VERSION 5.8 ;
BUSBITCHARS "[]" ;
DIVIDERCHAR "/" ;

PROPERTYDEFINITIONS
  MACRO CatenaDesignType STRING ;
  MACRO oaTaper STRING ;
END PROPERTYDEFINITIONS

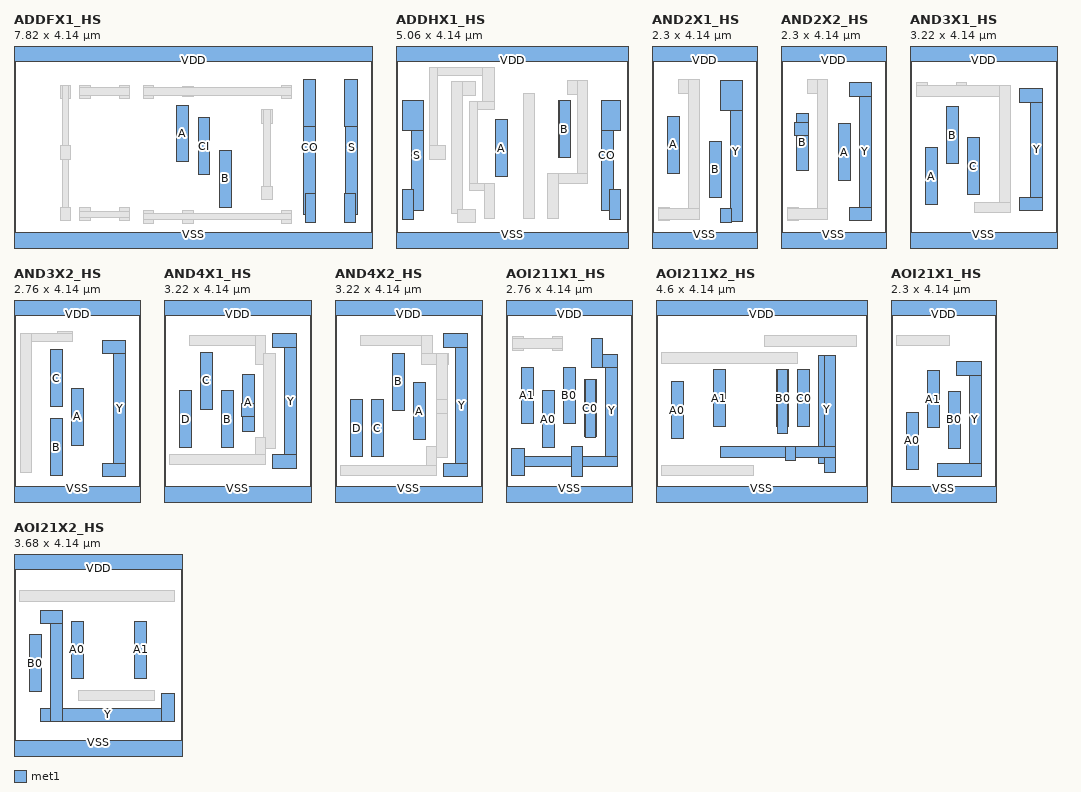
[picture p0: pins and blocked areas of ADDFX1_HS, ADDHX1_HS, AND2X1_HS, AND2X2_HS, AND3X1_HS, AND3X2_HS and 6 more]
MACRO ADDFX1_HS
  CLASS CORE ;
  ORIGIN 0 0 ;
  FOREIGN ADDFX1_HS 0 0 ;
  SIZE 7.82 BY 4.14 ;
  SYMMETRY X Y ;
  SITE CoreSite ;
  PIN A
    DIRECTION INPUT ;
    USE SIGNAL ;
    ANTENNAMODEL OXIDE1 ;
      ANTENNAGATEAREA 0.723 LAYER met1 ;
      ANTENNAMAXAREACAR 1.168603 LAYER met1 ;
      ANTENNAMAXSIDEAREACAR 1.233748 LAYER met1 ;
    PORT
      LAYER met1 ;
        RECT 3.55 1.745 3.81 2.985 ;
    END
  END A
  PIN B
    DIRECTION INPUT ;
    USE SIGNAL ;
    ANTENNAMODEL OXIDE1 ;
      ANTENNAGATEAREA 0.723 LAYER met1 ;
      ANTENNAMAXAREACAR 1.168603 LAYER met1 ;
      ANTENNAMAXSIDEAREACAR 1.233748 LAYER met1 ;
    PORT
      LAYER met1 ;
        RECT 4.47 0.76 4.73 2 ;
    END
  END B
  PIN CI
    DIRECTION INPUT ;
    USE SIGNAL ;
    ANTENNAMODEL OXIDE1 ;
      ANTENNAGATEAREA 0.54225 LAYER met1 ;
      ANTENNAMAXAREACAR 1.504841 LAYER met1 ;
      ANTENNAMAXSIDEAREACAR 1.644998 LAYER met1 ;
    PORT
      LAYER met1 ;
        RECT 4.01 1.47 4.27 2.71 ;
        RECT 4.025 1.465 4.255 2.71 ;
    END
  END CI
  PIN CO
    DIRECTION OUTPUT ;
    USE SIGNAL ;
    ANTENNADIFFAREA 0.5883 LAYER met1 ;
    PORT
      LAYER met1 ;
        RECT 6.31 2.52 6.575 3.53 ;
        RECT 6.345 0.415 6.575 1.065 ;
        RECT 6.31 0.61 6.57 3.53 ;
    END
  END CO
  PIN S
    DIRECTION OUTPUT ;
    USE SIGNAL ;
    ANTENNADIFFAREA 0.5883 LAYER met1 ;
    PORT
      LAYER met1 ;
        RECT 7.205 2.52 7.49 3.53 ;
        RECT 7.23 0.61 7.49 3.53 ;
        RECT 7.205 0.415 7.435 1.065 ;
    END
  END S
  PIN VDD
    DIRECTION INPUT ;
    USE POWER ;
    SHAPE ABUTMENT ;
    NETEXPR "VDD VDD!" ;
    PORT
      LAYER met1 ;
        RECT 0 3.94 7.82 4.34 ;
    END
  END VDD
  PIN VSS
    DIRECTION INPUT ;
    USE GROUND ;
    SHAPE ABUTMENT ;
    NETEXPR "VSS VSS!" ;
    PORT
      LAYER met1 ;
        RECT 0 -0.2 7.82 0.2 ;
    END
  END VSS
  OBS
    LAYER met1 ;
      RECT 5.825 0.405 6.055 0.695 ;
      RECT 3.675 0.405 3.905 0.695 ;
      RECT 2.815 0.405 3.045 0.695 ;
      RECT 2.815 0.48 6.055 0.62 ;
      RECT 5.825 3.13 6.055 3.42 ;
      RECT 2.815 3.13 3.045 3.42 ;
      RECT 3.675 3.16 3.905 3.39 ;
      RECT 2.815 3.19 6.055 3.36 ;
      RECT 5.395 2.59 5.625 2.88 ;
      RECT 5.44 0.93 5.58 2.88 ;
      RECT 5.395 0.93 5.625 1.22 ;
      RECT 2.295 0.46 2.525 0.75 ;
      RECT 1.435 0.46 1.665 0.75 ;
      RECT 1.435 0.535 2.525 0.675 ;
      RECT 2.295 3.13 2.525 3.42 ;
      RECT 1.435 3.13 1.665 3.42 ;
      RECT 1.435 3.19 2.525 3.36 ;
      RECT 1.005 3.13 1.235 3.42 ;
      RECT 1.05 0.46 1.19 3.42 ;
      RECT 1.005 1.805 1.235 2.095 ;
      RECT 1.005 0.46 1.235 0.75 ;
  END
  PROPERTY CatenaDesignType "deviceLevel" ;
END ADDFX1_HS

MACRO ADDHX1_HS
  CLASS CORE ;
  ORIGIN 0 0 ;
  FOREIGN ADDHX1_HS 0 0 ;
  SIZE 5.06 BY 4.14 ;
  SYMMETRY X Y ;
  SITE CoreSite ;
  PIN A
    DIRECTION INPUT ;
    USE SIGNAL ;
    ANTENNAMODEL OXIDE1 ;
      ANTENNAGATEAREA 0.3615 LAYER met1 ;
      ANTENNAMAXAREACAR 1.184509 LAYER met1 ;
      ANTENNAMAXSIDEAREACAR 1.289073 LAYER met1 ;
    PORT
      LAYER met1 ;
        RECT 2.17 1.425 2.43 2.665 ;
    END
  END A
  PIN B
    DIRECTION INPUT ;
    USE SIGNAL ;
    ANTENNAMODEL OXIDE1 ;
      ANTENNAGATEAREA 0.54225 LAYER met1 ;
      ANTENNAMAXAREACAR 0.858276 LAYER met1 ;
      ANTENNAMAXSIDEAREACAR 0.870447 LAYER met1 ;
    PORT
      LAYER met1 ;
        RECT 3.55 1.84 3.81 3.08 ;
        RECT 3.565 1.835 3.795 3.08 ;
    END
  END B
  PIN CO
    DIRECTION OUTPUT ;
    USE SIGNAL ;
    ANTENNADIFFAREA 0.5883 LAYER met1 ;
    PORT
      LAYER met1 ;
        RECT 4.47 2.44 4.885 3.09 ;
        RECT 4.655 0.485 4.885 1.135 ;
        RECT 4.47 0.68 4.73 3.09 ;
    END
  END CO
  PIN S
    DIRECTION OUTPUT ;
    USE SIGNAL ;
    ANTENNADIFFAREA 0.5883 LAYER met1 ;
    PORT
      LAYER met1 ;
        RECT 0.145 2.44 0.59 3.09 ;
        RECT 0.33 0.68 0.59 3.09 ;
        RECT 0.145 0.485 0.375 1.135 ;
    END
  END S
  PIN VDD
    DIRECTION INPUT ;
    USE POWER ;
    SHAPE ABUTMENT ;
    NETEXPR "VDD VDD!" ;
    PORT
      LAYER met1 ;
        RECT 0 3.94 5.06 4.34 ;
    END
  END VDD
  PIN VSS
    DIRECTION INPUT ;
    USE GROUND ;
    SHAPE ABUTMENT ;
    NETEXPR "VSS VSS!" ;
    PORT
      LAYER met1 ;
        RECT 0 -0.2 5.06 0.2 ;
    END
  END VSS
  OBS
    LAYER met1 ;
      RECT 3.735 3.22 4.18 3.51 ;
      RECT 3.95 1.265 4.18 3.51 ;
      RECT 3.305 1.265 4.18 1.495 ;
      RECT 3.305 0.51 3.535 1.495 ;
      RECT 0.73 3.63 2.155 3.8 ;
      RECT 1.895 2.89 2.155 3.8 ;
      RECT 0.73 1.805 0.9 3.8 ;
      RECT 1.605 2.89 2.155 3.06 ;
      RECT 1.605 1.115 1.775 3.06 ;
      RECT 0.73 1.805 1.08 2.095 ;
      RECT 1.605 1.115 2.155 1.285 ;
      RECT 1.925 0.51 2.155 1.285 ;
      RECT 1.22 3.2 1.725 3.49 ;
      RECT 1.22 0.615 1.45 3.49 ;
      RECT 1.335 0.42 1.725 0.71 ;
      RECT 2.785 0.51 3.015 3.235 ;
  END
  PROPERTY CatenaDesignType "deviceLevel" ;
END ADDHX1_HS

MACRO AND2X1_HS
  CLASS CORE ;
  ORIGIN 0 0 ;
  FOREIGN AND2X1_HS 0 0 ;
  SIZE 2.3 BY 4.14 ;
  SYMMETRY X Y ;
  SITE CoreSite ;
  PIN A
    DIRECTION INPUT ;
    USE SIGNAL ;
    ANTENNAMODEL OXIDE1 ;
      ANTENNAGATEAREA 0.18075 LAYER met1 ;
      ANTENNAMAXAREACAR 0.484371 LAYER met1 ;
      ANTENNAMAXSIDEAREACAR 0.569848 LAYER met1 ;
    PORT
      LAYER met1 ;
        RECT 0.33 1.5 0.59 2.74 ;
    END
  END A
  PIN B
    DIRECTION INPUT ;
    USE SIGNAL ;
    ANTENNAMODEL OXIDE1 ;
      ANTENNAGATEAREA 0.18075 LAYER met1 ;
      ANTENNAMAXAREACAR 0.917012 LAYER met1 ;
      ANTENNAMAXSIDEAREACAR 1.078838 LAYER met1 ;
    PORT
      LAYER met1 ;
        RECT 1.25 0.96 1.51 2.2 ;
    END
  END B
  PIN VDD
    DIRECTION INPUT ;
    USE POWER ;
    SHAPE ABUTMENT ;
    NETEXPR "VDD VDD!" ;
    PORT
      LAYER met1 ;
        RECT 0 3.94 2.3 4.34 ;
    END
  END VDD
  PIN VSS
    DIRECTION INPUT ;
    USE GROUND ;
    SHAPE ABUTMENT ;
    NETEXPR "VSS VSS!" ;
    PORT
      LAYER met1 ;
        RECT 0 -0.2 2.3 0.2 ;
    END
  END VSS
  PIN Y
    DIRECTION OUTPUT ;
    USE SIGNAL ;
    ANTENNADIFFAREA 0.5883 LAYER met1 ;
    PORT
      LAYER met1 ;
        RECT 1.495 2.86 1.97 3.51 ;
        RECT 1.71 0.44 1.97 3.51 ;
        RECT 1.495 0.43 1.725 0.72 ;
    END
  END Y
  OBS
    LAYER met1 ;
      RECT 0.575 3.24 1.03 3.53 ;
      RECT 0.8 0.49 1.03 3.53 ;
      RECT 0.145 0.46 0.375 0.75 ;
      RECT 0.145 0.49 1.03 0.72 ;
  END
  PROPERTY CatenaDesignType "deviceLevel" ;
END AND2X1_HS

MACRO AND2X2_HS
  CLASS CORE ;
  ORIGIN 0 0 ;
  FOREIGN AND2X2_HS 0 0 ;
  SIZE 2.3 BY 4.14 ;
  SYMMETRY X Y ;
  SITE CoreSite ;
  PIN A
    DIRECTION INPUT ;
    USE SIGNAL ;
    ANTENNAMODEL OXIDE1 ;
      ANTENNAGATEAREA 0.18075 LAYER met1 ;
      ANTENNAMAXAREACAR 0.935823 LAYER met1 ;
      ANTENNAMAXSIDEAREACAR 1.100968 LAYER met1 ;
    PORT
      LAYER met1 ;
        RECT 1.25 1.34 1.51 2.58 ;
    END
  END A
  PIN B
    DIRECTION INPUT ;
    USE SIGNAL ;
    ANTENNAMODEL OXIDE1 ;
      ANTENNAGATEAREA 0.18075 LAYER met1 ;
      ANTENNAMAXAREACAR 0.672476 LAYER met1 ;
      ANTENNAMAXSIDEAREACAR 0.791148 LAYER met1 ;
    PORT
      LAYER met1 ;
        RECT 0.33 1.55 0.59 2.79 ;
        RECT 0.285 2.31 0.59 2.6 ;
    END
  END B
  PIN VDD
    DIRECTION INPUT ;
    USE POWER ;
    SHAPE ABUTMENT ;
    NETEXPR "VDD VDD!" ;
    PORT
      LAYER met1 ;
        RECT 0 3.94 2.3 4.34 ;
    END
  END VDD
  PIN VSS
    DIRECTION INPUT ;
    USE GROUND ;
    SHAPE ABUTMENT ;
    NETEXPR "VSS VSS!" ;
    PORT
      LAYER met1 ;
        RECT 0 -0.2 2.3 0.2 ;
    END
  END VSS
  PIN Y
    DIRECTION OUTPUT ;
    USE SIGNAL ;
    ANTENNADIFFAREA 0.6216 LAYER met1 ;
    PORT
      LAYER met1 ;
        RECT 1.495 3.18 1.97 3.47 ;
        RECT 1.71 0.46 1.97 3.47 ;
        RECT 1.495 0.46 1.97 0.75 ;
    END
  END Y
  OBS
    LAYER met1 ;
      RECT 0.575 3.24 1.02 3.53 ;
      RECT 0.79 0.685 1.02 3.53 ;
      RECT 0.145 0.46 0.375 0.75 ;
      RECT 0.145 0.49 1.015 0.72 ;
  END
  PROPERTY CatenaDesignType "deviceLevel" ;
END AND2X2_HS

MACRO AND3X1_HS
  CLASS CORE ;
  ORIGIN 0 0 ;
  FOREIGN AND3X1_HS 0 0 ;
  SIZE 3.22 BY 4.14 ;
  SYMMETRY X Y ;
  SITE CoreSite ;
  PIN A
    DIRECTION INPUT ;
    USE SIGNAL ;
    ANTENNAMODEL OXIDE1 ;
      ANTENNAGATEAREA 0.18075 LAYER met1 ;
      ANTENNAMAXAREACAR 0.658368 LAYER met1 ;
      ANTENNAMAXSIDEAREACAR 0.77455 LAYER met1 ;
    PORT
      LAYER met1 ;
        RECT 0.33 0.815 0.59 2.055 ;
    END
  END A
  PIN B
    DIRECTION INPUT ;
    USE SIGNAL ;
    ANTENNAMODEL OXIDE1 ;
      ANTENNAGATEAREA 0.18075 LAYER met1 ;
      ANTENNAMAXAREACAR 0.691286 LAYER met1 ;
      ANTENNAMAXSIDEAREACAR 0.813278 LAYER met1 ;
    PORT
      LAYER met1 ;
        RECT 0.79 1.705 1.05 2.945 ;
    END
  END B
  PIN C
    DIRECTION INPUT ;
    USE SIGNAL ;
    ANTENNAMODEL OXIDE1 ;
      ANTENNAGATEAREA 0.18075 LAYER met1 ;
      ANTENNAMAXAREACAR 0.489073 LAYER met1 ;
      ANTENNAMAXSIDEAREACAR 0.57538 LAYER met1 ;
    PORT
      LAYER met1 ;
        RECT 1.25 1.03 1.51 2.27 ;
    END
  END C
  PIN VDD
    DIRECTION INPUT ;
    USE POWER ;
    SHAPE ABUTMENT ;
    NETEXPR "VDD VDD!" ;
    PORT
      LAYER met1 ;
        RECT 0 3.94 3.22 4.34 ;
    END
  END VDD
  PIN VSS
    DIRECTION INPUT ;
    USE GROUND ;
    SHAPE ABUTMENT ;
    NETEXPR "VSS VSS!" ;
    PORT
      LAYER met1 ;
        RECT 0 -0.2 3.22 0.2 ;
    END
  END VSS
  PIN Y
    DIRECTION OUTPUT ;
    USE SIGNAL ;
    ANTENNADIFFAREA 0.5883 LAYER met1 ;
    PORT
      LAYER met1 ;
        RECT 2.385 3.045 2.89 3.335 ;
        RECT 2.63 0.69 2.89 3.335 ;
        RECT 2.385 0.69 2.89 0.98 ;
    END
  END Y
  OBS
    LAYER met1 ;
      RECT 1.005 3.175 1.235 3.465 ;
      RECT 0.145 3.175 0.375 3.465 ;
      RECT 0.145 3.175 2.19 3.405 ;
      RECT 1.96 0.64 2.19 3.405 ;
      RECT 1.405 0.64 2.19 0.87 ;
  END
  PROPERTY CatenaDesignType "deviceLevel" ;
END AND3X1_HS

MACRO AND3X2_HS
  CLASS CORE ;
  ORIGIN 0 0 ;
  FOREIGN AND3X2_HS 0 0 ;
  SIZE 2.76 BY 4.14 ;
  SYMMETRY X Y ;
  SITE CoreSite ;
  PIN A
    DIRECTION INPUT ;
    USE SIGNAL ;
    ANTENNAMODEL OXIDE1 ;
      ANTENNAGATEAREA 0.18075 LAYER met1 ;
      ANTENNAMAXAREACAR 0.512586 LAYER met1 ;
      ANTENNAMAXSIDEAREACAR 0.603043 LAYER met1 ;
    PORT
      LAYER met1 ;
        RECT 1.25 1.105 1.51 2.345 ;
    END
  END A
  PIN B
    DIRECTION INPUT ;
    USE SIGNAL ;
    ANTENNAMODEL OXIDE1 ;
      ANTENNAGATEAREA 0.18075 LAYER met1 ;
      ANTENNAMAXAREACAR 0.470263 LAYER met1 ;
      ANTENNAMAXSIDEAREACAR 0.55325 LAYER met1 ;
    PORT
      LAYER met1 ;
        RECT 0.79 0.44 1.05 1.68 ;
    END
  END B
  PIN C
    DIRECTION INPUT ;
    USE SIGNAL ;
    ANTENNAMODEL OXIDE1 ;
      ANTENNAGATEAREA 0.18075 LAYER met1 ;
      ANTENNAMAXAREACAR 0.91231 LAYER met1 ;
      ANTENNAMAXSIDEAREACAR 1.073306 LAYER met1 ;
    PORT
      LAYER met1 ;
        RECT 0.79 1.945 1.05 3.185 ;
    END
  END C
  PIN VDD
    DIRECTION INPUT ;
    USE POWER ;
    SHAPE ABUTMENT ;
    NETEXPR "VDD VDD!" ;
    PORT
      LAYER met1 ;
        RECT 0 3.94 2.76 4.34 ;
    END
  END VDD
  PIN VSS
    DIRECTION INPUT ;
    USE GROUND ;
    SHAPE ABUTMENT ;
    NETEXPR "VSS VSS!" ;
    PORT
      LAYER met1 ;
        RECT 0 -0.2 2.76 0.2 ;
    END
  END VSS
  PIN Y
    DIRECTION OUTPUT ;
    USE SIGNAL ;
    ANTENNADIFFAREA 0.6216 LAYER met1 ;
    PORT
      LAYER met1 ;
        RECT 1.925 3.095 2.43 3.385 ;
        RECT 2.17 0.415 2.43 3.385 ;
        RECT 1.925 0.415 2.43 0.705 ;
    END
  END Y
  OBS
    LAYER met1 ;
      RECT 0.955 3.36 1.285 3.59 ;
      RECT 0.145 3.36 1.285 3.53 ;
      RECT 0.145 0.51 0.375 3.53 ;
  END
  PROPERTY CatenaDesignType "deviceLevel" ;
END AND3X2_HS

MACRO AND4X1_HS
  CLASS CORE ;
  ORIGIN 0 0 ;
  FOREIGN AND4X1_HS 0 0 ;
  SIZE 3.22 BY 4.14 ;
  SYMMETRY X Y ;
  SITE CoreSite ;
  PIN A
    DIRECTION INPUT ;
    USE SIGNAL ;
    ANTENNAMODEL OXIDE1 ;
      ANTENNAGATEAREA 0.18075 LAYER met1 ;
      ANTENNAMAXAREACAR 0.545505 LAYER met1 ;
      ANTENNAMAXSIDEAREACAR 0.64177 LAYER met1 ;
    PORT
      LAYER met1 ;
        RECT 1.71 1.41 1.97 2.65 ;
        RECT 1.68 1.73 1.97 2.02 ;
    END
  END A
  PIN B
    DIRECTION INPUT ;
    USE SIGNAL ;
    ANTENNAMODEL OXIDE1 ;
      ANTENNAGATEAREA 0.18075 LAYER met1 ;
      ANTENNAMAXAREACAR 0.5361 LAYER met1 ;
      ANTENNAMAXSIDEAREACAR 0.630705 LAYER met1 ;
    PORT
      LAYER met1 ;
        RECT 1.25 1.055 1.51 2.295 ;
    END
  END B
  PIN C
    DIRECTION INPUT ;
    USE SIGNAL ;
    ANTENNAMODEL OXIDE1 ;
      ANTENNAGATEAREA 0.18075 LAYER met1 ;
      ANTENNAMAXAREACAR 0.489073 LAYER met1 ;
      ANTENNAMAXSIDEAREACAR 0.57538 LAYER met1 ;
    PORT
      LAYER met1 ;
        RECT 0.79 1.89 1.05 3.13 ;
    END
  END C
  PIN D
    DIRECTION INPUT ;
    USE SIGNAL ;
    ANTENNAMODEL OXIDE1 ;
      ANTENNAGATEAREA 0.18075 LAYER met1 ;
      ANTENNAMAXAREACAR 0.484371 LAYER met1 ;
      ANTENNAMAXSIDEAREACAR 0.569848 LAYER met1 ;
    PORT
      LAYER met1 ;
        RECT 0.33 1.055 0.59 2.295 ;
    END
  END D
  PIN VDD
    DIRECTION INPUT ;
    USE POWER ;
    SHAPE ABUTMENT ;
    NETEXPR "VDD VDD!" ;
    PORT
      LAYER met1 ;
        RECT 0 3.94 3.22 4.34 ;
    END
  END VDD
  PIN VSS
    DIRECTION INPUT ;
    USE GROUND ;
    SHAPE ABUTMENT ;
    NETEXPR "VSS VSS!" ;
    PORT
      LAYER met1 ;
        RECT 0 -0.2 3.22 0.2 ;
    END
  END VSS
  PIN Y
    DIRECTION OUTPUT ;
    USE SIGNAL ;
    ANTENNADIFFAREA 0.5883 LAYER met1 ;
    PORT
      LAYER met1 ;
        RECT 2.355 3.24 2.89 3.53 ;
        RECT 2.63 0.61 2.89 3.53 ;
        RECT 2.355 0.61 2.89 0.9 ;
    END
  END Y
  OBS
    LAYER met1 ;
      RECT 0.545 3.27 2.215 3.5 ;
      RECT 1.985 2.87 2.215 3.5 ;
      RECT 2.17 1.04 2.43 3.1 ;
      RECT 1.985 0.685 2.215 1.27 ;
      RECT 0.115 0.685 2.215 0.915 ;
  END
  PROPERTY CatenaDesignType "deviceLevel" ;
END AND4X1_HS

MACRO AND4X2_HS
  CLASS CORE ;
  ORIGIN 0 0 ;
  FOREIGN AND4X2_HS 0 0 ;
  SIZE 3.22 BY 4.14 ;
  SYMMETRY X Y ;
  SITE CoreSite ;
  PIN A
    DIRECTION INPUT ;
    USE SIGNAL ;
    ANTENNAMODEL OXIDE1 ;
      ANTENNAGATEAREA 0.18075 LAYER met1 ;
      ANTENNAMAXAREACAR 0.757123 LAYER met1 ;
      ANTENNAMAXSIDEAREACAR 0.890733 LAYER met1 ;
    PORT
      LAYER met1 ;
        RECT 1.71 1.23 1.97 2.47 ;
    END
  END A
  PIN B
    DIRECTION INPUT ;
    USE SIGNAL ;
    ANTENNAMODEL OXIDE1 ;
      ANTENNAGATEAREA 0.18075 LAYER met1 ;
      ANTENNAMAXAREACAR 0.719502 LAYER met1 ;
      ANTENNAMAXSIDEAREACAR 0.846473 LAYER met1 ;
    PORT
      LAYER met1 ;
        RECT 1.25 1.865 1.51 3.105 ;
    END
  END B
  PIN C
    DIRECTION INPUT ;
    USE SIGNAL ;
    ANTENNAMODEL OXIDE1 ;
      ANTENNAGATEAREA 0.18075 LAYER met1 ;
      ANTENNAMAXAREACAR 0.681881 LAYER met1 ;
      ANTENNAMAXSIDEAREACAR 0.802213 LAYER met1 ;
    PORT
      LAYER met1 ;
        RECT 0.79 0.86 1.05 2.1 ;
    END
  END C
  PIN D
    DIRECTION INPUT ;
    USE SIGNAL ;
    ANTENNAMODEL OXIDE1 ;
      ANTENNAGATEAREA 0.18075 LAYER met1 ;
      ANTENNAMAXAREACAR 0.681881 LAYER met1 ;
      ANTENNAMAXSIDEAREACAR 0.802213 LAYER met1 ;
    PORT
      LAYER met1 ;
        RECT 0.33 0.86 0.59 2.1 ;
    END
  END D
  PIN VDD
    DIRECTION INPUT ;
    USE POWER ;
    SHAPE ABUTMENT ;
    NETEXPR "VDD VDD!" ;
    PORT
      LAYER met1 ;
        RECT 0 3.94 3.22 4.34 ;
    END
  END VDD
  PIN VSS
    DIRECTION INPUT ;
    USE GROUND ;
    SHAPE ABUTMENT ;
    NETEXPR "VSS VSS!" ;
    PORT
      LAYER met1 ;
        RECT 0 -0.2 3.22 0.2 ;
    END
  END VSS
  PIN Y
    DIRECTION OUTPUT ;
    USE SIGNAL ;
    ANTENNADIFFAREA 0.6216 LAYER met1 ;
    PORT
      LAYER met1 ;
        RECT 2.355 3.24 2.89 3.53 ;
        RECT 2.63 0.415 2.89 3.53 ;
        RECT 2.355 0.415 2.89 0.705 ;
    END
  END Y
  OBS
    LAYER met1 ;
      RECT 0.545 3.27 2.125 3.5 ;
      RECT 1.895 2.87 2.125 3.5 ;
      RECT 1.895 2.87 2.48 3.1 ;
      RECT 2.215 0.845 2.445 3.1 ;
      RECT 2.21 1.805 2.445 2.095 ;
      RECT 1.985 0.445 2.215 1.075 ;
      RECT 0.115 0.445 2.215 0.675 ;
  END
  PROPERTY CatenaDesignType "deviceLevel" ;
END AND4X2_HS

MACRO AOI211X1_HS
  CLASS CORE ;
  ORIGIN 0 0 ;
  FOREIGN AOI211X1_HS 0 0 ;
  SIZE 2.76 BY 4.14 ;
  SYMMETRY X Y ;
  SITE CoreSite ;
  PIN A0
    DIRECTION INPUT ;
    USE SIGNAL ;
    ANTENNAMODEL OXIDE1 ;
      ANTENNAGATEAREA 0.333 LAYER met1 ;
      ANTENNAMAXAREACAR 0.262913 LAYER met1 ;
      ANTENNAMAXSIDEAREACAR 0.309309 LAYER met1 ;
    PORT
      LAYER met1 ;
        RECT 0.79 1.05 1.05 2.29 ;
    END
  END A0
  PIN A1
    DIRECTION INPUT ;
    USE SIGNAL ;
    ANTENNAMODEL OXIDE1 ;
      ANTENNAGATEAREA 0.333 LAYER met1 ;
      ANTENNAMAXAREACAR 0.262913 LAYER met1 ;
      ANTENNAMAXSIDEAREACAR 0.309309 LAYER met1 ;
    PORT
      LAYER met1 ;
        RECT 0.33 1.57 0.59 2.81 ;
    END
  END A1
  PIN B0
    DIRECTION INPUT ;
    USE SIGNAL ;
    ANTENNAMODEL OXIDE1 ;
      ANTENNAGATEAREA 0.333 LAYER met1 ;
      ANTENNAMAXAREACAR 0.278228 LAYER met1 ;
      ANTENNAMAXSIDEAREACAR 0.327327 LAYER met1 ;
    PORT
      LAYER met1 ;
        RECT 1.25 1.57 1.51 2.81 ;
    END
  END B0
  PIN C0
    DIRECTION INPUT ;
    USE SIGNAL ;
    ANTENNAMODEL OXIDE1 ;
      ANTENNAGATEAREA 0.333 LAYER met1 ;
      ANTENNAMAXAREACAR 0.293544 LAYER met1 ;
      ANTENNAMAXSIDEAREACAR 0.345345 LAYER met1 ;
    PORT
      LAYER met1 ;
        RECT 1.71 1.29 1.97 2.53 ;
        RECT 1.725 1.285 1.955 2.53 ;
    END
  END C0
  PIN VDD
    DIRECTION INPUT ;
    USE POWER ;
    SHAPE ABUTMENT ;
    NETEXPR "VDD VDD!" ;
    PORT
      LAYER met1 ;
        RECT 0 3.94 2.76 4.34 ;
    END
  END VDD
  PIN VSS
    DIRECTION INPUT ;
    USE GROUND ;
    SHAPE ABUTMENT ;
    NETEXPR "VSS VSS!" ;
    PORT
      LAYER met1 ;
        RECT 0 -0.2 2.76 0.2 ;
    END
  END VSS
  PIN Y
    DIRECTION OUTPUT ;
    USE SIGNAL ;
    ANTENNADIFFAREA 0.8011 LAYER met1 ;
    PORT
      LAYER met1 ;
        RECT 1.87 2.79 2.43 3.08 ;
        RECT 2.17 0.64 2.43 3.08 ;
        RECT 0.115 0.64 2.43 0.87 ;
        RECT 1.87 2.79 2.1 3.44 ;
        RECT 1.435 0.43 1.665 1.08 ;
        RECT 0.115 0.445 0.405 1.035 ;
    END
  END Y
  OBS
    LAYER met1 ;
      RECT 1.005 3.18 1.235 3.47 ;
      RECT 0.145 3.18 0.375 3.47 ;
      RECT 0.145 3.21 1.235 3.44 ;
  END
  PROPERTY CatenaDesignType "deviceLevel" ;
END AOI211X1_HS

MACRO AOI211X2_HS
  CLASS CORE ;
  ORIGIN 0 0 ;
  FOREIGN AOI211X2_HS 0 0 ;
  SIZE 4.6 BY 4.14 ;
  SYMMETRY X Y ;
  SITE CoreSite ;
  PIN A0
    DIRECTION INPUT ;
    USE SIGNAL ;
    ANTENNAMODEL OXIDE1 ;
      ANTENNAGATEAREA 0.666 LAYER met1 ;
      ANTENNAMAXAREACAR 0.279505 LAYER met1 ;
      ANTENNAMAXSIDEAREACAR 0.277778 LAYER met1 ;
    PORT
      LAYER met1 ;
        RECT 0.33 1.25 0.59 2.49 ;
    END
  END A0
  PIN A1
    DIRECTION INPUT ;
    USE SIGNAL ;
    ANTENNAMODEL OXIDE1 ;
      ANTENNAGATEAREA 0.666 LAYER met1 ;
      ANTENNAMAXAREACAR 0.270571 LAYER met1 ;
      ANTENNAMAXSIDEAREACAR 0.267267 LAYER met1 ;
    PORT
      LAYER met1 ;
        RECT 1.25 1.51 1.51 2.75 ;
    END
  END A1
  PIN B0
    DIRECTION INPUT ;
    USE SIGNAL ;
    ANTENNAMODEL OXIDE1 ;
      ANTENNAGATEAREA 0.666 LAYER met1 ;
      ANTENNAMAXAREACAR 0.295345 LAYER met1 ;
      ANTENNAMAXSIDEAREACAR 0.282282 LAYER met1 ;
    PORT
      LAYER met1 ;
        RECT 2.63 1.51 2.89 2.75 ;
        RECT 2.645 1.37 2.875 2.75 ;
    END
  END B0
  PIN C0
    DIRECTION INPUT ;
    USE SIGNAL ;
    ANTENNAMODEL OXIDE1 ;
      ANTENNAGATEAREA 0.666 LAYER met1 ;
      ANTENNAMAXAREACAR 0.366291 LAYER met1 ;
      ANTENNAMAXSIDEAREACAR 0.37988 LAYER met1 ;
    PORT
      LAYER met1 ;
        RECT 3.09 1.51 3.35 2.75 ;
    END
  END C0
  PIN VDD
    DIRECTION INPUT ;
    USE POWER ;
    SHAPE ABUTMENT ;
    NETEXPR "VDD VDD!" ;
    PORT
      LAYER met1 ;
        RECT 0 3.94 4.6 4.34 ;
    END
  END VDD
  PIN VSS
    DIRECTION INPUT ;
    USE GROUND ;
    SHAPE ABUTMENT ;
    NETEXPR "VSS VSS!" ;
    PORT
      LAYER met1 ;
        RECT 0 -0.2 4.6 0.2 ;
    END
  END VSS
  PIN Y
    DIRECTION OUTPUT ;
    USE SIGNAL ;
    ANTENNADIFFAREA 1.0472 LAYER met1 ;
    PORT
      LAYER met1 ;
        RECT 3.55 0.7 3.905 3.07 ;
        RECT 3.675 0.505 3.905 3.07 ;
        RECT 1.405 0.84 3.905 1.07 ;
        RECT 2.815 0.775 3.045 1.07 ;
    END
  END Y
  OBS
    LAYER met1 ;
      RECT 2.355 3.26 4.365 3.49 ;
      RECT 0.11 2.89 3.075 3.12 ;
      RECT 0.11 0.445 2.12 0.675 ;
  END
  PROPERTY CatenaDesignType "deviceLevel" ;
END AOI211X2_HS

MACRO AOI21X1_HS
  CLASS CORE ;
  ORIGIN 0 0 ;
  FOREIGN AOI21X1_HS 0 0 ;
  SIZE 2.3 BY 4.14 ;
  SYMMETRY X Y ;
  SITE CoreSite ;
  PIN A0
    DIRECTION INPUT ;
    USE SIGNAL ;
    ANTENNAMODEL OXIDE1 ;
      ANTENNAGATEAREA 0.333 LAYER met1 ;
      ANTENNAMAXAREACAR 0.324174 LAYER met1 ;
      ANTENNAMAXSIDEAREACAR 0.381381 LAYER met1 ;
    PORT
      LAYER met1 ;
        RECT 0.33 0.58 0.59 1.82 ;
    END
  END A0
  PIN A1
    DIRECTION INPUT ;
    USE SIGNAL ;
    ANTENNAMODEL OXIDE1 ;
      ANTENNAGATEAREA 0.333 LAYER met1 ;
      ANTENNAMAXAREACAR 0.296096 LAYER met1 ;
      ANTENNAMAXSIDEAREACAR 0.348348 LAYER met1 ;
    PORT
      LAYER met1 ;
        RECT 0.79 1.49 1.05 2.73 ;
    END
  END A1
  PIN B0
    DIRECTION INPUT ;
    USE SIGNAL ;
    ANTENNAMODEL OXIDE1 ;
      ANTENNAGATEAREA 0.333 LAYER met1 ;
      ANTENNAMAXAREACAR 0.321622 LAYER met1 ;
      ANTENNAMAXSIDEAREACAR 0.378378 LAYER met1 ;
    PORT
      LAYER met1 ;
        RECT 1.25 1.04 1.51 2.28 ;
    END
  END B0
  PIN VDD
    DIRECTION INPUT ;
    USE POWER ;
    SHAPE ABUTMENT ;
    NETEXPR "VDD VDD!" ;
    PORT
      LAYER met1 ;
        RECT 0 3.94 2.3 4.34 ;
    END
  END VDD
  PIN VSS
    DIRECTION INPUT ;
    USE GROUND ;
    SHAPE ABUTMENT ;
    NETEXPR "VSS VSS!" ;
    PORT
      LAYER met1 ;
        RECT 0 -0.2 2.3 0.2 ;
    END
  END VSS
  PIN Y
    DIRECTION OUTPUT ;
    USE SIGNAL ;
    ANTENNADIFFAREA 0.5997 LAYER met1 ;
    PORT
      LAYER met1 ;
        RECT 1.435 2.635 1.97 2.925 ;
        RECT 1.71 0.415 1.97 2.925 ;
        RECT 1.005 0.415 1.97 0.705 ;
    END
  END Y
  OBS
    LAYER met1 ;
      RECT 0.115 3.27 1.265 3.5 ;
  END
  PROPERTY CatenaDesignType "deviceLevel" ;
END AOI21X1_HS

MACRO AOI21X2_HS
  CLASS CORE ;
  ORIGIN 0 0 ;
  FOREIGN AOI21X2_HS 0 0 ;
  SIZE 3.68 BY 4.14 ;
  SYMMETRY X Y ;
  SITE CoreSite ;
  PIN A0
    DIRECTION INPUT ;
    USE SIGNAL ;
    ANTENNAMODEL OXIDE1 ;
      ANTENNAGATEAREA 0.666 LAYER met1 ;
      ANTENNAMAXAREACAR 0.257808 LAYER met1 ;
      ANTENNAMAXSIDEAREACAR 0.252252 LAYER met1 ;
    PORT
      LAYER met1 ;
        RECT 1.25 1.565 1.51 2.805 ;
    END
  END A0
  PIN A1
    DIRECTION INPUT ;
    USE SIGNAL ;
    ANTENNAMODEL OXIDE1 ;
      ANTENNAGATEAREA 0.666 LAYER met1 ;
      ANTENNAMAXAREACAR 0.257808 LAYER met1 ;
      ANTENNAMAXSIDEAREACAR 0.252252 LAYER met1 ;
    PORT
      LAYER met1 ;
        RECT 2.63 1.56 2.89 2.8 ;
    END
  END A1
  PIN B0
    DIRECTION INPUT ;
    USE SIGNAL ;
    ANTENNAMODEL OXIDE1 ;
      ANTENNAGATEAREA 0.666 LAYER met1 ;
      ANTENNAMAXAREACAR 0.261637 LAYER met1 ;
      ANTENNAMAXSIDEAREACAR 0.256757 LAYER met1 ;
    PORT
      LAYER met1 ;
        RECT 0.33 1.27 0.59 2.51 ;
    END
  END B0
  PIN VDD
    DIRECTION INPUT ;
    USE POWER ;
    SHAPE ABUTMENT ;
    NETEXPR "VDD VDD!" ;
    PORT
      LAYER met1 ;
        RECT 0 3.94 3.68 4.34 ;
    END
  END VDD
  PIN VSS
    DIRECTION INPUT ;
    USE GROUND ;
    SHAPE ABUTMENT ;
    NETEXPR "VSS VSS!" ;
    PORT
      LAYER met1 ;
        RECT 0 -0.2 3.68 0.2 ;
    END
  END VSS
  PIN Y
    DIRECTION OUTPUT ;
    USE SIGNAL ;
    ANTENNADIFFAREA 1.0244 LAYER met1 ;
    PORT
      LAYER met1 ;
        RECT 3.215 0.625 3.505 1.23 ;
        RECT 0.575 0.625 3.505 0.915 ;
        RECT 0.575 2.755 1.05 3.045 ;
        RECT 0.79 0.625 1.05 3.045 ;
    END
  END Y
  OBS
    LAYER met1 ;
      RECT 0.115 3.24 3.505 3.47 ;
      RECT 1.405 1.07 3.07 1.3 ;
  END
  PROPERTY CatenaDesignType "deviceLevel" ;
END AOI21X2_HS

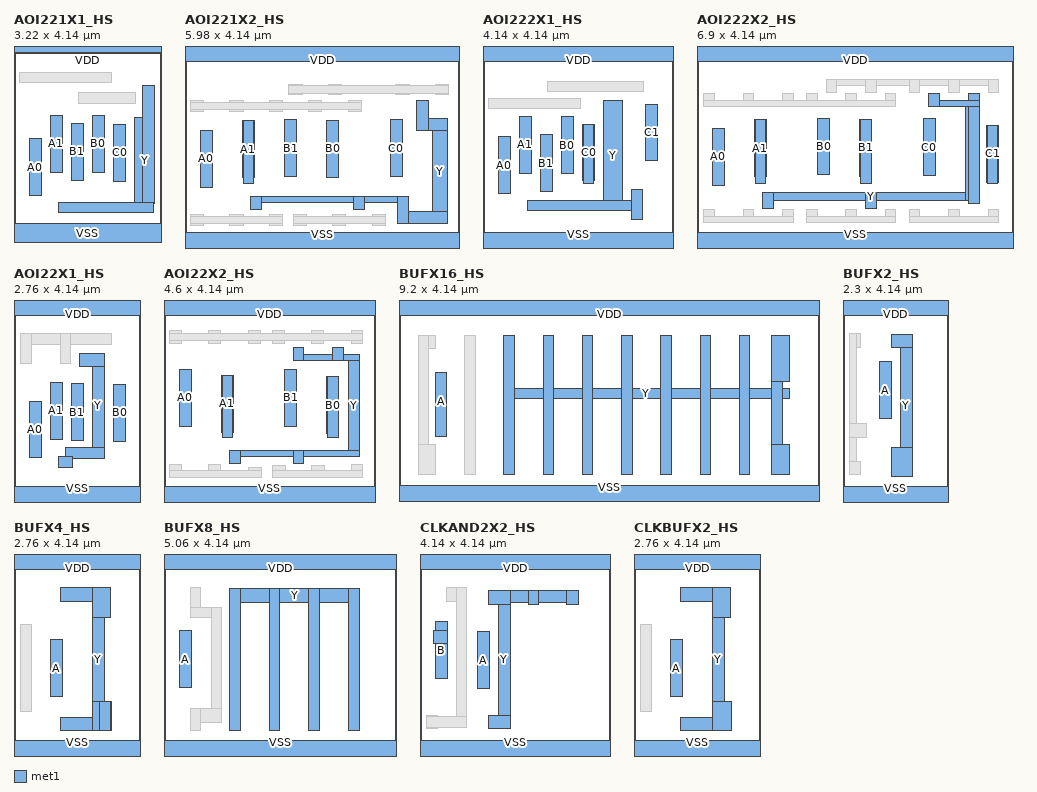
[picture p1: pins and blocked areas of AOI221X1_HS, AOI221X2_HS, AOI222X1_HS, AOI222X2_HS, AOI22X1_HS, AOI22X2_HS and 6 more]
MACRO AOI221X1_HS
  CLASS CORE ;
  ORIGIN 0 0.195 ;
  FOREIGN AOI221X1_HS 0 -0.195 ;
  SIZE 3.22 BY 4.14 ;
  SYMMETRY X Y ;
  SITE CoreSite ;
  PIN A0
    DIRECTION INPUT ;
    USE SIGNAL ;
    ANTENNAMODEL OXIDE1 ;
      ANTENNAGATEAREA 0.333 LAYER met1 ;
      ANTENNAMAXAREACAR 0.37012 LAYER met1 ;
      ANTENNAMAXSIDEAREACAR 0.435435 LAYER met1 ;
    PORT
      LAYER met1 ;
        RECT 0.33 0.81 0.59 2.05 ;
    END
  END A0
  PIN A1
    DIRECTION INPUT ;
    USE SIGNAL ;
    ANTENNAMODEL OXIDE1 ;
      ANTENNAGATEAREA 0.333 LAYER met1 ;
      ANTENNAMAXAREACAR 0.37012 LAYER met1 ;
      ANTENNAMAXSIDEAREACAR 0.435435 LAYER met1 ;
    PORT
      LAYER met1 ;
        RECT 0.79 1.325 1.05 2.565 ;
    END
  END A1
  PIN B0
    DIRECTION INPUT ;
    USE SIGNAL ;
    ANTENNAMODEL OXIDE1 ;
      ANTENNAGATEAREA 0.333 LAYER met1 ;
      ANTENNAMAXAREACAR 0.37012 LAYER met1 ;
      ANTENNAMAXSIDEAREACAR 0.435435 LAYER met1 ;
    PORT
      LAYER met1 ;
        RECT 1.71 1.325 1.97 2.565 ;
    END
  END B0
  PIN B1
    DIRECTION INPUT ;
    USE SIGNAL ;
    ANTENNAMODEL OXIDE1 ;
      ANTENNAGATEAREA 0.333 LAYER met1 ;
      ANTENNAMAXAREACAR 0.37012 LAYER met1 ;
      ANTENNAMAXSIDEAREACAR 0.435435 LAYER met1 ;
    PORT
      LAYER met1 ;
        RECT 1.25 1.15 1.51 2.39 ;
    END
  END B1
  PIN C0
    DIRECTION INPUT ;
    USE SIGNAL ;
    ANTENNAMODEL OXIDE1 ;
      ANTENNAGATEAREA 0.333 LAYER met1 ;
      ANTENNAMAXAREACAR 0.46967 LAYER met1 ;
      ANTENNAMAXSIDEAREACAR 0.552553 LAYER met1 ;
    PORT
      LAYER met1 ;
        RECT 2.17 1.13 2.43 2.37 ;
    END
  END C0
  PIN VDD
    DIRECTION INPUT ;
    USE POWER ;
    SHAPE ABUTMENT ;
    NETEXPR "VDD VDD!" ;
    PORT
      LAYER met1 ;
        RECT 0 3.94 3.22 4.34 ;
    END
  END VDD
  PIN VSS
    DIRECTION INPUT ;
    USE GROUND ;
    SHAPE ABUTMENT ;
    NETEXPR "VSS VSS!" ;
    PORT
      LAYER met1 ;
        RECT 0 -0.2 3.22 0.2 ;
    END
  END VSS
  PIN Y
    DIRECTION OUTPUT ;
    USE SIGNAL ;
    ANTENNADIFFAREA 0.8011 LAYER met1 ;
    PORT
      LAYER met1 ;
        RECT 2.8 0.64 3.06 3.215 ;
        RECT 0.975 0.445 3.045 0.675 ;
        RECT 2.63 0.64 3.06 2.525 ;
    END
  END Y
  OBS
    LAYER met1 ;
      RECT 1.405 2.83 2.645 3.06 ;
      RECT 0.115 3.27 2.125 3.5 ;
  END
  PROPERTY CatenaDesignType "deviceLevel" ;
END AOI221X1_HS

MACRO AOI221X2_HS
  CLASS CORE ;
  ORIGIN 0 0 ;
  FOREIGN AOI221X2_HS 0 0 ;
  SIZE 5.98 BY 4.14 ;
  SYMMETRY X Y ;
  SITE CoreSite ;
  PIN A0
    DIRECTION INPUT ;
    USE SIGNAL ;
    ANTENNAMODEL OXIDE1 ;
      ANTENNAGATEAREA 0.666 LAYER met1 ;
      ANTENNAMAXAREACAR 0.32545 LAYER met1 ;
      ANTENNAMAXSIDEAREACAR 0.331832 LAYER met1 ;
    PORT
      LAYER met1 ;
        RECT 0.33 1.19 0.59 2.43 ;
    END
  END A0
  PIN A1
    DIRECTION INPUT ;
    USE SIGNAL ;
    ANTENNAMODEL OXIDE1 ;
      ANTENNAGATEAREA 0.666 LAYER met1 ;
      ANTENNAMAXAREACAR 0.32545 LAYER met1 ;
      ANTENNAMAXSIDEAREACAR 0.331832 LAYER met1 ;
    PORT
      LAYER met1 ;
        RECT 1.25 1.4 1.51 2.64 ;
        RECT 1.265 1.285 1.495 2.64 ;
    END
  END A1
  PIN B0
    DIRECTION INPUT ;
    USE SIGNAL ;
    ANTENNAMODEL OXIDE1 ;
      ANTENNAGATEAREA 0.666 LAYER met1 ;
      ANTENNAMAXAREACAR 0.169745 LAYER met1 ;
      ANTENNAMAXSIDEAREACAR 0.1997 LAYER met1 ;
    PORT
      LAYER met1 ;
        RECT 3.09 1.415 3.35 2.655 ;
    END
  END B0
  PIN B1
    DIRECTION INPUT ;
    USE SIGNAL ;
    ANTENNAMODEL OXIDE1 ;
      ANTENNAGATEAREA 0.666 LAYER met1 ;
      ANTENNAMAXAREACAR 0.154429 LAYER met1 ;
      ANTENNAMAXSIDEAREACAR 0.181682 LAYER met1 ;
    PORT
      LAYER met1 ;
        RECT 2.17 1.42 2.43 2.66 ;
    END
  END B1
  PIN C0
    DIRECTION INPUT ;
    USE SIGNAL ;
    ANTENNAMODEL OXIDE1 ;
      ANTENNAGATEAREA 0.666 LAYER met1 ;
      ANTENNAMAXAREACAR 0.361186 LAYER met1 ;
      ANTENNAMAXSIDEAREACAR 0.373874 LAYER met1 ;
    PORT
      LAYER met1 ;
        RECT 4.47 1.425 4.73 2.665 ;
    END
  END C0
  PIN VDD
    DIRECTION INPUT ;
    USE POWER ;
    SHAPE ABUTMENT ;
    NETEXPR "VDD VDD!" ;
    PORT
      LAYER met1 ;
        RECT 0 3.94 5.98 4.34 ;
    END
  END VDD
  PIN VSS
    DIRECTION INPUT ;
    USE GROUND ;
    SHAPE ABUTMENT ;
    NETEXPR "VSS VSS!" ;
    PORT
      LAYER met1 ;
        RECT 0 -0.2 5.98 0.2 ;
    END
  END VSS
  PIN Y
    DIRECTION OUTPUT ;
    USE SIGNAL ;
    ANTENNADIFFAREA 1.2372 LAYER met1 ;
    PORT
      LAYER met1 ;
        RECT 5.05 2.43 5.715 2.69 ;
        RECT 5.39 0.395 5.715 2.69 ;
        RECT 4.62 0.395 5.715 0.655 ;
        RECT 5.05 2.43 5.31 3.08 ;
        RECT 1.435 0.855 4.88 0.995 ;
        RECT 4.62 0.395 4.88 0.995 ;
        RECT 3.675 0.705 3.905 0.995 ;
        RECT 1.435 0.705 1.665 0.995 ;
    END
  END Y
  OBS
    LAYER met1 ;
      RECT 5.455 3.21 5.745 3.44 ;
      RECT 4.595 3.21 4.885 3.44 ;
      RECT 3.125 3.21 3.415 3.44 ;
      RECT 2.265 3.21 2.555 3.44 ;
      RECT 2.265 3.24 5.745 3.41 ;
      RECT 4.075 0.365 4.365 0.595 ;
      RECT 3.215 0.365 3.505 0.595 ;
      RECT 2.355 0.365 2.645 0.595 ;
      RECT 2.355 0.395 4.365 0.565 ;
      RECT 3.555 2.85 3.845 3.08 ;
      RECT 2.695 2.85 2.985 3.08 ;
      RECT 1.835 2.85 2.125 3.08 ;
      RECT 0.975 2.85 1.265 3.08 ;
      RECT 0.115 2.85 0.405 3.08 ;
      RECT 0.115 2.88 3.845 3.05 ;
      RECT 1.835 0.365 2.125 0.595 ;
      RECT 0.975 0.365 1.265 0.595 ;
      RECT 0.115 0.365 0.405 0.595 ;
      RECT 0.115 0.395 2.125 0.565 ;
  END
  PROPERTY CatenaDesignType "deviceLevel" ;
END AOI221X2_HS

MACRO AOI222X1_HS
  CLASS CORE ;
  ORIGIN 0 0 ;
  FOREIGN AOI222X1_HS 0 0 ;
  SIZE 4.14 BY 4.14 ;
  SYMMETRY X Y ;
  SITE CoreSite ;
  PIN A0
    DIRECTION INPUT ;
    USE SIGNAL ;
    ANTENNAMODEL OXIDE1 ;
      ANTENNAGATEAREA 0.333 LAYER met1 ;
      ANTENNAMAXAREACAR 0.321622 LAYER met1 ;
      ANTENNAMAXSIDEAREACAR 0.378378 LAYER met1 ;
    PORT
      LAYER met1 ;
        RECT 0.33 1.05 0.59 2.29 ;
    END
  END A0
  PIN A1
    DIRECTION INPUT ;
    USE SIGNAL ;
    ANTENNAMODEL OXIDE1 ;
      ANTENNAGATEAREA 0.333 LAYER met1 ;
      ANTENNAMAXAREACAR 0.321622 LAYER met1 ;
      ANTENNAMAXSIDEAREACAR 0.378378 LAYER met1 ;
    PORT
      LAYER met1 ;
        RECT 0.79 1.495 1.05 2.735 ;
    END
  END A1
  PIN B0
    DIRECTION INPUT ;
    USE SIGNAL ;
    ANTENNAMODEL OXIDE1 ;
      ANTENNAGATEAREA 0.333 LAYER met1 ;
      ANTENNAMAXAREACAR 0.410961 LAYER met1 ;
      ANTENNAMAXSIDEAREACAR 0.483483 LAYER met1 ;
    PORT
      LAYER met1 ;
        RECT 1.71 1.49 1.97 2.73 ;
    END
  END B0
  PIN B1
    DIRECTION INPUT ;
    USE SIGNAL ;
    ANTENNAMODEL OXIDE1 ;
      ANTENNAGATEAREA 0.333 LAYER met1 ;
      ANTENNAMAXAREACAR 0.321622 LAYER met1 ;
      ANTENNAMAXSIDEAREACAR 0.378378 LAYER met1 ;
    PORT
      LAYER met1 ;
        RECT 1.25 1.1 1.51 2.34 ;
    END
  END B1
  PIN C0
    DIRECTION INPUT ;
    USE SIGNAL ;
    ANTENNAMODEL OXIDE1 ;
      ANTENNAGATEAREA 0.333 LAYER met1 ;
      ANTENNAMAXAREACAR 0.446697 LAYER met1 ;
      ANTENNAMAXSIDEAREACAR 0.525526 LAYER met1 ;
    PORT
      LAYER met1 ;
        RECT 2.17 1.33 2.43 2.57 ;
        RECT 2.185 1.285 2.415 2.57 ;
    END
  END C0
  PIN C1
    DIRECTION INPUT ;
    USE SIGNAL ;
    ANTENNAMODEL OXIDE1 ;
      ANTENNAGATEAREA 0.333 LAYER met1 ;
      ANTENNAMAXAREACAR 0.507958 LAYER met1 ;
      ANTENNAMAXSIDEAREACAR 0.597598 LAYER met1 ;
    PORT
      LAYER met1 ;
        RECT 3.55 1.765 3.81 3.005 ;
    END
  END C1
  PIN VDD
    DIRECTION INPUT ;
    USE POWER ;
    SHAPE ABUTMENT ;
    NETEXPR "VDD VDD!" ;
    PORT
      LAYER met1 ;
        RECT 0 3.94 4.14 4.34 ;
    END
  END VDD
  PIN VSS
    DIRECTION INPUT ;
    USE GROUND ;
    SHAPE ABUTMENT ;
    NETEXPR "VSS VSS!" ;
    PORT
      LAYER met1 ;
        RECT 0 -0.2 4.14 0.2 ;
    END
  END VSS
  PIN Y
    DIRECTION OUTPUT ;
    USE SIGNAL ;
    ANTENNADIFFAREA 0.823 LAYER met1 ;
    PORT
      LAYER met1 ;
        RECT 3.245 0.485 3.475 1.135 ;
        RECT 0.975 0.68 3.475 0.91 ;
        RECT 2.63 0.68 3.045 3.09 ;
    END
  END Y
  OBS
    LAYER met1 ;
      RECT 1.405 3.27 3.505 3.5 ;
      RECT 0.115 2.9 2.125 3.13 ;
  END
  PROPERTY CatenaDesignType "deviceLevel" ;
END AOI222X1_HS

MACRO AOI222X2_HS
  CLASS CORE ;
  ORIGIN 0 0 ;
  FOREIGN AOI222X2_HS 0 0 ;
  SIZE 6.9 BY 4.14 ;
  SYMMETRY X Y ;
  SITE CoreSite ;
  PIN A0
    DIRECTION INPUT ;
    USE SIGNAL ;
    ANTENNAMODEL OXIDE1 ;
      ANTENNAGATEAREA 0.666 LAYER met1 ;
      ANTENNAMAXAREACAR 0.28461 LAYER met1 ;
      ANTENNAMAXSIDEAREACAR 0.283784 LAYER met1 ;
    PORT
      LAYER met1 ;
        RECT 0.33 1.24 0.59 2.48 ;
    END
  END A0
  PIN A1
    DIRECTION INPUT ;
    USE SIGNAL ;
    ANTENNAMODEL OXIDE1 ;
      ANTENNAGATEAREA 0.666 LAYER met1 ;
      ANTENNAMAXAREACAR 0.280781 LAYER met1 ;
      ANTENNAMAXSIDEAREACAR 0.279279 LAYER met1 ;
    PORT
      LAYER met1 ;
        RECT 1.25 1.42 1.51 2.66 ;
        RECT 1.265 1.285 1.495 2.66 ;
    END
  END A1
  PIN B0
    DIRECTION INPUT ;
    USE SIGNAL ;
    ANTENNAMODEL OXIDE1 ;
      ANTENNAGATEAREA 0.666 LAYER met1 ;
      ANTENNAMAXAREACAR 0.280781 LAYER met1 ;
      ANTENNAMAXSIDEAREACAR 0.279279 LAYER met1 ;
    PORT
      LAYER met1 ;
        RECT 2.63 1.46 2.89 2.7 ;
    END
  END B0
  PIN B1
    DIRECTION INPUT ;
    USE SIGNAL ;
    ANTENNAMODEL OXIDE1 ;
      ANTENNAGATEAREA 0.666 LAYER met1 ;
      ANTENNAMAXAREACAR 0.280781 LAYER met1 ;
      ANTENNAMAXSIDEAREACAR 0.279279 LAYER met1 ;
    PORT
      LAYER met1 ;
        RECT 3.55 1.43 3.81 2.67 ;
        RECT 3.565 1.285 3.795 2.67 ;
    END
  END B1
  PIN C0
    DIRECTION INPUT ;
    USE SIGNAL ;
    ANTENNAMODEL OXIDE1 ;
      ANTENNAGATEAREA 0.666 LAYER met1 ;
      ANTENNAMAXAREACAR 0.280781 LAYER met1 ;
      ANTENNAMAXSIDEAREACAR 0.279279 LAYER met1 ;
    PORT
      LAYER met1 ;
        RECT 4.93 1.445 5.19 2.685 ;
    END
  END C0
  PIN C1
    DIRECTION INPUT ;
    USE SIGNAL ;
    ANTENNAMODEL OXIDE1 ;
      ANTENNAGATEAREA 0.666 LAYER met1 ;
      ANTENNAMAXAREACAR 0.330556 LAYER met1 ;
      ANTENNAMAXSIDEAREACAR 0.337838 LAYER met1 ;
    PORT
      LAYER met1 ;
        RECT 6.31 1.305 6.57 2.545 ;
        RECT 6.325 1.285 6.555 2.545 ;
    END
  END C1
  PIN VDD
    DIRECTION INPUT ;
    USE POWER ;
    SHAPE ABUTMENT ;
    NETEXPR "VDD VDD!" ;
    PORT
      LAYER met1 ;
        RECT 0 3.94 6.9 4.34 ;
    END
  END VDD
  PIN VSS
    DIRECTION INPUT ;
    USE GROUND ;
    SHAPE ABUTMENT ;
    NETEXPR "VSS VSS!" ;
    PORT
      LAYER met1 ;
        RECT 0 -0.2 6.9 0.2 ;
    END
  END VSS
  PIN Y
    DIRECTION OUTPUT ;
    USE SIGNAL ;
    ANTENNADIFFAREA 1.456 LAYER met1 ;
    PORT
      LAYER met1 ;
        RECT 5.915 0.845 6.145 3.235 ;
        RECT 5.055 2.945 6.145 3.085 ;
        RECT 5.85 0.905 6.145 3.085 ;
        RECT 1.435 0.905 6.145 1.075 ;
        RECT 5.055 2.945 5.285 3.235 ;
        RECT 3.675 0.725 3.905 1.075 ;
        RECT 1.435 0.725 1.665 1.075 ;
    END
  END Y
  OBS
    LAYER met1 ;
      RECT 6.345 0.415 6.575 0.705 ;
      RECT 5.485 0.415 5.715 0.705 ;
      RECT 4.625 0.415 4.855 0.705 ;
      RECT 4.625 0.415 6.575 0.555 ;
      RECT 2.815 3.405 6.575 3.545 ;
      RECT 6.345 3.255 6.575 3.545 ;
      RECT 5.485 3.255 5.715 3.545 ;
      RECT 4.625 3.255 4.855 3.545 ;
      RECT 3.675 3.255 3.905 3.545 ;
      RECT 2.815 3.255 3.045 3.545 ;
      RECT 4.105 0.415 4.335 0.705 ;
      RECT 3.245 0.415 3.475 0.705 ;
      RECT 2.385 0.415 2.615 0.705 ;
      RECT 2.385 0.415 4.335 0.555 ;
      RECT 4.105 2.945 4.335 3.235 ;
      RECT 3.245 2.945 3.475 3.235 ;
      RECT 2.385 2.945 2.615 3.235 ;
      RECT 1.865 2.945 2.095 3.235 ;
      RECT 1.005 2.945 1.235 3.235 ;
      RECT 0.145 2.945 0.375 3.235 ;
      RECT 0.145 2.945 4.335 3.085 ;
      RECT 1.865 0.415 2.095 0.705 ;
      RECT 1.005 0.415 1.235 0.705 ;
      RECT 0.145 0.415 0.375 0.705 ;
      RECT 0.145 0.415 2.095 0.555 ;
  END
  PROPERTY CatenaDesignType "deviceLevel" ;
END AOI222X2_HS

MACRO AOI22X1_HS
  CLASS CORE ;
  ORIGIN 0 0 ;
  FOREIGN AOI22X1_HS 0 0 ;
  SIZE 2.76 BY 4.14 ;
  SYMMETRY X Y ;
  SITE CoreSite ;
  PIN A0
    DIRECTION INPUT ;
    USE SIGNAL ;
    ANTENNAMODEL OXIDE1 ;
      ANTENNAGATEAREA 0.333 LAYER met1 ;
      ANTENNAMAXAREACAR 0.3497 LAYER met1 ;
      ANTENNAMAXSIDEAREACAR 0.411411 LAYER met1 ;
    PORT
      LAYER met1 ;
        RECT 0.33 0.83 0.59 2.07 ;
    END
  END A0
  PIN A1
    DIRECTION INPUT ;
    USE SIGNAL ;
    ANTENNAMODEL OXIDE1 ;
      ANTENNAGATEAREA 0.333 LAYER met1 ;
      ANTENNAMAXAREACAR 0.38033 LAYER met1 ;
      ANTENNAMAXSIDEAREACAR 0.447447 LAYER met1 ;
    PORT
      LAYER met1 ;
        RECT 0.79 1.24 1.05 2.48 ;
    END
  END A1
  PIN B0
    DIRECTION INPUT ;
    USE SIGNAL ;
    ANTENNAMODEL OXIDE1 ;
      ANTENNAGATEAREA 0.333 LAYER met1 ;
      ANTENNAMAXAREACAR 0.515616 LAYER met1 ;
      ANTENNAMAXSIDEAREACAR 0.606607 LAYER met1 ;
    PORT
      LAYER met1 ;
        RECT 2.17 1.195 2.43 2.435 ;
    END
  END B0
  PIN B1
    DIRECTION INPUT ;
    USE SIGNAL ;
    ANTENNAMODEL OXIDE1 ;
      ANTENNAGATEAREA 0.333 LAYER met1 ;
      ANTENNAMAXAREACAR 0.367568 LAYER met1 ;
      ANTENNAMAXSIDEAREACAR 0.432432 LAYER met1 ;
    PORT
      LAYER met1 ;
        RECT 1.25 1.205 1.51 2.445 ;
    END
  END B1
  PIN VDD
    DIRECTION INPUT ;
    USE POWER ;
    SHAPE ABUTMENT ;
    NETEXPR "VDD VDD!" ;
    PORT
      LAYER met1 ;
        RECT 0 3.94 2.76 4.34 ;
    END
  END VDD
  PIN VSS
    DIRECTION INPUT ;
    USE GROUND ;
    SHAPE ABUTMENT ;
    NETEXPR "VSS VSS!" ;
    PORT
      LAYER met1 ;
        RECT 0 -0.2 2.76 0.2 ;
    END
  END VSS
  PIN Y
    DIRECTION OUTPUT ;
    USE SIGNAL ;
    ANTENNADIFFAREA 0.6216 LAYER met1 ;
    PORT
      LAYER met1 ;
        RECT 1.435 2.82 1.97 3.11 ;
        RECT 1.71 0.82 1.97 3.11 ;
        RECT 1.12 0.82 1.97 1.05 ;
        RECT 0.975 0.625 1.265 0.855 ;
    END
  END Y
  OBS
    LAYER met1 ;
      RECT 0.145 3.3 2.125 3.53 ;
      RECT 1.005 2.88 1.235 3.53 ;
      RECT 0.145 2.88 0.375 3.53 ;
  END
  PROPERTY CatenaDesignType "deviceLevel" ;
END AOI22X1_HS

MACRO AOI22X2_HS
  CLASS CORE ;
  ORIGIN 0 0 ;
  FOREIGN AOI22X2_HS 0 0 ;
  SIZE 4.6 BY 4.14 ;
  SYMMETRY X Y ;
  SITE CoreSite ;
  PIN A0
    DIRECTION INPUT ;
    USE SIGNAL ;
    ANTENNAMODEL OXIDE1 ;
      ANTENNAGATEAREA 0.666 LAYER met1 ;
      ANTENNAMAXAREACAR 0.32545 LAYER met1 ;
      ANTENNAMAXSIDEAREACAR 0.331832 LAYER met1 ;
    PORT
      LAYER met1 ;
        RECT 0.33 1.52 0.59 2.76 ;
    END
  END A0
  PIN A1
    DIRECTION INPUT ;
    USE SIGNAL ;
    ANTENNAMODEL OXIDE1 ;
      ANTENNAGATEAREA 0.666 LAYER met1 ;
      ANTENNAMAXAREACAR 0.32545 LAYER met1 ;
      ANTENNAMAXSIDEAREACAR 0.331832 LAYER met1 ;
    PORT
      LAYER met1 ;
        RECT 1.25 1.39 1.51 2.63 ;
        RECT 1.265 1.285 1.495 2.63 ;
    END
  END A1
  PIN B0
    DIRECTION INPUT ;
    USE SIGNAL ;
    ANTENNAMODEL OXIDE1 ;
      ANTENNAGATEAREA 0.666 LAYER met1 ;
      ANTENNAMAXAREACAR 0.32545 LAYER met1 ;
      ANTENNAMAXSIDEAREACAR 0.331832 LAYER met1 ;
    PORT
      LAYER met1 ;
        RECT 3.55 1.355 3.81 2.595 ;
        RECT 3.565 1.285 3.795 2.595 ;
    END
  END B0
  PIN B1
    DIRECTION INPUT ;
    USE SIGNAL ;
    ANTENNAMODEL OXIDE1 ;
      ANTENNAGATEAREA 0.666 LAYER met1 ;
      ANTENNAMAXAREACAR 0.32545 LAYER met1 ;
      ANTENNAMAXSIDEAREACAR 0.331832 LAYER met1 ;
    PORT
      LAYER met1 ;
        RECT 2.63 1.52 2.89 2.76 ;
    END
  END B1
  PIN VDD
    DIRECTION INPUT ;
    USE POWER ;
    SHAPE ABUTMENT ;
    NETEXPR "VDD VDD!" ;
    PORT
      LAYER met1 ;
        RECT 0 3.94 4.6 4.34 ;
    END
  END VDD
  PIN VSS
    DIRECTION INPUT ;
    USE GROUND ;
    SHAPE ABUTMENT ;
    NETEXPR "VSS VSS!" ;
    PORT
      LAYER met1 ;
        RECT 0 -0.2 4.6 0.2 ;
    END
  END VSS
  PIN Y
    DIRECTION OUTPUT ;
    USE SIGNAL ;
    ANTENNADIFFAREA 1.2432 LAYER met1 ;
    PORT
      LAYER met1 ;
        RECT 2.815 2.95 4.27 3.09 ;
        RECT 4.01 0.85 4.27 3.09 ;
        RECT 1.435 0.855 4.27 0.995 ;
        RECT 3.675 2.95 3.905 3.24 ;
        RECT 2.815 2.95 3.045 3.24 ;
        RECT 2.815 0.705 3.045 0.995 ;
        RECT 1.435 0.705 1.665 0.995 ;
    END
  END Y
  OBS
    LAYER met1 ;
      RECT 4.075 0.395 4.335 0.685 ;
      RECT 3.215 0.395 3.505 0.655 ;
      RECT 2.355 0.395 2.645 0.655 ;
      RECT 2.355 0.395 4.335 0.565 ;
      RECT 4.075 3.32 4.335 3.61 ;
      RECT 3.215 3.32 3.475 3.61 ;
      RECT 2.355 3.32 2.615 3.61 ;
      RECT 1.835 3.32 2.095 3.61 ;
      RECT 0.975 3.32 1.235 3.61 ;
      RECT 0.115 3.32 0.375 3.61 ;
      RECT 0.115 3.38 4.335 3.55 ;
      RECT 0.975 0.395 1.235 0.685 ;
      RECT 0.115 0.395 0.375 0.685 ;
      RECT 1.835 0.395 2.125 0.625 ;
      RECT 0.115 0.395 2.125 0.565 ;
  END
  PROPERTY CatenaDesignType "deviceLevel" ;
END AOI22X2_HS

MACRO BUFX16_HS
  CLASS CORE ;
  ORIGIN 0 0 ;
  FOREIGN BUFX16_HS 0 0 ;
  SIZE 9.2 BY 4.14 ;
  SYMMETRY X Y ;
  SITE CoreSite ;
  PIN A
    DIRECTION INPUT ;
    USE SIGNAL ;
    ANTENNAMODEL OXIDE1 ;
      ANTENNAGATEAREA 1.332 LAYER met1 ;
      ANTENNAMAXAREACAR 0.216967 LAYER met1 ;
      ANTENNAMAXSIDEAREACAR 0.204204 LAYER met1 ;
    PORT
      LAYER met1 ;
        RECT 0.79 1.435 1.05 2.675 ;
        RECT 0.805 1.285 1.035 2.675 ;
    END
  END A
  PIN VDD
    DIRECTION INPUT ;
    USE POWER ;
    SHAPE ABUTMENT ;
    NETEXPR "VDD VDD!" ;
    PORT
      LAYER met1 ;
        RECT 0 3.94 9.2 4.34 ;
    END
  END VDD
  PIN VSS
    DIRECTION INPUT ;
    USE GROUND ;
    SHAPE ABUTMENT ;
    NETEXPR "VSS VSS!" ;
    PORT
      LAYER met1 ;
        RECT 0 -0.2 9.2 0.2 ;
    END
  END VSS
  PIN Y
    DIRECTION OUTPUT ;
    USE SIGNAL ;
    ANTENNADIFFAREA 4.9728 LAYER met1 ;
    PORT
      LAYER met1 ;
        RECT 8.15 2.48 8.545 3.49 ;
        RECT 2.295 2.105 8.545 2.335 ;
        RECT 8.15 0.45 8.545 1.1 ;
        RECT 8.15 0.45 8.41 3.49 ;
        RECT 7.455 0.45 7.685 3.49 ;
        RECT 6.595 0.45 6.825 3.49 ;
        RECT 5.735 0.45 5.965 3.49 ;
        RECT 4.875 0.45 5.105 3.49 ;
        RECT 4.015 0.45 4.245 3.49 ;
        RECT 3.155 0.45 3.385 3.49 ;
        RECT 2.295 0.45 2.525 3.49 ;
    END
  END Y
  OBS
    LAYER met1 ;
      RECT 0.42 3.2 0.805 3.49 ;
      RECT 0.42 0.45 0.65 3.49 ;
      RECT 0.42 0.45 0.805 1.1 ;
      RECT 1.435 0.45 1.665 3.49 ;
  END
  PROPERTY CatenaDesignType "deviceLevel" ;
END BUFX16_HS

MACRO BUFX2_HS
  CLASS CORE ;
  ORIGIN 0 0 ;
  FOREIGN BUFX2_HS 0 0 ;
  SIZE 2.3 BY 4.14 ;
  SYMMETRY X Y ;
  SITE CoreSite ;
  PIN A
    DIRECTION INPUT ;
    USE SIGNAL ;
    ANTENNAMODEL OXIDE1 ;
      ANTENNAGATEAREA 0.18075 LAYER met1 ;
      ANTENNAMAXAREACAR 0.827663 LAYER met1 ;
      ANTENNAMAXSIDEAREACAR 0.973721 LAYER met1 ;
    PORT
      LAYER met1 ;
        RECT 0.79 1.685 1.05 2.925 ;
    END
  END A
  PIN VDD
    DIRECTION INPUT ;
    USE POWER ;
    SHAPE ABUTMENT ;
    NETEXPR "VDD VDD!" ;
    PORT
      LAYER met1 ;
        RECT 0 3.94 2.3 4.34 ;
    END
  END VDD
  PIN VSS
    DIRECTION INPUT ;
    USE GROUND ;
    SHAPE ABUTMENT ;
    NETEXPR "VSS VSS!" ;
    PORT
      LAYER met1 ;
        RECT 0 -0.2 2.3 0.2 ;
    END
  END VSS
  PIN Y
    DIRECTION OUTPUT ;
    USE SIGNAL ;
    ANTENNADIFFAREA 0.6216 LAYER met1 ;
    PORT
      LAYER met1 ;
        RECT 1.065 3.23 1.51 3.52 ;
        RECT 1.25 0.415 1.51 3.52 ;
        RECT 1.065 0.415 1.51 1.065 ;
    END
  END Y
  OBS
    LAYER met1 ;
      RECT 0.145 3.24 0.375 3.53 ;
      RECT 0.145 0.46 0.285 3.53 ;
      RECT 0.145 1.285 0.515 1.575 ;
      RECT 0.145 0.46 0.375 0.75 ;
  END
  PROPERTY CatenaDesignType "deviceLevel" ;
END BUFX2_HS

MACRO BUFX4_HS
  CLASS CORE ;
  ORIGIN 0 0 ;
  FOREIGN BUFX4_HS 0 0 ;
  SIZE 2.76 BY 4.14 ;
  SYMMETRY X Y ;
  SITE CoreSite ;
  PIN A
    DIRECTION INPUT ;
    USE SIGNAL ;
    ANTENNAMODEL OXIDE1 ;
      ANTENNAGATEAREA 0.333 LAYER met1 ;
      ANTENNAMAXAREACAR 0.523273 LAYER met1 ;
      ANTENNAMAXSIDEAREACAR 0.615616 LAYER met1 ;
    PORT
      LAYER met1 ;
        RECT 0.79 1.165 1.05 2.405 ;
    END
  END A
  PIN VDD
    DIRECTION INPUT ;
    USE POWER ;
    SHAPE ABUTMENT ;
    NETEXPR "VDD VDD!" ;
    PORT
      LAYER met1 ;
        RECT 0 3.94 2.76 4.34 ;
    END
  END VDD
  PIN VSS
    DIRECTION INPUT ;
    USE GROUND ;
    SHAPE ABUTMENT ;
    NETEXPR "VSS VSS!" ;
    PORT
      LAYER met1 ;
        RECT 0 -0.2 2.76 0.2 ;
    END
  END VSS
  PIN Y
    DIRECTION OUTPUT ;
    USE SIGNAL ;
    ANTENNADIFFAREA 1.2432 LAYER met1 ;
    PORT
      LAYER met1 ;
        RECT 1.71 0.42 2.125 1.065 ;
        RECT 1.005 3.24 2.095 3.53 ;
        RECT 1.71 2.88 2.095 3.53 ;
        RECT 1.865 0.415 2.095 1.065 ;
        RECT 1.71 0.42 1.97 3.53 ;
        RECT 1.005 0.42 2.125 0.71 ;
    END
  END Y
  OBS
    LAYER met1 ;
      RECT 0.145 0.845 0.375 2.73 ;
  END
  PROPERTY CatenaDesignType "deviceLevel" ;
END BUFX4_HS

MACRO BUFX8_HS
  CLASS CORE ;
  ORIGIN 0 0 ;
  FOREIGN BUFX8_HS 0 0 ;
  SIZE 5.06 BY 4.14 ;
  SYMMETRY X Y ;
  SITE CoreSite ;
  PIN A
    DIRECTION INPUT ;
    USE SIGNAL ;
    ANTENNAMODEL OXIDE1 ;
      ANTENNAGATEAREA 0.666 LAYER met1 ;
      ANTENNAMAXAREACAR 0.307583 LAYER met1 ;
      ANTENNAMAXSIDEAREACAR 0.310811 LAYER met1 ;
    PORT
      LAYER met1 ;
        RECT 0.33 1.355 0.59 2.595 ;
    END
  END A
  PIN VDD
    DIRECTION INPUT ;
    USE POWER ;
    SHAPE ABUTMENT ;
    NETEXPR "VDD VDD!" ;
    PORT
      LAYER met1 ;
        RECT 0 3.94 5.06 4.34 ;
    END
  END VDD
  PIN VSS
    DIRECTION INPUT ;
    USE GROUND ;
    SHAPE ABUTMENT ;
    NETEXPR "VSS VSS!" ;
    PORT
      LAYER met1 ;
        RECT 0 -0.2 5.06 0.2 ;
    END
  END VSS
  PIN Y
    DIRECTION OUTPUT ;
    USE SIGNAL ;
    ANTENNADIFFAREA 2.4864 LAYER met1 ;
    PORT
      LAYER met1 ;
        RECT 1.435 3.22 4.27 3.51 ;
        RECT 4.01 0.43 4.27 3.51 ;
        RECT 3.155 0.43 3.385 3.51 ;
        RECT 2.295 0.43 2.525 3.51 ;
        RECT 1.435 0.435 1.665 3.51 ;
    END
  END Y
  OBS
    LAYER met1 ;
      RECT 0.575 2.88 0.805 3.53 ;
      RECT 0.575 2.88 1.26 3.11 ;
      RECT 1.03 0.61 1.26 3.11 ;
      RECT 0.575 0.61 1.26 0.9 ;
      RECT 0.575 0.415 0.805 0.9 ;
  END
  PROPERTY CatenaDesignType "deviceLevel" ;
END BUFX8_HS

MACRO CLKAND2X2_HS
  CLASS CORE ;
  ORIGIN 0 0 ;
  FOREIGN CLKAND2X2_HS 0 0 ;
  SIZE 4.14 BY 4.14 ;
  SYMMETRY X Y ;
  SITE CoreSite ;
  PIN A
    DIRECTION INPUT ;
    USE SIGNAL ;
    ANTENNAMODEL OXIDE1 ;
      ANTENNAGATEAREA 0.18075 LAYER met1 ;
      ANTENNAMAXAREACAR 0.935823 LAYER met1 ;
      ANTENNAMAXSIDEAREACAR 1.100968 LAYER met1 ;
    PORT
      LAYER met1 ;
        RECT 1.25 1.34 1.51 2.58 ;
    END
  END A
  PIN B
    DIRECTION INPUT ;
    USE SIGNAL ;
    ANTENNAMODEL OXIDE1 ;
      ANTENNAGATEAREA 0.18075 LAYER met1 ;
      ANTENNAMAXAREACAR 0.672476 LAYER met1 ;
      ANTENNAMAXSIDEAREACAR 0.791148 LAYER met1 ;
    PORT
      LAYER met1 ;
        RECT 0.33 1.55 0.59 2.79 ;
        RECT 0.285 2.31 0.59 2.6 ;
    END
  END B
  PIN VDD
    DIRECTION INPUT ;
    USE POWER ;
    SHAPE ABUTMENT ;
    NETEXPR "VDD VDD!" ;
    PORT
      LAYER met1 ;
        RECT 0 3.94 4.14 4.34 ;
    END
  END VDD
  PIN VSS
    DIRECTION INPUT ;
    USE GROUND ;
    SHAPE ABUTMENT ;
    NETEXPR "VSS VSS!" ;
    PORT
      LAYER met1 ;
        RECT 0 -0.2 4.14 0.2 ;
    END
  END VSS
  PIN Y
    DIRECTION OUTPUT ;
    USE SIGNAL ;
    ANTENNADIFFAREA 1.4392 LAYER met1 ;
    PORT
      LAYER met1 ;
        RECT 1.495 3.21 3.46 3.47 ;
        RECT 3.2 3.18 3.46 3.47 ;
        RECT 2.355 3.18 2.585 3.47 ;
        RECT 1.495 3.18 1.97 3.47 ;
        RECT 1.71 0.46 1.97 3.47 ;
        RECT 1.495 0.46 1.97 0.75 ;
    END
  END Y
  OBS
    LAYER met1 ;
      RECT 0.575 3.24 1.02 3.53 ;
      RECT 0.79 0.685 1.02 3.53 ;
      RECT 0.145 0.46 0.375 0.75 ;
      RECT 0.145 0.49 1.015 0.72 ;
  END
  PROPERTY CatenaDesignType "deviceLevel" ;
END CLKAND2X2_HS

MACRO CLKBUFX2_HS
  CLASS CORE ;
  ORIGIN 0 0 ;
  FOREIGN CLKBUFX2_HS 0 0 ;
  SIZE 2.76 BY 4.14 ;
  SYMMETRY X Y ;
  SITE CoreSite ;
  PIN A
    DIRECTION INPUT ;
    USE SIGNAL ;
    ANTENNAMODEL OXIDE1 ;
      ANTENNAGATEAREA 0.273 LAYER met1 ;
      ANTENNAMAXAREACAR 0.638278 LAYER met1 ;
      ANTENNAMAXSIDEAREACAR 0.750916 LAYER met1 ;
    PORT
      LAYER met1 ;
        RECT 0.79 1.165 1.05 2.405 ;
    END
  END A
  PIN VDD
    DIRECTION INPUT ;
    USE POWER ;
    SHAPE ABUTMENT ;
    NETEXPR "VDD VDD!" ;
    PORT
      LAYER met1 ;
        RECT 0 3.94 2.76 4.34 ;
    END
  END VDD
  PIN VSS
    DIRECTION INPUT ;
    USE GROUND ;
    SHAPE ABUTMENT ;
    NETEXPR "VSS VSS!" ;
    PORT
      LAYER met1 ;
        RECT 0 -0.2 2.76 0.2 ;
    END
  END VSS
  PIN Y
    DIRECTION OUTPUT ;
    USE SIGNAL ;
    ANTENNADIFFAREA 0.8064 LAYER met1 ;
    PORT
      LAYER met1 ;
        RECT 1.71 0.42 2.125 1.065 ;
        RECT 1.005 3.24 2.095 3.53 ;
        RECT 1.71 2.88 2.095 3.53 ;
        RECT 1.71 0.42 1.97 3.53 ;
        RECT 1.005 0.42 2.125 0.71 ;
    END
  END Y
  OBS
    LAYER met1 ;
      RECT 0.145 0.845 0.375 2.73 ;
  END
  PROPERTY CatenaDesignType "deviceLevel" ;
END CLKBUFX2_HS

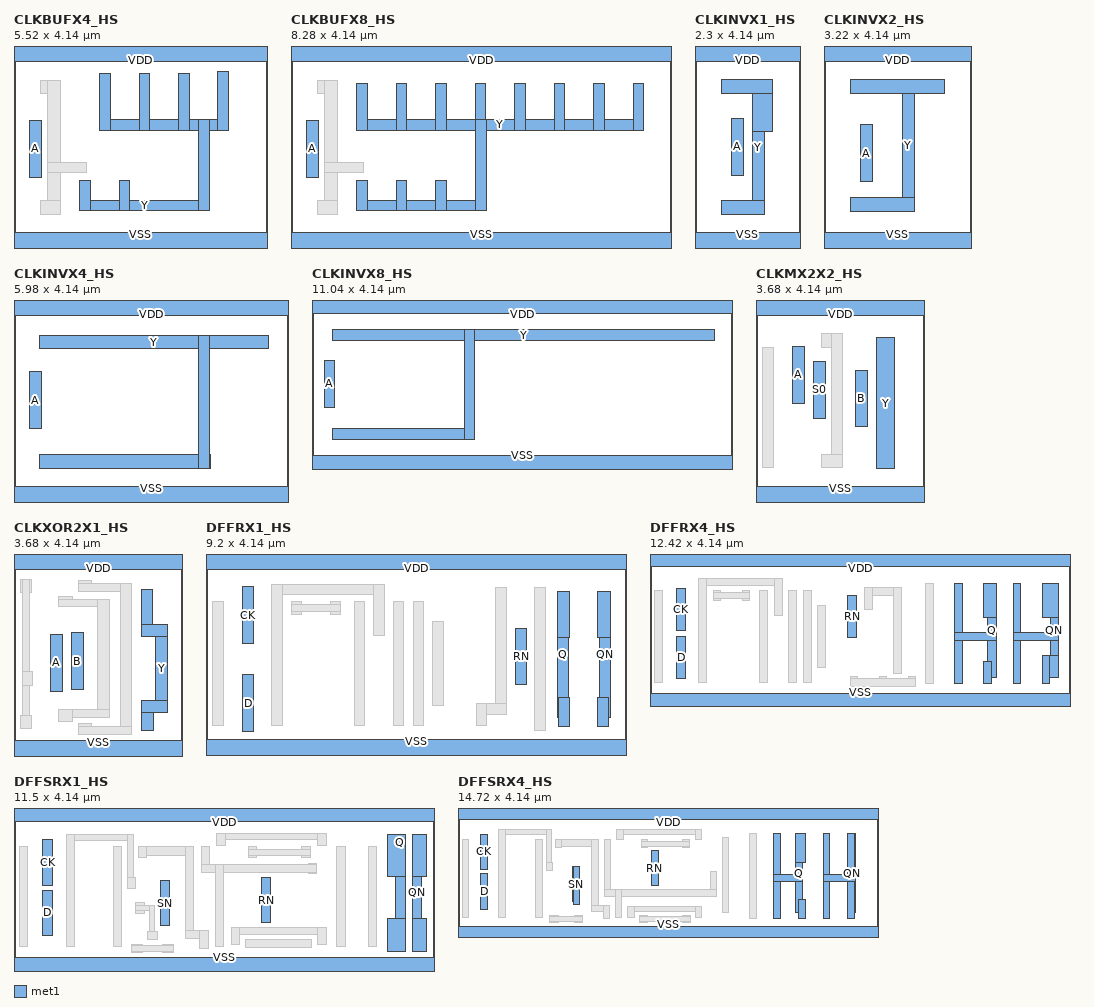
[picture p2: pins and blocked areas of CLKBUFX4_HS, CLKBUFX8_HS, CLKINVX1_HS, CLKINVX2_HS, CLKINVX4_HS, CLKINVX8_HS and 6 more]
MACRO CLKBUFX4_HS
  CLASS CORE ;
  ORIGIN 0 0 ;
  FOREIGN CLKBUFX4_HS 0 0 ;
  SIZE 5.52 BY 4.14 ;
  SYMMETRY X Y ;
  SITE CoreSite ;
  PIN A
    DIRECTION INPUT ;
    USE SIGNAL ;
    ANTENNAMODEL OXIDE1 ;
      ANTENNAGATEAREA 0.333 LAYER met1 ;
      ANTENNAMAXAREACAR 0.574324 LAYER met1 ;
      ANTENNAMAXSIDEAREACAR 0.573574 LAYER met1 ;
    PORT
      LAYER met1 ;
        RECT 0.33 1.415 0.59 2.655 ;
    END
  END A
  PIN VDD
    DIRECTION INPUT ;
    USE POWER ;
    SHAPE ABUTMENT ;
    NETEXPR "VDD VDD!" ;
    PORT
      LAYER met1 ;
        RECT 0 3.94 5.52 4.34 ;
    END
  END VDD
  PIN VSS
    DIRECTION INPUT ;
    USE GROUND ;
    SHAPE ABUTMENT ;
    NETEXPR "VSS VSS!" ;
    PORT
      LAYER met1 ;
        RECT 0 -0.2 5.52 0.2 ;
    END
  END VSS
  PIN Y
    DIRECTION OUTPUT ;
    USE SIGNAL ;
    ANTENNADIFFAREA 1.6128 LAYER met1 ;
    PORT
      LAYER met1 ;
        RECT 4.445 2.44 4.675 3.725 ;
        RECT 1.865 2.44 4.675 2.67 ;
        RECT 4.01 0.68 4.27 2.67 ;
        RECT 1.435 0.68 4.27 0.91 ;
        RECT 3.585 2.44 3.815 3.68 ;
        RECT 2.725 2.44 2.955 3.68 ;
        RECT 2.295 0.68 2.525 1.33 ;
        RECT 1.865 2.44 2.095 3.68 ;
        RECT 1.435 0.68 1.665 1.33 ;
    END
  END Y
  OBS
    LAYER met1 ;
      RECT 0.575 3.235 1.02 3.525 ;
      RECT 0.73 0.61 1.02 3.525 ;
      RECT 0.73 1.51 1.57 1.74 ;
      RECT 0.575 0.61 1.02 0.9 ;
  END
  PROPERTY CatenaDesignType "deviceLevel" ;
END CLKBUFX4_HS

MACRO CLKBUFX8_HS
  CLASS CORE ;
  ORIGIN 0 0 ;
  FOREIGN CLKBUFX8_HS 0 0 ;
  SIZE 8.28 BY 4.14 ;
  SYMMETRY X Y ;
  SITE CoreSite ;
  PIN A
    DIRECTION INPUT ;
    USE SIGNAL ;
    ANTENNAMODEL OXIDE1 ;
      ANTENNAGATEAREA 0.546 LAYER met1 ;
      ANTENNAMAXAREACAR 0.350275 LAYER met1 ;
      ANTENNAMAXSIDEAREACAR 0.349817 LAYER met1 ;
    PORT
      LAYER met1 ;
        RECT 0.33 1.415 0.59 2.655 ;
    END
  END A
  PIN VDD
    DIRECTION INPUT ;
    USE POWER ;
    SHAPE ABUTMENT ;
    NETEXPR "VDD VDD!" ;
    PORT
      LAYER met1 ;
        RECT 0 3.94 8.28 4.34 ;
    END
  END VDD
  PIN VSS
    DIRECTION INPUT ;
    USE GROUND ;
    SHAPE ABUTMENT ;
    NETEXPR "VSS VSS!" ;
    PORT
      LAYER met1 ;
        RECT 0 -0.2 8.28 0.2 ;
    END
  END VSS
  PIN Y
    DIRECTION OUTPUT ;
    USE SIGNAL ;
    ANTENNADIFFAREA 3.2256 LAYER met1 ;
    PORT
      LAYER met1 ;
        RECT 7.455 2.44 7.685 3.45 ;
        RECT 1.435 2.44 7.685 2.67 ;
        RECT 6.595 2.44 6.825 3.45 ;
        RECT 5.735 2.44 5.965 3.45 ;
        RECT 4.875 2.44 5.105 3.45 ;
        RECT 4.01 0.68 4.27 2.67 ;
        RECT 4.015 0.68 4.245 3.45 ;
        RECT 1.435 0.68 4.27 0.91 ;
        RECT 3.155 2.44 3.385 3.45 ;
        RECT 3.155 0.68 3.385 1.33 ;
        RECT 2.295 2.44 2.525 3.45 ;
        RECT 2.295 0.68 2.525 1.33 ;
        RECT 1.435 2.44 1.665 3.45 ;
        RECT 1.435 0.68 1.665 1.33 ;
    END
  END Y
  OBS
    LAYER met1 ;
      RECT 0.575 3.235 1.02 3.525 ;
      RECT 0.73 0.61 1.02 3.525 ;
      RECT 0.73 1.51 1.57 1.74 ;
      RECT 0.575 0.61 1.02 0.9 ;
  END
  PROPERTY CatenaDesignType "deviceLevel" ;
END CLKBUFX8_HS

MACRO CLKINVX1_HS
  CLASS CORE ;
  ORIGIN 0 0 ;
  FOREIGN CLKINVX1_HS 0 0 ;
  SIZE 2.3 BY 4.14 ;
  SYMMETRY X Y ;
  SITE CoreSite ;
  PIN A
    DIRECTION INPUT ;
    USE SIGNAL ;
    ANTENNAMODEL OXIDE1 ;
      ANTENNAGATEAREA 0.591 LAYER met1 ;
      ANTENNAMAXAREACAR 0.451607 LAYER met1 ;
      ANTENNAMAXSIDEAREACAR 0.416244 LAYER met1 ;
    PORT
      LAYER met1 ;
        RECT 0.79 1.455 1.05 2.695 ;
    END
  END A
  PIN VDD
    DIRECTION INPUT ;
    USE POWER ;
    SHAPE ABUTMENT ;
    NETEXPR "VDD VDD!" ;
    PORT
      LAYER met1 ;
        RECT 0 3.94 2.3 4.34 ;
    END
  END VDD
  PIN VSS
    DIRECTION INPUT ;
    USE GROUND ;
    SHAPE ABUTMENT ;
    NETEXPR "VSS VSS!" ;
    PORT
      LAYER met1 ;
        RECT 0 -0.2 2.3 0.2 ;
    END
  END VSS
  PIN Y
    DIRECTION OUTPUT ;
    USE SIGNAL ;
    ANTENNADIFFAREA 0.7791 LAYER met1 ;
    PORT
      LAYER met1 ;
        RECT 0.575 3.24 1.695 3.53 ;
        RECT 1.25 2.41 1.695 3.53 ;
        RECT 1.25 0.61 1.51 3.53 ;
        RECT 0.575 0.61 1.51 0.9 ;
    END
  END Y
  PROPERTY CatenaDesignType "deviceLevel" ;
END CLKINVX1_HS

MACRO CLKINVX2_HS
  CLASS CORE ;
  ORIGIN 0 0 ;
  FOREIGN CLKINVX2_HS 0 0 ;
  SIZE 3.22 BY 4.14 ;
  SYMMETRY X Y ;
  SITE CoreSite ;
  PIN A
    DIRECTION INPUT ;
    USE SIGNAL ;
    ANTENNAMODEL OXIDE1 ;
      ANTENNAGATEAREA 1.182 LAYER met1 ;
      ANTENNAMAXAREACAR 0.512014 LAYER met1 ;
      ANTENNAMAXSIDEAREACAR 0.458545 LAYER met1 ;
    PORT
      LAYER met1 ;
        RECT 0.79 1.315 1.05 2.555 ;
    END
  END A
  PIN VDD
    DIRECTION INPUT ;
    USE POWER ;
    SHAPE ABUTMENT ;
    NETEXPR "VDD VDD!" ;
    PORT
      LAYER met1 ;
        RECT 0 3.94 3.22 4.34 ;
    END
  END VDD
  PIN VSS
    DIRECTION INPUT ;
    USE GROUND ;
    SHAPE ABUTMENT ;
    NETEXPR "VSS VSS!" ;
    PORT
      LAYER met1 ;
        RECT 0 -0.2 3.22 0.2 ;
    END
  END VSS
  PIN Y
    DIRECTION OUTPUT ;
    USE SIGNAL ;
    ANTENNADIFFAREA 1.1032 LAYER met1 ;
    PORT
      LAYER met1 ;
        RECT 0.575 3.24 2.615 3.53 ;
        RECT 1.71 0.675 1.97 3.53 ;
        RECT 0.575 0.675 1.97 0.965 ;
    END
  END Y
  PROPERTY CatenaDesignType "deviceLevel" ;
END CLKINVX2_HS

MACRO CLKINVX4_HS
  CLASS CORE ;
  ORIGIN 0 0 ;
  FOREIGN CLKINVX4_HS 0 0 ;
  SIZE 5.98 BY 4.14 ;
  SYMMETRY X Y ;
  SITE CoreSite ;
  PIN A
    DIRECTION INPUT ;
    USE SIGNAL ;
    ANTENNAMODEL OXIDE1 ;
      ANTENNAGATEAREA 2.364 LAYER met1 ;
      ANTENNAMAXAREACAR 0.513092 LAYER met1 ;
      ANTENNAMAXSIDEAREACAR 0.445431 LAYER met1 ;
    PORT
      LAYER met1 ;
        RECT 0.33 1.465 0.59 2.705 ;
    END
  END A
  PIN VDD
    DIRECTION INPUT ;
    USE POWER ;
    SHAPE ABUTMENT ;
    NETEXPR "VDD VDD!" ;
    PORT
      LAYER met1 ;
        RECT 0 3.94 5.98 4.34 ;
    END
  END VDD
  PIN VSS
    DIRECTION INPUT ;
    USE GROUND ;
    SHAPE ABUTMENT ;
    NETEXPR "VSS VSS!" ;
    PORT
      LAYER met1 ;
        RECT 0 -0.2 5.98 0.2 ;
    END
  END VSS
  PIN Y
    DIRECTION OUTPUT ;
    USE SIGNAL ;
    ANTENNADIFFAREA 2.2064 LAYER met1 ;
    PORT
      LAYER met1 ;
        RECT 0.545 3.21 5.545 3.5 ;
        RECT 0.545 0.61 4.275 0.9 ;
        RECT 4.01 0.61 4.27 3.5 ;
    END
  END Y
  PROPERTY CatenaDesignType "deviceLevel" ;
END CLKINVX4_HS

MACRO CLKINVX8_HS
  CLASS CORE ;
  ORIGIN 0 0 ;
  FOREIGN CLKINVX8_HS 0 0 ;
  SIZE 11.04 BY 4.14 ;
  SYMMETRY X Y ;
  SITE CoreSite ;
  PIN A
    DIRECTION INPUT ;
    USE SIGNAL ;
    ANTENNAMODEL OXIDE1 ;
      ANTENNAGATEAREA 4.728 LAYER met1 ;
      ANTENNAMAXAREACAR 0.515609 LAYER met1 ;
      ANTENNAMAXSIDEAREACAR 0.441201 LAYER met1 ;
    PORT
      LAYER met1 ;
        RECT 0.33 1.465 0.59 2.705 ;
    END
  END A
  PIN VDD
    DIRECTION INPUT ;
    USE POWER ;
    SHAPE ABUTMENT ;
    NETEXPR "VDD VDD!" ;
    PORT
      LAYER met1 ;
        RECT 0 3.94 11.04 4.34 ;
    END
  END VDD
  PIN VSS
    DIRECTION INPUT ;
    USE GROUND ;
    SHAPE ABUTMENT ;
    NETEXPR "VSS VSS!" ;
    PORT
      LAYER met1 ;
        RECT 0 -0.2 11.04 0.2 ;
    END
  END VSS
  PIN Y
    DIRECTION OUTPUT ;
    USE SIGNAL ;
    ANTENNADIFFAREA 4.4128 LAYER met1 ;
    PORT
      LAYER met1 ;
        RECT 0.545 3.21 10.58 3.5 ;
        RECT 0.545 0.61 4.275 0.9 ;
        RECT 4.01 0.61 4.27 3.5 ;
    END
  END Y
  PROPERTY CatenaDesignType "deviceLevel" ;
  PROPERTY oaTaper "virtuosoDefaultSetup" ;
END CLKINVX8_HS

MACRO CLKMX2X2_HS
  CLASS CORE ;
  ORIGIN 0 0 ;
  FOREIGN CLKMX2X2_HS 0 0 ;
  SIZE 3.68 BY 4.14 ;
  SYMMETRY X Y ;
  SITE CoreSite ;
  PIN A
    DIRECTION INPUT ;
    USE SIGNAL ;
    ANTENNAMODEL OXIDE1 ;
      ANTENNAGATEAREA 0.18075 LAYER met1 ;
      ANTENNAMAXAREACAR 0.686584 LAYER met1 ;
      ANTENNAMAXSIDEAREACAR 0.807746 LAYER met1 ;
    PORT
      LAYER met1 ;
        RECT 0.79 2.02 1.05 3.26 ;
    END
  END A
  PIN B
    DIRECTION INPUT ;
    USE SIGNAL ;
    ANTENNAMODEL OXIDE1 ;
      ANTENNAGATEAREA 0.18075 LAYER met1 ;
      ANTENNAMAXAREACAR 0.672476 LAYER met1 ;
      ANTENNAMAXSIDEAREACAR 0.791148 LAYER met1 ;
    PORT
      LAYER met1 ;
        RECT 2.17 1.505 2.43 2.745 ;
    END
  END B
  PIN S0
    DIRECTION INPUT ;
    USE SIGNAL ;
    ANTENNAMODEL OXIDE1 ;
      ANTENNAGATEAREA 0.3615 LAYER met1 ;
      ANTENNAMAXAREACAR 0.94758 LAYER met1 ;
      ANTENNAMAXSIDEAREACAR 0.954357 LAYER met1 ;
    PORT
      LAYER met1 ;
        RECT 1.25 1.69 1.51 2.93 ;
    END
  END S0
  PIN VDD
    DIRECTION INPUT ;
    USE POWER ;
    SHAPE ABUTMENT ;
    NETEXPR "VDD VDD!" ;
    PORT
      LAYER met1 ;
        RECT 0 3.94 3.68 4.34 ;
    END
  END VDD
  PIN VSS
    DIRECTION INPUT ;
    USE GROUND ;
    SHAPE ABUTMENT ;
    NETEXPR "VSS VSS!" ;
    PORT
      LAYER met1 ;
        RECT 0 -0.2 3.68 0.2 ;
    END
  END VSS
  PIN Y
    DIRECTION OUTPUT ;
    USE SIGNAL ;
    ANTENNADIFFAREA 0.5376 LAYER met1 ;
    PORT
      LAYER met1 ;
        RECT 2.63 0.59 3.015 3.45 ;
    END
  END Y
  OBS
    LAYER met1 ;
      RECT 1.435 3.24 1.88 3.53 ;
      RECT 1.65 0.615 1.88 3.53 ;
      RECT 1.435 0.615 1.88 0.905 ;
      RECT 0.145 0.615 0.375 3.235 ;
  END
  PROPERTY CatenaDesignType "deviceLevel" ;
END CLKMX2X2_HS

MACRO CLKXOR2X1_HS
  CLASS CORE ;
  ORIGIN 0 0 ;
  FOREIGN CLKXOR2X1_HS 0 0 ;
  SIZE 3.68 BY 4.14 ;
  SYMMETRY X Y ;
  SITE CoreSite ;
  PIN A
    DIRECTION INPUT ;
    USE SIGNAL ;
    ANTENNAMODEL OXIDE1 ;
      ANTENNAGATEAREA 0.18075 LAYER met1 ;
      ANTENNAMAXAREACAR 0.606639 LAYER met1 ;
      ANTENNAMAXSIDEAREACAR 0.713693 LAYER met1 ;
    PORT
      LAYER met1 ;
        RECT 0.79 1.285 1.05 2.525 ;
    END
  END A
  PIN B
    DIRECTION INPUT ;
    USE SIGNAL ;
    ANTENNAMODEL OXIDE1 ;
      ANTENNAGATEAREA 0.3615 LAYER met1 ;
      ANTENNAMAXAREACAR 1.795934 LAYER met1 ;
      ANTENNAMAXSIDEAREACAR 1.767635 LAYER met1 ;
    PORT
      LAYER met1 ;
        RECT 1.25 1.31 1.51 2.55 ;
    END
  END B
  PIN VDD
    DIRECTION INPUT ;
    USE POWER ;
    SHAPE ABUTMENT ;
    NETEXPR "VDD VDD!" ;
    PORT
      LAYER met1 ;
        RECT 0 3.94 3.68 4.34 ;
    END
  END VDD
  PIN VSS
    DIRECTION INPUT ;
    USE GROUND ;
    SHAPE ABUTMENT ;
    NETEXPR "VSS VSS!" ;
    PORT
      LAYER met1 ;
        RECT 0 -0.2 3.68 0.2 ;
    END
  END VSS
  PIN Y
    DIRECTION OUTPUT ;
    USE SIGNAL ;
    ANTENNADIFFAREA 0.5883 LAYER met1 ;
    PORT
      LAYER met1 ;
        RECT 2.785 2.48 3.35 2.74 ;
        RECT 3.09 0.81 3.35 2.74 ;
        RECT 2.77 0.81 3.35 1.07 ;
        RECT 2.77 0.42 3.03 1.07 ;
        RECT 2.785 2.48 3.015 3.49 ;
    END
  END Y
  OBS
    LAYER met1 ;
      RECT 1.405 3.46 1.695 3.69 ;
      RECT 1.405 3.46 2.57 3.63 ;
      RECT 2.31 0.34 2.57 3.63 ;
      RECT 1.405 0.34 1.695 0.57 ;
      RECT 1.405 0.34 2.57 0.51 ;
      RECT 0.975 3.12 1.265 3.35 ;
      RECT 0.975 3.12 2.075 3.29 ;
      RECT 1.815 0.71 2.075 3.29 ;
      RECT 0.975 0.71 2.075 0.88 ;
      RECT 0.975 0.62 1.265 0.88 ;
      RECT 0.145 3.435 0.375 3.725 ;
      RECT 0.175 0.46 0.345 3.725 ;
      RECT 0.175 1.415 0.405 1.705 ;
      RECT 0.145 0.46 0.375 0.75 ;
  END
  PROPERTY CatenaDesignType "deviceLevel" ;
END CLKXOR2X1_HS

MACRO DFFRX1_HS
  CLASS CORE ;
  ORIGIN 0 0 ;
  FOREIGN DFFRX1_HS 0 0 ;
  SIZE 9.2 BY 4.14 ;
  SYMMETRY X Y ;
  SITE CoreSite ;
  PIN CK
    DIRECTION INPUT ;
    USE SIGNAL ;
    ANTENNAMODEL OXIDE1 ;
      ANTENNAGATEAREA 0.18075 LAYER met1 ;
      ANTENNAMAXAREACAR 0.799447 LAYER met1 ;
      ANTENNAMAXSIDEAREACAR 0.940526 LAYER met1 ;
    PORT
      LAYER met1 ;
        RECT 0.79 2.315 1.05 3.555 ;
    END
  END CK
  PIN D
    DIRECTION INPUT ;
    USE SIGNAL ;
    ANTENNAMODEL OXIDE1 ;
      ANTENNAGATEAREA 0.18075 LAYER met1 ;
      ANTENNAMAXAREACAR 0.686584 LAYER met1 ;
      ANTENNAMAXSIDEAREACAR 0.807746 LAYER met1 ;
    PORT
      LAYER met1 ;
        RECT 0.79 0.385 1.05 1.625 ;
    END
  END D
  PIN Q
    DIRECTION OUTPUT ;
    USE SIGNAL ;
    ANTENNADIFFAREA 0.5883 LAYER met1 ;
    PORT
      LAYER met1 ;
        RECT 7.69 2.44 7.955 3.45 ;
        RECT 7.725 0.485 7.955 1.135 ;
        RECT 7.69 0.68 7.95 3.45 ;
    END
  END Q
  PIN QN
    DIRECTION OUTPUT ;
    USE SIGNAL ;
    ANTENNADIFFAREA 0.5883 LAYER met1 ;
    PORT
      LAYER met1 ;
        RECT 8.585 2.44 8.87 3.45 ;
        RECT 8.61 0.68 8.87 3.45 ;
        RECT 8.585 0.485 8.815 1.135 ;
    END
  END QN
  PIN RN
    DIRECTION INPUT ;
    USE SIGNAL ;
    ANTENNAMODEL OXIDE1 ;
      ANTENNAGATEAREA 0.3615 LAYER met1 ;
      ANTENNAMAXAREACAR 2.283126 LAYER met1 ;
      ANTENNAMAXSIDEAREACAR 2.591978 LAYER met1 ;
    PORT
      LAYER met1 ;
        RECT 6.77 1.405 7.03 2.645 ;
    END
  END RN
  PIN VDD
    DIRECTION INPUT ;
    USE POWER ;
    SHAPE ABUTMENT ;
    NETEXPR "VDD VDD!" ;
    PORT
      LAYER met1 ;
        RECT 0 3.94 9.2 4.34 ;
    END
  END VDD
  PIN VSS
    DIRECTION INPUT ;
    USE GROUND ;
    SHAPE ABUTMENT ;
    NETEXPR "VSS VSS!" ;
    PORT
      LAYER met1 ;
        RECT 0 -0.2 9.2 0.2 ;
    END
  END VSS
  OBS
    LAYER met1 ;
      RECT 6.345 0.765 6.575 3.53 ;
      RECT 5.915 0.765 6.575 0.995 ;
      RECT 5.915 0.51 6.145 0.995 ;
      RECT 1.435 3.375 3.905 3.605 ;
      RECT 3.675 2.495 3.905 3.605 ;
      RECT 1.435 0.51 1.665 3.605 ;
      RECT 2.725 2.945 2.955 3.235 ;
      RECT 1.865 2.945 2.095 3.235 ;
      RECT 1.865 3.005 2.955 3.175 ;
      RECT 7.205 0.415 7.435 3.53 ;
      RECT 4.965 0.95 5.195 2.795 ;
      RECT 4.535 0.51 4.765 3.235 ;
      RECT 4.105 0.51 4.335 3.235 ;
      RECT 3.245 0.51 3.475 3.235 ;
      RECT 0.145 0.51 0.375 3.235 ;
  END
  PROPERTY CatenaDesignType "deviceLevel" ;
END DFFRX1_HS

MACRO DFFRX4_HS
  CLASS CORE ;
  ORIGIN 0 0 ;
  FOREIGN DFFRX4_HS 0 0 ;
  SIZE 12.42 BY 4.14 ;
  SYMMETRY X Y ;
  SITE CoreSite ;
  PIN CK
    DIRECTION INPUT ;
    USE SIGNAL ;
    ANTENNAMODEL OXIDE1 ;
      ANTENNAGATEAREA 0.18075 LAYER met1 ;
      ANTENNAMAXAREACAR 0.879391 LAYER met1 ;
      ANTENNAMAXSIDEAREACAR 1.034578 LAYER met1 ;
    PORT
      LAYER met1 ;
        RECT 0.79 2.045 1.05 3.285 ;
    END
  END CK
  PIN D
    DIRECTION INPUT ;
    USE SIGNAL ;
    ANTENNAMODEL OXIDE1 ;
      ANTENNAGATEAREA 0.18075 LAYER met1 ;
      ANTENNAMAXAREACAR 0.686584 LAYER met1 ;
      ANTENNAMAXSIDEAREACAR 0.807746 LAYER met1 ;
    PORT
      LAYER met1 ;
        RECT 0.79 0.645 1.05 1.885 ;
    END
  END D
  PIN Q
    DIRECTION OUTPUT ;
    USE SIGNAL ;
    ANTENNADIFFAREA 1.2432 LAYER met1 ;
    PORT
      LAYER met1 ;
        RECT 9.875 2.44 10.25 3.45 ;
        RECT 9.99 0.68 10.25 3.45 ;
        RECT 9.875 0.485 10.105 1.135 ;
        RECT 9.015 1.77 10.25 2 ;
        RECT 9.015 0.485 9.245 3.45 ;
    END
  END Q
  PIN QN
    DIRECTION OUTPUT ;
    USE SIGNAL ;
    ANTENNADIFFAREA 1.2432 LAYER met1 ;
    PORT
      LAYER met1 ;
        RECT 11.595 2.44 12.09 3.45 ;
        RECT 11.83 0.68 12.09 3.45 ;
        RECT 10.735 1.77 12.09 2 ;
        RECT 11.595 0.68 12.09 1.33 ;
        RECT 11.595 0.485 11.825 1.33 ;
        RECT 10.735 0.485 10.965 3.45 ;
    END
  END QN
  PIN RN
    DIRECTION INPUT ;
    USE SIGNAL ;
    ANTENNAMODEL OXIDE1 ;
      ANTENNAGATEAREA 0.73575 LAYER met1 ;
      ANTENNAMAXAREACAR 1.141881 LAYER met1 ;
      ANTENNAMAXSIDEAREACAR 1.201495 LAYER met1 ;
    PORT
      LAYER met1 ;
        RECT 5.85 1.85 6.11 3.09 ;
    END
  END RN
  PIN VDD
    DIRECTION INPUT ;
    USE POWER ;
    SHAPE ABUTMENT ;
    NETEXPR "VDD VDD!" ;
    PORT
      LAYER met1 ;
        RECT 0 3.94 12.425 4.34 ;
    END
  END VDD
  PIN VSS
    DIRECTION INPUT ;
    USE GROUND ;
    SHAPE ABUTMENT ;
    NETEXPR "VSS VSS!" ;
    PORT
      LAYER met1 ;
        RECT 0 -0.2 12.425 0.2 ;
    END
  END VSS
  OBS
    LAYER met1 ;
      RECT 7.635 0.4 7.865 0.705 ;
      RECT 6.775 0.4 7.005 0.705 ;
      RECT 5.915 0.4 6.145 0.705 ;
      RECT 5.915 0.4 7.865 0.63 ;
      RECT 6.345 3.1 7.435 3.33 ;
      RECT 7.205 0.775 7.435 3.33 ;
      RECT 6.345 2.665 6.575 3.33 ;
      RECT 1.435 3.375 3.905 3.605 ;
      RECT 3.675 2.495 3.905 3.605 ;
      RECT 1.435 0.51 1.665 3.605 ;
      RECT 2.725 2.945 2.955 3.235 ;
      RECT 1.865 2.945 2.095 3.235 ;
      RECT 1.865 3.005 2.955 3.175 ;
      RECT 8.155 0.485 8.385 3.45 ;
      RECT 4.965 0.95 5.195 2.795 ;
      RECT 4.535 0.51 4.765 3.235 ;
      RECT 4.105 0.51 4.335 3.235 ;
      RECT 3.245 0.51 3.475 3.235 ;
      RECT 0.145 0.51 0.375 3.235 ;
  END
  PROPERTY CatenaDesignType "deviceLevel" ;
END DFFRX4_HS

MACRO DFFSRX1_HS
  CLASS CORE ;
  ORIGIN 0 0 ;
  FOREIGN DFFSRX1_HS 0 0 ;
  SIZE 11.5 BY 4.14 ;
  SYMMETRY X Y ;
  SITE CoreSite ;
  PIN CK
    DIRECTION INPUT ;
    USE SIGNAL ;
    ANTENNAMODEL OXIDE1 ;
      ANTENNAGATEAREA 0.18075 LAYER met1 ;
      ANTENNAMAXAREACAR 0.888797 LAYER met1 ;
      ANTENNAMAXSIDEAREACAR 1.045643 LAYER met1 ;
    PORT
      LAYER met1 ;
        RECT 0.79 2.19 1.05 3.43 ;
    END
  END CK
  PIN D
    DIRECTION INPUT ;
    USE SIGNAL ;
    ANTENNAMODEL OXIDE1 ;
      ANTENNAGATEAREA 0.18075 LAYER met1 ;
      ANTENNAMAXAREACAR 0.550207 LAYER met1 ;
      ANTENNAMAXSIDEAREACAR 0.647303 LAYER met1 ;
    PORT
      LAYER met1 ;
        RECT 0.79 0.805 1.05 2.045 ;
    END
  END D
  PIN Q
    DIRECTION OUTPUT ;
    USE SIGNAL ;
    ANTENNADIFFAREA 0.5883 LAYER met1 ;
    PORT
      LAYER met1 ;
        RECT 10.215 2.42 10.71 3.57 ;
        RECT 10.45 0.375 10.71 3.57 ;
        RECT 10.215 0.375 10.71 1.275 ;
    END
  END Q
  PIN QN
    DIRECTION OUTPUT ;
    USE SIGNAL ;
    ANTENNADIFFAREA 0.5883 LAYER met1 ;
    PORT
      LAYER met1 ;
        RECT 10.91 2.42 11.305 3.57 ;
        RECT 10.91 0.375 11.305 1.275 ;
        RECT 10.91 0.375 11.17 3.57 ;
    END
  END QN
  PIN RN
    DIRECTION INPUT ;
    USE SIGNAL ;
    ANTENNAMODEL OXIDE1 ;
      ANTENNAGATEAREA 0.18075 LAYER met1 ;
      ANTENNAMAXAREACAR 0.757123 LAYER met1 ;
      ANTENNAMAXSIDEAREACAR 0.890733 LAYER met1 ;
    PORT
      LAYER met1 ;
        RECT 6.77 1.155 7.03 2.395 ;
    END
  END RN
  PIN SN
    DIRECTION INPUT ;
    USE SIGNAL ;
    ANTENNAMODEL OXIDE1 ;
      ANTENNAGATEAREA 0.3615 LAYER met1 ;
      ANTENNAMAXAREACAR 1.526003 LAYER met1 ;
      ANTENNAMAXSIDEAREACAR 1.701245 LAYER met1 ;
    PORT
      LAYER met1 ;
        RECT 4.01 1.075 4.27 2.315 ;
    END
  END SN
  PIN VDD
    DIRECTION INPUT ;
    USE POWER ;
    SHAPE ABUTMENT ;
    NETEXPR "VDD VDD!" ;
    PORT
      LAYER met1 ;
        RECT 0 3.94 11.5 4.34 ;
    END
  END VDD
  PIN VSS
    DIRECTION INPUT ;
    USE GROUND ;
    SHAPE ABUTMENT ;
    NETEXPR "VSS VSS!" ;
    PORT
      LAYER met1 ;
        RECT 0 -0.2 11.5 0.2 ;
    END
  END VSS
  OBS
    LAYER met1 ;
      RECT 5.945 0.845 8.545 1.015 ;
      RECT 8.315 0.555 8.545 1.015 ;
      RECT 5.945 0.555 6.175 1.015 ;
      RECT 5.555 3.425 8.545 3.595 ;
      RECT 8.315 3.26 8.545 3.595 ;
      RECT 5.555 3.26 5.785 3.595 ;
      RECT 5.125 2.535 5.355 3.235 ;
      RECT 8.05 2.495 8.28 2.785 ;
      RECT 5.125 2.535 8.28 2.765 ;
      RECT 5.515 0.51 5.745 2.765 ;
      RECT 7.885 2.945 8.115 3.235 ;
      RECT 6.415 2.945 6.645 3.235 ;
      RECT 6.415 3.005 8.115 3.175 ;
      RECT 3.405 3.005 4.925 3.235 ;
      RECT 4.695 0.715 4.925 3.235 ;
      RECT 3.405 2.945 3.635 3.235 ;
      RECT 4.695 0.715 5.315 0.945 ;
      RECT 5.085 0.46 5.315 0.945 ;
      RECT 4.075 0.345 4.365 0.575 ;
      RECT 3.215 0.345 3.505 0.575 ;
      RECT 3.215 0.375 4.365 0.545 ;
      RECT 3.34 1.42 3.57 1.71 ;
      RECT 3.34 1.5 3.86 1.64 ;
      RECT 3.72 0.685 3.86 1.64 ;
      RECT 3.645 0.685 3.935 0.915 ;
      RECT 1.435 3.405 3.265 3.575 ;
      RECT 3.095 2.105 3.265 3.575 ;
      RECT 1.435 0.51 1.665 3.575 ;
      RECT 3.095 2.105 3.325 2.395 ;
      RECT 9.695 0.51 9.925 3.235 ;
      RECT 8.835 0.51 9.065 3.235 ;
      RECT 6.345 0.475 8.145 0.705 ;
      RECT 2.725 0.51 2.955 3.235 ;
      RECT 0.145 0.51 0.375 3.235 ;
  END
  PROPERTY CatenaDesignType "deviceLevel" ;
END DFFSRX1_HS

MACRO DFFSRX4_HS
  CLASS CORE ;
  ORIGIN 0 0 ;
  FOREIGN DFFSRX4_HS 0 0 ;
  SIZE 14.72 BY 4.14 ;
  SYMMETRY X Y ;
  SITE CoreSite ;
  PIN CK
    DIRECTION INPUT ;
    USE SIGNAL ;
    ANTENNAMODEL OXIDE1 ;
      ANTENNAGATEAREA 0.18075 LAYER met1 ;
      ANTENNAMAXAREACAR 0.874689 LAYER met1 ;
      ANTENNAMAXSIDEAREACAR 1.029046 LAYER met1 ;
    PORT
      LAYER met1 ;
        RECT 0.79 2.19 1.05 3.43 ;
    END
  END CK
  PIN D
    DIRECTION INPUT ;
    USE SIGNAL ;
    ANTENNAMODEL OXIDE1 ;
      ANTENNAGATEAREA 0.18075 LAYER met1 ;
      ANTENNAMAXAREACAR 0.686584 LAYER met1 ;
      ANTENNAMAXSIDEAREACAR 0.807746 LAYER met1 ;
    PORT
      LAYER met1 ;
        RECT 0.79 0.805 1.05 2.045 ;
    END
  END D
  PIN Q
    DIRECTION OUTPUT ;
    USE SIGNAL ;
    ANTENNADIFFAREA 1.2432 LAYER met1 ;
    PORT
      LAYER met1 ;
        RECT 11.83 2.44 12.165 3.45 ;
        RECT 11.935 0.485 12.165 1.135 ;
        RECT 11.83 0.68 12.09 3.45 ;
        RECT 11.075 1.77 12.09 2 ;
        RECT 11.075 0.485 11.305 3.45 ;
    END
  END Q
  PIN QN
    DIRECTION OUTPUT ;
    USE SIGNAL ;
    ANTENNADIFFAREA 1.2432 LAYER met1 ;
    PORT
      LAYER met1 ;
        RECT 13.655 0.68 13.93 3.45 ;
        RECT 13.655 0.485 13.885 3.45 ;
        RECT 12.795 1.77 13.93 2 ;
        RECT 12.795 0.485 13.025 3.45 ;
    END
  END QN
  PIN RN
    DIRECTION INPUT ;
    USE SIGNAL ;
    ANTENNAMODEL OXIDE1 ;
      ANTENNAGATEAREA 0.18075 LAYER met1 ;
      ANTENNAMAXAREACAR 0.757123 LAYER met1 ;
      ANTENNAMAXSIDEAREACAR 0.890733 LAYER met1 ;
    PORT
      LAYER met1 ;
        RECT 6.77 1.62 7.03 2.86 ;
    END
  END RN
  PIN SN
    DIRECTION INPUT ;
    USE SIGNAL ;
    ANTENNAMODEL OXIDE1 ;
      ANTENNAGATEAREA 0.3615 LAYER met1 ;
      ANTENNAMAXAREACAR 1.5213 LAYER met1 ;
      ANTENNAMAXSIDEAREACAR 1.695712 LAYER met1 ;
    PORT
      LAYER met1 ;
        RECT 4.01 1.06 4.27 2.3 ;
        RECT 4.035 0.95 4.265 2.3 ;
    END
  END SN
  PIN VDD
    DIRECTION INPUT ;
    USE POWER ;
    SHAPE ABUTMENT ;
    NETEXPR "VDD VDD!" ;
    PORT
      LAYER met1 ;
        RECT 0 3.94 14.72 4.34 ;
    END
  END VDD
  PIN VSS
    DIRECTION INPUT ;
    USE GROUND ;
    SHAPE ABUTMENT ;
    NETEXPR "VSS VSS!" ;
    PORT
      LAYER met1 ;
        RECT 0 -0.2 14.72 0.2 ;
    END
  END VSS
  OBS
    LAYER met1 ;
      RECT 5.125 1.25 5.355 3.235 ;
      RECT 8.835 1.25 9.065 2.115 ;
      RECT 5.125 1.25 9.065 1.48 ;
      RECT 5.515 0.51 5.745 1.48 ;
      RECT 5.945 0.715 8.545 0.885 ;
      RECT 8.315 0.51 8.545 0.885 ;
      RECT 5.945 0.51 6.175 0.885 ;
      RECT 5.555 3.405 8.545 3.575 ;
      RECT 8.315 3.24 8.545 3.575 ;
      RECT 5.555 3.24 5.785 3.575 ;
      RECT 7.855 0.345 8.145 0.575 ;
      RECT 6.345 0.345 6.635 0.575 ;
      RECT 6.345 0.375 8.145 0.545 ;
      RECT 7.885 2.945 8.115 3.235 ;
      RECT 6.415 2.945 6.645 3.235 ;
      RECT 6.415 3.005 8.115 3.175 ;
      RECT 3.405 3.005 4.925 3.235 ;
      RECT 4.695 0.715 4.925 3.235 ;
      RECT 3.405 2.945 3.635 3.235 ;
      RECT 4.695 0.715 5.315 0.945 ;
      RECT 5.085 0.46 5.315 0.945 ;
      RECT 4.075 0.345 4.365 0.575 ;
      RECT 3.215 0.345 3.505 0.575 ;
      RECT 3.215 0.375 4.365 0.545 ;
      RECT 1.435 3.405 3.265 3.575 ;
      RECT 3.095 2.155 3.265 3.575 ;
      RECT 1.435 0.51 1.665 3.575 ;
      RECT 3.095 2.155 3.325 2.445 ;
      RECT 10.215 0.485 10.445 3.45 ;
      RECT 9.265 0.685 9.495 3.315 ;
      RECT 2.725 0.51 2.955 3.235 ;
      RECT 0.145 0.51 0.375 3.235 ;
  END
  PROPERTY CatenaDesignType "deviceLevel" ;
END DFFSRX4_HS

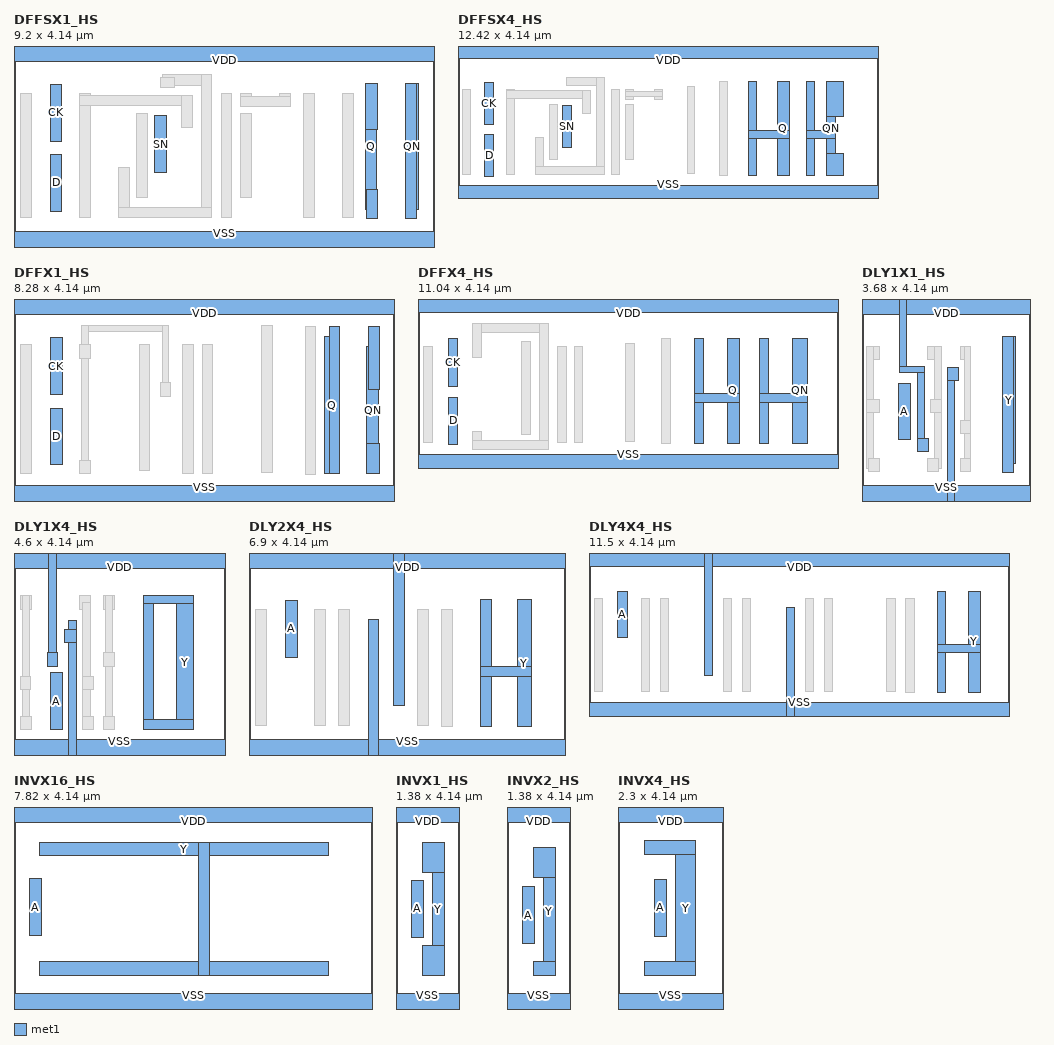
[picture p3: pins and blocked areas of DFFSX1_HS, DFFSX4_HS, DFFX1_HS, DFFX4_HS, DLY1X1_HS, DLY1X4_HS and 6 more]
MACRO DFFSX1_HS
  CLASS CORE ;
  ORIGIN 0 0 ;
  FOREIGN DFFSX1_HS 0 0 ;
  SIZE 9.2 BY 4.14 ;
  SYMMETRY X Y ;
  SITE CoreSite ;
  PIN CK
    DIRECTION INPUT ;
    USE SIGNAL ;
    ANTENNAMODEL OXIDE1 ;
      ANTENNAGATEAREA 0.18075 LAYER met1 ;
      ANTENNAMAXAREACAR 0.874689 LAYER met1 ;
      ANTENNAMAXSIDEAREACAR 1.029046 LAYER met1 ;
    PORT
      LAYER met1 ;
        RECT 0.79 2.19 1.05 3.43 ;
    END
  END CK
  PIN D
    DIRECTION INPUT ;
    USE SIGNAL ;
    ANTENNAMODEL OXIDE1 ;
      ANTENNAGATEAREA 0.18075 LAYER met1 ;
      ANTENNAMAXAREACAR 0.686584 LAYER met1 ;
      ANTENNAMAXSIDEAREACAR 0.807746 LAYER met1 ;
    PORT
      LAYER met1 ;
        RECT 0.79 0.655 1.05 1.895 ;
    END
  END D
  PIN Q
    DIRECTION OUTPUT ;
    USE SIGNAL ;
    ANTENNADIFFAREA 0.5883 LAYER met1 ;
    PORT
      LAYER met1 ;
        RECT 7.69 2.44 7.955 3.45 ;
        RECT 7.725 0.485 7.955 1.135 ;
        RECT 7.69 0.68 7.95 3.45 ;
    END
  END Q
  PIN QN
    DIRECTION OUTPUT ;
    USE SIGNAL ;
    ANTENNADIFFAREA 0.5883 LAYER met1 ;
    PORT
      LAYER met1 ;
        RECT 8.585 0.68 8.87 3.45 ;
        RECT 8.585 0.485 8.815 3.45 ;
    END
  END QN
  PIN SN
    DIRECTION INPUT ;
    USE SIGNAL ;
    ANTENNAMODEL OXIDE1 ;
      ANTENNAGATEAREA 0.3615 LAYER met1 ;
      ANTENNAMAXAREACAR 1.5213 LAYER met1 ;
      ANTENNAMAXSIDEAREACAR 1.695712 LAYER met1 ;
    PORT
      LAYER met1 ;
        RECT 3.085 1.5 3.345 2.74 ;
    END
  END SN
  PIN VDD
    DIRECTION INPUT ;
    USE POWER ;
    SHAPE ABUTMENT ;
    NETEXPR "VDD VDD!" ;
    PORT
      LAYER met1 ;
        RECT 0 3.94 9.2 4.34 ;
    END
  END VDD
  PIN VSS
    DIRECTION INPUT ;
    USE GROUND ;
    SHAPE ABUTMENT ;
    NETEXPR "VSS VSS!" ;
    PORT
      LAYER met1 ;
        RECT 0 -0.2 9.2 0.2 ;
    END
  END VSS
  OBS
    LAYER met1 ;
      RECT 5.825 2.945 6.055 3.235 ;
      RECT 4.965 2.945 5.195 3.235 ;
      RECT 4.965 2.945 6.055 3.175 ;
      RECT 3.245 3.41 4.335 3.64 ;
      RECT 4.105 0.51 4.335 3.64 ;
      RECT 3.215 3.355 3.505 3.585 ;
      RECT 2.295 0.51 2.525 1.6 ;
      RECT 2.295 0.51 4.335 0.74 ;
      RECT 1.435 0.51 1.665 3.235 ;
      RECT 1.435 2.965 3.905 3.195 ;
      RECT 3.675 2.495 3.905 3.195 ;
      RECT 7.205 0.51 7.435 3.235 ;
      RECT 6.345 0.51 6.575 3.235 ;
      RECT 4.965 0.95 5.195 2.795 ;
      RECT 4.535 0.51 4.765 3.235 ;
      RECT 2.685 0.95 2.915 2.795 ;
      RECT 0.145 0.51 0.375 3.235 ;
  END
  PROPERTY CatenaDesignType "deviceLevel" ;
END DFFSX1_HS

MACRO DFFSX4_HS
  CLASS CORE ;
  ORIGIN 0 0 ;
  FOREIGN DFFSX4_HS 0 0 ;
  SIZE 12.42 BY 4.14 ;
  SYMMETRY X Y ;
  SITE CoreSite ;
  PIN CK
    DIRECTION INPUT ;
    USE SIGNAL ;
    ANTENNAMODEL OXIDE1 ;
      ANTENNAGATEAREA 0.18075 LAYER met1 ;
      ANTENNAMAXAREACAR 0.874689 LAYER met1 ;
      ANTENNAMAXSIDEAREACAR 1.029046 LAYER met1 ;
    PORT
      LAYER met1 ;
        RECT 0.79 1.995 1.05 3.235 ;
    END
  END CK
  PIN D
    DIRECTION INPUT ;
    USE SIGNAL ;
    ANTENNAMODEL OXIDE1 ;
      ANTENNAGATEAREA 0.18075 LAYER met1 ;
      ANTENNAMAXAREACAR 0.686584 LAYER met1 ;
      ANTENNAMAXSIDEAREACAR 0.807746 LAYER met1 ;
    PORT
      LAYER met1 ;
        RECT 0.79 0.46 1.05 1.7 ;
    END
  END D
  PIN Q
    DIRECTION OUTPUT ;
    USE SIGNAL ;
    ANTENNADIFFAREA 1.2432 LAYER met1 ;
    PORT
      LAYER met1 ;
        RECT 9.445 0.485 9.79 3.255 ;
        RECT 8.585 1.575 9.79 1.805 ;
        RECT 8.585 0.485 8.815 3.255 ;
    END
  END Q
  PIN QN
    DIRECTION OUTPUT ;
    USE SIGNAL ;
    ANTENNADIFFAREA 1.2432 LAYER met1 ;
    PORT
      LAYER met1 ;
        RECT 10.885 2.245 11.395 3.255 ;
        RECT 10.885 0.485 11.395 1.135 ;
        RECT 10.885 0.485 11.17 3.255 ;
        RECT 10.305 1.575 11.17 1.805 ;
        RECT 10.305 0.485 10.535 3.255 ;
    END
  END QN
  PIN SN
    DIRECTION INPUT ;
    USE SIGNAL ;
    ANTENNAMODEL OXIDE1 ;
      ANTENNAGATEAREA 0.3615 LAYER met1 ;
      ANTENNAMAXAREACAR 1.518949 LAYER met1 ;
      ANTENNAMAXSIDEAREACAR 1.692946 LAYER met1 ;
    PORT
      LAYER met1 ;
        RECT 3.09 1.305 3.35 2.545 ;
    END
  END SN
  PIN VDD
    DIRECTION INPUT ;
    USE POWER ;
    SHAPE ABUTMENT ;
    NETEXPR "VDD VDD!" ;
    PORT
      LAYER met1 ;
        RECT 0 3.94 12.42 4.34 ;
    END
  END VDD
  PIN VSS
    DIRECTION INPUT ;
    USE GROUND ;
    SHAPE ABUTMENT ;
    NETEXPR "VSS VSS!" ;
    PORT
      LAYER met1 ;
        RECT 0 -0.2 12.42 0.2 ;
    END
  END VSS
  OBS
    LAYER met1 ;
      RECT 5.825 2.75 6.055 3.04 ;
      RECT 4.965 2.75 5.195 3.04 ;
      RECT 4.965 2.81 6.055 2.98 ;
      RECT 3.215 3.16 4.335 3.39 ;
      RECT 4.105 0.51 4.335 3.39 ;
      RECT 2.295 0.51 2.525 1.6 ;
      RECT 2.295 0.51 4.335 0.74 ;
      RECT 1.435 0.51 1.665 3.04 ;
      RECT 1.435 2.77 3.905 3 ;
      RECT 3.675 2.31 3.905 3 ;
      RECT 7.725 0.485 7.955 3.255 ;
      RECT 6.775 0.55 7.005 3.12 ;
      RECT 4.965 0.95 5.195 2.6 ;
      RECT 4.535 0.51 4.765 3.04 ;
      RECT 2.71 0.95 2.94 2.6 ;
      RECT 0.145 0.51 0.375 3.04 ;
  END
  PROPERTY CatenaDesignType "deviceLevel" ;
END DFFSX4_HS

MACRO DFFX1_HS
  CLASS CORE ;
  ORIGIN 0 0 ;
  FOREIGN DFFX1_HS 0 0 ;
  SIZE 8.28 BY 4.14 ;
  SYMMETRY X Y ;
  SITE CoreSite ;
  PIN CK
    DIRECTION INPUT ;
    USE SIGNAL ;
    ANTENNAMODEL OXIDE1 ;
      ANTENNAGATEAREA 0.18075 LAYER met1 ;
      ANTENNAMAXAREACAR 0.874689 LAYER met1 ;
      ANTENNAMAXSIDEAREACAR 1.029046 LAYER met1 ;
    PORT
      LAYER met1 ;
        RECT 0.79 2.19 1.05 3.43 ;
    END
  END CK
  PIN D
    DIRECTION INPUT ;
    USE SIGNAL ;
    ANTENNAMODEL OXIDE1 ;
      ANTENNAGATEAREA 0.18075 LAYER met1 ;
      ANTENNAMAXAREACAR 0.686584 LAYER met1 ;
      ANTENNAMAXSIDEAREACAR 0.807746 LAYER met1 ;
    PORT
      LAYER met1 ;
        RECT 0.79 0.655 1.05 1.895 ;
    END
  END D
  PIN Q
    DIRECTION OUTPUT ;
    USE SIGNAL ;
    ANTENNADIFFAREA 0.5883 LAYER met1 ;
    PORT
      LAYER met1 ;
        RECT 6.865 0.465 7.095 3.67 ;
        RECT 6.77 0.465 7.095 3.45 ;
    END
  END Q
  PIN QN
    DIRECTION OUTPUT ;
    USE SIGNAL ;
    ANTENNADIFFAREA 0.5883 LAYER met1 ;
    PORT
      LAYER met1 ;
        RECT 7.725 2.3 7.955 3.67 ;
        RECT 7.69 0.465 7.955 1.115 ;
        RECT 7.69 0.465 7.95 3.235 ;
    END
  END QN
  PIN VDD
    DIRECTION INPUT ;
    USE POWER ;
    SHAPE ABUTMENT ;
    NETEXPR "VDD VDD!" ;
    PORT
      LAYER met1 ;
        RECT 0 3.94 8.28 4.34 ;
    END
  END VDD
  PIN VSS
    DIRECTION INPUT ;
    USE GROUND ;
    SHAPE ABUTMENT ;
    NETEXPR "VSS VSS!" ;
    PORT
      LAYER met1 ;
        RECT 0 -0.2 8.28 0.2 ;
    END
  END VSS
  OBS
    LAYER met1 ;
      RECT 1.48 3.555 3.37 3.695 ;
      RECT 3.23 2.155 3.37 3.695 ;
      RECT 1.48 0.46 1.62 3.695 ;
      RECT 1.435 2.985 1.665 3.275 ;
      RECT 3.19 2.155 3.42 2.445 ;
      RECT 1.435 0.46 1.665 0.75 ;
      RECT 6.345 0.445 6.575 3.675 ;
      RECT 5.395 0.5 5.625 3.69 ;
      RECT 4.105 0.46 4.335 3.275 ;
      RECT 3.675 0.46 3.905 3.275 ;
      RECT 2.725 0.54 2.955 3.275 ;
      RECT 0.145 0.46 0.375 3.275 ;
  END
  PROPERTY CatenaDesignType "deviceLevel" ;
END DFFX1_HS

MACRO DFFX4_HS
  CLASS CORE ;
  ORIGIN 0 0 ;
  FOREIGN DFFX4_HS 0 0 ;
  SIZE 11.04 BY 4.14 ;
  SYMMETRY X Y ;
  SITE CoreSite ;
  PIN CK
    DIRECTION INPUT ;
    USE SIGNAL ;
    ANTENNAMODEL OXIDE1 ;
      ANTENNAGATEAREA 0.18075 LAYER met1 ;
      ANTENNAMAXAREACAR 0.874689 LAYER met1 ;
      ANTENNAMAXSIDEAREACAR 1.029046 LAYER met1 ;
    PORT
      LAYER met1 ;
        RECT 0.79 1.995 1.05 3.235 ;
    END
  END CK
  PIN D
    DIRECTION INPUT ;
    USE SIGNAL ;
    ANTENNAMODEL OXIDE1 ;
      ANTENNAGATEAREA 0.18075 LAYER met1 ;
      ANTENNAMAXAREACAR 0.686584 LAYER met1 ;
      ANTENNAMAXSIDEAREACAR 0.807746 LAYER met1 ;
    PORT
      LAYER met1 ;
        RECT 0.79 0.46 1.05 1.7 ;
    END
  END D
  PIN Q
    DIRECTION OUTPUT ;
    USE SIGNAL ;
    ANTENNADIFFAREA 1.2432 LAYER met1 ;
    PORT
      LAYER met1 ;
        RECT 8.125 0.485 8.45 3.255 ;
        RECT 7.265 1.575 8.45 1.805 ;
        RECT 7.265 0.485 7.495 3.255 ;
    END
  END Q
  PIN QN
    DIRECTION OUTPUT ;
    USE SIGNAL ;
    ANTENNADIFFAREA 1.2432 LAYER met1 ;
    PORT
      LAYER met1 ;
        RECT 9.845 0.485 10.25 3.255 ;
        RECT 8.985 1.575 10.25 1.805 ;
        RECT 8.985 0.485 9.215 3.255 ;
    END
  END QN
  PIN VDD
    DIRECTION INPUT ;
    USE POWER ;
    SHAPE ABUTMENT ;
    NETEXPR "VDD VDD!" ;
    PORT
      LAYER met1 ;
        RECT 0 3.94 11.04 4.34 ;
    END
  END VDD
  PIN VSS
    DIRECTION INPUT ;
    USE GROUND ;
    SHAPE ABUTMENT ;
    NETEXPR "VSS VSS!" ;
    PORT
      LAYER met1 ;
        RECT 0 -0.2 11.04 0.2 ;
    END
  END VSS
  OBS
    LAYER met1 ;
      RECT 1.435 3.41 3.42 3.64 ;
      RECT 3.19 0.34 3.42 3.64 ;
      RECT 1.435 2.75 1.665 3.64 ;
      RECT 1.435 0.34 1.665 0.8 ;
      RECT 1.435 0.34 3.42 0.57 ;
      RECT 6.405 0.485 6.635 3.255 ;
      RECT 5.455 0.55 5.685 3.12 ;
      RECT 4.105 0.51 4.335 3.04 ;
      RECT 3.675 0.51 3.905 3.04 ;
      RECT 2.725 0.71 2.955 3.16 ;
      RECT 0.145 0.51 0.375 3.04 ;
  END
  PROPERTY CatenaDesignType "deviceLevel" ;
END DFFX4_HS

MACRO DLY1X1_HS
  CLASS CORE ;
  ORIGIN 0 0 ;
  FOREIGN DLY1X1_HS 0 0 ;
  SIZE 3.68 BY 4.14 ;
  SYMMETRY X Y ;
  SITE CoreSite ;
  PIN A
    DIRECTION INPUT ;
    USE SIGNAL ;
    ANTENNAMODEL OXIDE1 ;
      ANTENNAGATEAREA 0.18075 LAYER met1 ;
      ANTENNAMAXAREACAR 0.902905 LAYER met1 ;
      ANTENNAMAXSIDEAREACAR 1.062241 LAYER met1 ;
    PORT
      LAYER met1 ;
        RECT 0.79 1.2 1.05 2.44 ;
    END
  END A
  PIN VDD
    DIRECTION INPUT ;
    USE POWER ;
    SHAPE ABUTMENT ;
    NETEXPR "VDD VDD!" ;
    PORT
      LAYER met1 ;
        RECT 0 3.94 3.68 4.34 ;
        RECT 1.215 0.95 1.445 1.24 ;
        RECT 0.82 2.66 1.355 2.8 ;
        RECT 1.215 0.95 1.355 2.8 ;
        RECT 0.82 2.66 0.96 4.34 ;
    END
  END VDD
  PIN VSS
    DIRECTION INPUT ;
    USE GROUND ;
    SHAPE ABUTMENT ;
    NETEXPR "VSS VSS!" ;
    PORT
      LAYER met1 ;
        RECT 0 -0.2 3.68 0.2 ;
        RECT 1.865 2.495 2.095 2.785 ;
        RECT 1.865 -0.2 2.005 2.785 ;
    END
  END VSS
  PIN Y
    DIRECTION OUTPUT ;
    USE SIGNAL ;
    ANTENNADIFFAREA 0.5883 LAYER met1 ;
    PORT
      LAYER met1 ;
        RECT 3.065 0.68 3.35 3.45 ;
        RECT 3.065 0.485 3.295 3.45 ;
    END
  END Y
  OBS
    LAYER met1 ;
      RECT 2.145 2.955 2.375 3.245 ;
      RECT 2.235 0.51 2.375 3.245 ;
      RECT 2.145 1.33 2.375 1.62 ;
      RECT 2.145 0.51 2.375 0.8 ;
      RECT 1.435 2.955 1.725 3.245 ;
      RECT 1.585 0.585 1.725 3.245 ;
      RECT 1.495 1.8 1.725 2.09 ;
      RECT 1.435 0.51 1.665 0.8 ;
      RECT 0.09 2.945 0.375 3.235 ;
      RECT 0.09 0.57 0.26 3.235 ;
      RECT 0.09 1.8 0.375 2.09 ;
      RECT 0.145 0.51 0.375 0.8 ;
  END
  PROPERTY CatenaDesignType "deviceLevel" ;
END DLY1X1_HS

MACRO DLY1X4_HS
  CLASS CORE ;
  ORIGIN 0 0 ;
  FOREIGN DLY1X4_HS 0 0 ;
  SIZE 4.6 BY 4.14 ;
  SYMMETRY X Y ;
  SITE CoreSite ;
  PIN A
    DIRECTION INPUT ;
    USE SIGNAL ;
    ANTENNAMODEL OXIDE1 ;
      ANTENNAGATEAREA 0.18075 LAYER met1 ;
      ANTENNAMAXAREACAR 0.945228 LAYER met1 ;
      ANTENNAMAXSIDEAREACAR 1.112033 LAYER met1 ;
    PORT
      LAYER met1 ;
        RECT 0.79 0.425 1.05 1.665 ;
    END
  END A
  PIN VDD
    DIRECTION INPUT ;
    USE POWER ;
    SHAPE ABUTMENT ;
    NETEXPR "VDD VDD!" ;
    PORT
      LAYER met1 ;
        RECT 0 3.94 4.6 4.34 ;
        RECT 0.725 1.805 0.955 2.095 ;
        RECT 0.755 1.805 0.925 4.34 ;
    END
  END VDD
  PIN VSS
    DIRECTION INPUT ;
    USE GROUND ;
    SHAPE ABUTMENT ;
    NETEXPR "VSS VSS!" ;
    PORT
      LAYER met1 ;
        RECT 0 -0.2 4.6 0.2 ;
        RECT 1.19 -0.2 1.36 2.795 ;
        RECT 1.095 2.31 1.36 2.6 ;
    END
  END VSS
  PIN Y
    DIRECTION OUTPUT ;
    USE SIGNAL ;
    ANTENNADIFFAREA 1.2432 LAYER met1 ;
    PORT
      LAYER met1 ;
        RECT 2.815 3.165 3.905 3.335 ;
        RECT 3.55 0.415 3.905 3.335 ;
        RECT 2.815 0.415 3.905 0.645 ;
        RECT 2.815 0.415 3.045 3.335 ;
    END
  END Y
  OBS
    LAYER met1 ;
      RECT 1.955 3.045 2.185 3.335 ;
      RECT 1.985 0.415 2.155 3.335 ;
      RECT 1.955 1.805 2.185 2.095 ;
      RECT 1.955 0.415 2.185 0.705 ;
      RECT 1.435 3.045 1.665 3.335 ;
      RECT 1.5 0.415 1.67 3.19 ;
      RECT 1.5 1.29 1.73 1.58 ;
      RECT 1.5 0.415 1.73 0.705 ;
      RECT 0.145 3.045 0.375 3.335 ;
      RECT 0.175 0.415 0.345 3.335 ;
      RECT 0.14 1.29 0.37 1.58 ;
      RECT 0.145 0.415 0.375 0.705 ;
  END
  PROPERTY CatenaDesignType "deviceLevel" ;
END DLY1X4_HS

MACRO DLY2X4_HS
  CLASS CORE ;
  ORIGIN 0 0 ;
  FOREIGN DLY2X4_HS 0 0 ;
  SIZE 6.9 BY 4.14 ;
  SYMMETRY X Y ;
  SITE CoreSite ;
  PIN A
    DIRECTION INPUT ;
    USE SIGNAL ;
    ANTENNAMODEL OXIDE1 ;
      ANTENNAGATEAREA 0.18075 LAYER met1 ;
      ANTENNAMAXAREACAR 0.893499 LAYER met1 ;
      ANTENNAMAXSIDEAREACAR 1.051176 LAYER met1 ;
    PORT
      LAYER met1 ;
        RECT 0.79 1.995 1.05 3.235 ;
    END
  END A
  PIN VDD
    DIRECTION INPUT ;
    USE POWER ;
    SHAPE ABUTMENT ;
    NETEXPR "VDD VDD!" ;
    PORT
      LAYER met1 ;
        RECT 0 3.94 6.905 4.34 ;
        RECT 3.155 0.95 3.385 4.34 ;
    END
  END VDD
  PIN VSS
    DIRECTION INPUT ;
    USE GROUND ;
    SHAPE ABUTMENT ;
    NETEXPR "VSS VSS!" ;
    PORT
      LAYER met1 ;
        RECT 0 -0.2 6.905 0.2 ;
        RECT 2.6 -0.2 2.83 2.815 ;
    END
  END VSS
  PIN Y
    DIRECTION OUTPUT ;
    USE SIGNAL ;
    ANTENNADIFFAREA 1.2432 LAYER met1 ;
    PORT
      LAYER met1 ;
        RECT 5.85 0.485 6.145 3.255 ;
        RECT 5.055 1.575 6.145 1.805 ;
        RECT 5.055 0.485 5.285 3.255 ;
    END
  END Y
  OBS
    LAYER met1 ;
      RECT 4.195 0.485 4.425 3.04 ;
      RECT 3.675 0.51 3.905 3.04 ;
      RECT 1.955 0.51 2.185 3.04 ;
      RECT 1.435 0.51 1.665 3.04 ;
      RECT 0.145 0.51 0.375 3.04 ;
  END
  PROPERTY CatenaDesignType "deviceLevel" ;
END DLY2X4_HS

MACRO DLY4X4_HS
  CLASS CORE ;
  ORIGIN 0 0 ;
  FOREIGN DLY4X4_HS 0 0 ;
  SIZE 11.5 BY 4.14 ;
  SYMMETRY X Y ;
  SITE CoreSite ;
  PIN A
    DIRECTION INPUT ;
    USE SIGNAL ;
    ANTENNAMODEL OXIDE1 ;
      ANTENNAGATEAREA 0.18075 LAYER met1 ;
      ANTENNAMAXAREACAR 0.893499 LAYER met1 ;
      ANTENNAMAXSIDEAREACAR 1.051176 LAYER met1 ;
    PORT
      LAYER met1 ;
        RECT 0.79 1.995 1.05 3.235 ;
    END
  END A
  PIN VDD
    DIRECTION INPUT ;
    USE POWER ;
    SHAPE ABUTMENT ;
    NETEXPR "VDD VDD!" ;
    PORT
      LAYER met1 ;
        RECT 0 3.94 11.5 4.34 ;
        RECT 3.155 0.95 3.385 4.34 ;
    END
  END VDD
  PIN VSS
    DIRECTION INPUT ;
    USE GROUND ;
    SHAPE ABUTMENT ;
    NETEXPR "VSS VSS!" ;
    PORT
      LAYER met1 ;
        RECT 0 -0.2 11.505 0.2 ;
        RECT 5.395 -0.2 5.625 2.815 ;
    END
  END VSS
  PIN Y
    DIRECTION OUTPUT ;
    USE SIGNAL ;
    ANTENNADIFFAREA 1.2432 LAYER met1 ;
    PORT
      LAYER met1 ;
        RECT 10.395 0.485 10.71 3.255 ;
        RECT 9.535 1.575 10.71 1.805 ;
        RECT 9.535 0.485 9.765 3.255 ;
    END
  END Y
  OBS
    LAYER met1 ;
      RECT 8.675 0.485 8.905 3.04 ;
      RECT 8.155 0.51 8.385 3.04 ;
      RECT 6.435 0.51 6.665 3.04 ;
      RECT 5.915 0.51 6.145 3.04 ;
      RECT 4.195 0.51 4.425 3.04 ;
      RECT 3.675 0.51 3.905 3.04 ;
      RECT 1.955 0.51 2.185 3.04 ;
      RECT 1.435 0.51 1.665 3.04 ;
      RECT 0.145 0.51 0.375 3.04 ;
  END
  PROPERTY CatenaDesignType "deviceLevel" ;
END DLY4X4_HS

MACRO INVX16_HS
  CLASS CORE ;
  ORIGIN 0 0 ;
  FOREIGN INVX16_HS 0 0 ;
  SIZE 7.82 BY 4.14 ;
  SYMMETRY X Y ;
  SITE CoreSite ;
  PIN A
    DIRECTION INPUT ;
    USE SIGNAL ;
    ANTENNAMODEL OXIDE1 ;
      ANTENNAGATEAREA 5.328 LAYER met1 ;
      ANTENNAMAXAREACAR 0.303594 LAYER met1 ;
      ANTENNAMAXSIDEAREACAR 0.261449 LAYER met1 ;
    PORT
      LAYER met1 ;
        RECT 0.33 1.465 0.59 2.705 ;
    END
  END A
  PIN VDD
    DIRECTION INPUT ;
    USE POWER ;
    SHAPE ABUTMENT ;
    NETEXPR "VDD VDD!" ;
    PORT
      LAYER met1 ;
        RECT 0 3.94 7.82 4.34 ;
    END
  END VDD
  PIN VSS
    DIRECTION INPUT ;
    USE GROUND ;
    SHAPE ABUTMENT ;
    NETEXPR "VSS VSS!" ;
    PORT
      LAYER met1 ;
        RECT 0 -0.2 7.82 0.2 ;
    END
  END VSS
  PIN Y
    DIRECTION OUTPUT ;
    USE SIGNAL ;
    ANTENNADIFFAREA 4.9728 LAYER met1 ;
    PORT
      LAYER met1 ;
        RECT 0.545 3.21 6.855 3.5 ;
        RECT 0.545 0.61 6.855 0.9 ;
        RECT 4.01 0.61 4.27 3.5 ;
    END
  END Y
  PROPERTY CatenaDesignType "deviceLevel" ;
END INVX16_HS

MACRO INVX1_HS
  CLASS CORE ;
  ORIGIN 0 0 ;
  FOREIGN INVX1_HS 0 0 ;
  SIZE 1.38 BY 4.14 ;
  SYMMETRY X Y ;
  SITE CoreSite ;
  PIN A
    DIRECTION INPUT ;
    USE SIGNAL ;
    ANTENNAMODEL OXIDE1 ;
      ANTENNAGATEAREA 0.333 LAYER met1 ;
      ANTENNAMAXAREACAR 0.262913 LAYER met1 ;
      ANTENNAMAXSIDEAREACAR 0.309309 LAYER met1 ;
    PORT
      LAYER met1 ;
        RECT 0.33 1.43 0.59 2.67 ;
    END
  END A
  PIN VDD
    DIRECTION INPUT ;
    USE POWER ;
    SHAPE ABUTMENT ;
    NETEXPR "VDD VDD!" ;
    PORT
      LAYER met1 ;
        RECT 0 3.94 1.38 4.34 ;
    END
  END VDD
  PIN VSS
    DIRECTION INPUT ;
    USE GROUND ;
    SHAPE ABUTMENT ;
    NETEXPR "VSS VSS!" ;
    PORT
      LAYER met1 ;
        RECT 0 -0.2 1.38 0.2 ;
    END
  END VSS
  PIN Y
    DIRECTION OUTPUT ;
    USE SIGNAL ;
    ANTENNADIFFAREA 0.5883 LAYER met1 ;
    PORT
      LAYER met1 ;
        RECT 0.575 2.84 1.05 3.49 ;
        RECT 0.79 0.605 1.05 3.49 ;
        RECT 0.575 0.605 1.05 1.255 ;
    END
  END Y
END INVX1_HS

MACRO INVX2_HS
  CLASS CORE ;
  ORIGIN 0 0 ;
  FOREIGN INVX2_HS 0 0 ;
  SIZE 1.38 BY 4.14 ;
  SYMMETRY X Y ;
  SITE CoreSite ;
  PIN A
    DIRECTION INPUT ;
    USE SIGNAL ;
    ANTENNAMODEL OXIDE1 ;
      ANTENNAGATEAREA 0.666 LAYER met1 ;
      ANTENNAMAXAREACAR 0.320345 LAYER met1 ;
      ANTENNAMAXSIDEAREACAR 0.325826 LAYER met1 ;
    PORT
      LAYER met1 ;
        RECT 0.33 1.29 0.59 2.53 ;
    END
  END A
  PIN VDD
    DIRECTION INPUT ;
    USE POWER ;
    SHAPE ABUTMENT ;
    NETEXPR "VDD VDD!" ;
    PORT
      LAYER met1 ;
        RECT 0 3.94 1.38 4.34 ;
    END
  END VDD
  PIN VSS
    DIRECTION INPUT ;
    USE GROUND ;
    SHAPE ABUTMENT ;
    NETEXPR "VSS VSS!" ;
    PORT
      LAYER met1 ;
        RECT 0 -0.2 1.38 0.2 ;
    END
  END VSS
  PIN Y
    DIRECTION OUTPUT ;
    USE SIGNAL ;
    ANTENNADIFFAREA 0.6216 LAYER met1 ;
    PORT
      LAYER met1 ;
        RECT 0.575 2.735 1.05 3.385 ;
        RECT 0.79 0.61 1.05 3.385 ;
        RECT 0.575 0.61 1.05 0.9 ;
    END
  END Y
  PROPERTY CatenaDesignType "deviceLevel" ;
END INVX2_HS

MACRO INVX4_HS
  CLASS CORE ;
  ORIGIN 0 0 ;
  FOREIGN INVX4_HS 0 0 ;
  SIZE 2.3 BY 4.14 ;
  SYMMETRY X Y ;
  SITE CoreSite ;
  PIN A
    DIRECTION INPUT ;
    USE SIGNAL ;
    ANTENNAMODEL OXIDE1 ;
      ANTENNAGATEAREA 1.332 LAYER met1 ;
      ANTENNAMAXAREACAR 0.259084 LAYER met1 ;
      ANTENNAMAXSIDEAREACAR 0.228228 LAYER met1 ;
    PORT
      LAYER met1 ;
        RECT 0.79 1.455 1.05 2.695 ;
    END
  END A
  PIN VDD
    DIRECTION INPUT ;
    USE POWER ;
    SHAPE ABUTMENT ;
    NETEXPR "VDD VDD!" ;
    PORT
      LAYER met1 ;
        RECT 0 3.94 2.3 4.34 ;
    END
  END VDD
  PIN VSS
    DIRECTION INPUT ;
    USE GROUND ;
    SHAPE ABUTMENT ;
    NETEXPR "VSS VSS!" ;
    PORT
      LAYER met1 ;
        RECT 0 -0.2 2.3 0.2 ;
    END
  END VSS
  PIN Y
    DIRECTION OUTPUT ;
    USE SIGNAL ;
    ANTENNADIFFAREA 1.2432 LAYER met1 ;
    PORT
      LAYER met1 ;
        RECT 0.575 3.24 1.695 3.53 ;
        RECT 1.25 0.61 1.695 3.53 ;
        RECT 0.575 0.61 1.695 0.9 ;
    END
  END Y
  PROPERTY CatenaDesignType "deviceLevel" ;
END INVX4_HS

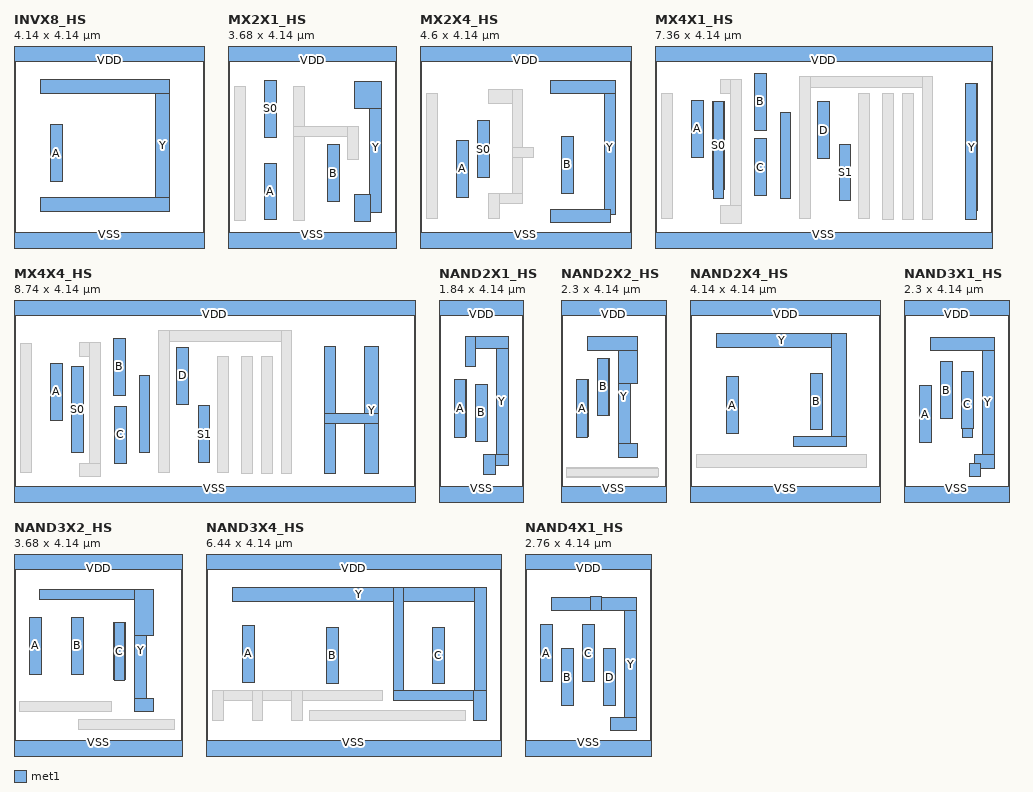
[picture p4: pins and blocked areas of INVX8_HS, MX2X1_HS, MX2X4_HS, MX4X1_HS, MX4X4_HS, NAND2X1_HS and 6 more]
MACRO INVX8_HS
  CLASS CORE ;
  ORIGIN 0 0 ;
  FOREIGN INVX8_HS 0 0 ;
  SIZE 4.14 BY 4.14 ;
  SYMMETRY X Y ;
  SITE CoreSite ;
  PIN A
    DIRECTION INPUT ;
    USE SIGNAL ;
    ANTENNAMODEL OXIDE1 ;
      ANTENNAGATEAREA 2.664 LAYER met1 ;
      ANTENNAMAXAREACAR 0.302477 LAYER met1 ;
      ANTENNAMAXSIDEAREACAR 0.266517 LAYER met1 ;
    PORT
      LAYER met1 ;
        RECT 0.79 1.315 1.05 2.555 ;
    END
  END A
  PIN VDD
    DIRECTION INPUT ;
    USE POWER ;
    SHAPE ABUTMENT ;
    NETEXPR "VDD VDD!" ;
    PORT
      LAYER met1 ;
        RECT 0 3.94 4.14 4.34 ;
    END
  END VDD
  PIN VSS
    DIRECTION INPUT ;
    USE GROUND ;
    SHAPE ABUTMENT ;
    NETEXPR "VSS VSS!" ;
    PORT
      LAYER met1 ;
        RECT 0 -0.2 4.14 0.2 ;
    END
  END VSS
  PIN Y
    DIRECTION OUTPUT ;
    USE SIGNAL ;
    ANTENNADIFFAREA 2.4864 LAYER met1 ;
    PORT
      LAYER met1 ;
        RECT 0.575 3.24 3.385 3.53 ;
        RECT 3.09 0.675 3.385 3.53 ;
        RECT 0.575 0.675 3.385 0.965 ;
    END
  END Y
  PROPERTY CatenaDesignType "deviceLevel" ;
END INVX8_HS

MACRO MX2X1_HS
  CLASS CORE ;
  ORIGIN 0 0 ;
  FOREIGN MX2X1_HS 0 0 ;
  SIZE 3.68 BY 4.14 ;
  SYMMETRY X Y ;
  SITE CoreSite ;
  PIN A
    DIRECTION INPUT ;
    USE SIGNAL ;
    ANTENNAMODEL OXIDE1 ;
      ANTENNAGATEAREA 0.18075 LAYER met1 ;
      ANTENNAMAXAREACAR 0.484371 LAYER met1 ;
      ANTENNAMAXSIDEAREACAR 0.569848 LAYER met1 ;
    PORT
      LAYER met1 ;
        RECT 0.79 0.48 1.05 1.72 ;
    END
  END A
  PIN B
    DIRECTION INPUT ;
    USE SIGNAL ;
    ANTENNAMODEL OXIDE1 ;
      ANTENNAGATEAREA 0.18075 LAYER met1 ;
      ANTENNAMAXAREACAR 0.587828 LAYER met1 ;
      ANTENNAMAXSIDEAREACAR 0.691563 LAYER met1 ;
    PORT
      LAYER met1 ;
        RECT 2.17 0.875 2.43 2.115 ;
    END
  END B
  PIN S0
    DIRECTION INPUT ;
    USE SIGNAL ;
    ANTENNAMODEL OXIDE1 ;
      ANTENNAGATEAREA 0.3615 LAYER met1 ;
      ANTENNAMAXAREACAR 1.991093 LAYER met1 ;
      ANTENNAMAXSIDEAREACAR 1.903181 LAYER met1 ;
    PORT
      LAYER met1 ;
        RECT 0.79 2.28 1.05 3.52 ;
    END
  END S0
  PIN VDD
    DIRECTION INPUT ;
    USE POWER ;
    SHAPE ABUTMENT ;
    NETEXPR "VDD VDD!" ;
    PORT
      LAYER met1 ;
        RECT 0 3.94 3.68 4.34 ;
    END
  END VDD
  PIN VSS
    DIRECTION INPUT ;
    USE GROUND ;
    SHAPE ABUTMENT ;
    NETEXPR "VSS VSS!" ;
    PORT
      LAYER met1 ;
        RECT 0 -0.2 3.68 0.2 ;
    END
  END VSS
  PIN Y
    DIRECTION OUTPUT ;
    USE SIGNAL ;
    ANTENNADIFFAREA 0.5883 LAYER met1 ;
    PORT
      LAYER met1 ;
        RECT 2.755 2.91 3.35 3.5 ;
        RECT 3.09 0.64 3.35 3.5 ;
        RECT 2.755 0.445 3.095 1.035 ;
    END
  END Y
  OBS
    LAYER met1 ;
      RECT 1.435 0.46 1.665 3.38 ;
      RECT 1.435 2.29 2.84 2.52 ;
      RECT 2.61 1.805 2.84 2.52 ;
      RECT 0.145 0.46 0.375 3.38 ;
  END
  PROPERTY CatenaDesignType "deviceLevel" ;
  PROPERTY oaTaper "virtuosoDefaultSetup" ;
END MX2X1_HS

MACRO MX2X4_HS
  CLASS CORE ;
  ORIGIN 0 0 ;
  FOREIGN MX2X4_HS 0 0 ;
  SIZE 4.6 BY 4.14 ;
  SYMMETRY X Y ;
  SITE CoreSite ;
  PIN A
    DIRECTION INPUT ;
    USE SIGNAL ;
    ANTENNAMODEL OXIDE1 ;
      ANTENNAGATEAREA 0.2775 LAYER met1 ;
      ANTENNAMAXAREACAR 0.324685 LAYER met1 ;
      ANTENNAMAXSIDEAREACAR 0.381982 LAYER met1 ;
    PORT
      LAYER met1 ;
        RECT 0.79 0.98 1.05 2.22 ;
    END
  END A
  PIN B
    DIRECTION INPUT ;
    USE SIGNAL ;
    ANTENNAMODEL OXIDE1 ;
      ANTENNAGATEAREA 0.2775 LAYER met1 ;
      ANTENNAMAXAREACAR 0.897477 LAYER met1 ;
      ANTENNAMAXSIDEAREACAR 1.055856 LAYER met1 ;
    PORT
      LAYER met1 ;
        RECT 3.09 1.06 3.35 2.3 ;
    END
  END B
  PIN S0
    DIRECTION INPUT ;
    USE SIGNAL ;
    ANTENNAMODEL OXIDE1 ;
      ANTENNAGATEAREA 0.45825 LAYER met1 ;
      ANTENNAMAXAREACAR 0.727483 LAYER met1 ;
      ANTENNAMAXSIDEAREACAR 0.741953 LAYER met1 ;
    PORT
      LAYER met1 ;
        RECT 1.25 1.405 1.51 2.645 ;
    END
  END S0
  PIN VDD
    DIRECTION INPUT ;
    USE POWER ;
    SHAPE ABUTMENT ;
    NETEXPR "VDD VDD!" ;
    PORT
      LAYER met1 ;
        RECT 0 3.94 4.6 4.34 ;
    END
  END VDD
  PIN VSS
    DIRECTION INPUT ;
    USE GROUND ;
    SHAPE ABUTMENT ;
    NETEXPR "VSS VSS!" ;
    PORT
      LAYER met1 ;
        RECT 0 -0.2 4.6 0.2 ;
    END
  END VSS
  PIN Y
    DIRECTION OUTPUT ;
    USE SIGNAL ;
    ANTENNADIFFAREA 1.2432 LAYER met1 ;
    PORT
      LAYER met1 ;
        RECT 2.845 3.235 4.27 3.525 ;
        RECT 4.01 0.61 4.27 3.525 ;
        RECT 2.845 0.415 4.14 0.705 ;
    END
  END Y
  OBS
    LAYER met1 ;
      RECT 1.495 3.025 2.235 3.315 ;
      RECT 2.005 0.83 2.235 3.315 ;
      RECT 2.005 1.835 2.47 2.065 ;
      RECT 1.495 0.83 2.235 1.06 ;
      RECT 1.495 0.51 1.725 1.06 ;
      RECT 0.145 0.51 0.375 3.235 ;
  END
  PROPERTY CatenaDesignType "deviceLevel" ;
END MX2X4_HS

MACRO MX4X1_HS
  CLASS CORE ;
  ORIGIN 0 0 ;
  FOREIGN MX4X1_HS 0 0 ;
  SIZE 7.36 BY 4.14 ;
  SYMMETRY X Y ;
  SITE CoreSite ;
  PIN A
    DIRECTION INPUT ;
    USE SIGNAL ;
    ANTENNAMODEL OXIDE1 ;
      ANTENNAGATEAREA 0.18075 LAYER met1 ;
      ANTENNAMAXAREACAR 0.681881 LAYER met1 ;
      ANTENNAMAXSIDEAREACAR 0.802213 LAYER met1 ;
    PORT
      LAYER met1 ;
        RECT 0.79 1.85 1.05 3.09 ;
    END
  END A
  PIN B
    DIRECTION INPUT ;
    USE SIGNAL ;
    ANTENNAMODEL OXIDE1 ;
      ANTENNAGATEAREA 0.18075 LAYER met1 ;
      ANTENNAMAXAREACAR 0.771231 LAYER met1 ;
      ANTENNAMAXSIDEAREACAR 0.907331 LAYER met1 ;
    PORT
      LAYER met1 ;
        RECT 2.17 2.435 2.43 3.675 ;
    END
  END B
  PIN C
    DIRECTION INPUT ;
    USE SIGNAL ;
    ANTENNAMODEL OXIDE1 ;
      ANTENNAGATEAREA 0.18075 LAYER met1 ;
      ANTENNAMAXAREACAR 0.775934 LAYER met1 ;
      ANTENNAMAXSIDEAREACAR 0.912863 LAYER met1 ;
    PORT
      LAYER met1 ;
        RECT 2.17 1.005 2.43 2.245 ;
    END
  END C
  PIN D
    DIRECTION INPUT ;
    USE SIGNAL ;
    ANTENNAMODEL OXIDE1 ;
      ANTENNAGATEAREA 0.18075 LAYER met1 ;
      ANTENNAMAXAREACAR 0.893499 LAYER met1 ;
      ANTENNAMAXSIDEAREACAR 1.051176 LAYER met1 ;
    PORT
      LAYER met1 ;
        RECT 3.55 1.815 3.81 3.055 ;
    END
  END D
  PIN S0
    DIRECTION INPUT ;
    USE SIGNAL ;
    ANTENNAPARTIALMETALAREA 0.54275 LAYER met1 ;
    ANTENNAPARTIALMETALSIDEAREA 1.659 LAYER met1 ;
    ANTENNAMODEL OXIDE1 ;
      ANTENNAGATEAREA 0.54225 LAYER met1 ;
      ANTENNAMAXAREACAR 3.30162 LAYER met1 ;
      ANTENNAMAXSIDEAREACAR 5.7005 LAYER met1 ;
    PORT
      LAYER met1 ;
        RECT 2.725 0.95 2.955 2.815 ;
        RECT 1.25 1.15 1.51 3.065 ;
        RECT 1.265 0.955 1.495 3.065 ;
    END
  END S0
  PIN S1
    DIRECTION INPUT ;
    USE SIGNAL ;
    ANTENNAMODEL OXIDE1 ;
      ANTENNAGATEAREA 0.3615 LAYER met1 ;
      ANTENNAMAXAREACAR 0.418534 LAYER met1 ;
      ANTENNAMAXSIDEAREACAR 0.39834 LAYER met1 ;
    PORT
      LAYER met1 ;
        RECT 4.01 0.895 4.27 2.135 ;
    END
  END S1
  PIN VDD
    DIRECTION INPUT ;
    USE POWER ;
    SHAPE ABUTMENT ;
    NETEXPR "VDD VDD!" ;
    PORT
      LAYER met1 ;
        RECT 0 3.94 7.36 4.34 ;
    END
  END VDD
  PIN VSS
    DIRECTION INPUT ;
    USE GROUND ;
    SHAPE ABUTMENT ;
    NETEXPR "VSS VSS!" ;
    PORT
      LAYER met1 ;
        RECT 0 -0.2 7.36 0.2 ;
    END
  END VSS
  PIN Y
    DIRECTION OUTPUT ;
    USE SIGNAL ;
    ANTENNADIFFAREA 0.5883 LAYER met1 ;
    PORT
      LAYER met1 ;
        RECT 6.77 0.68 7.03 3.45 ;
        RECT 6.775 0.485 7.005 3.45 ;
    END
  END Y
  OBS
    LAYER met1 ;
      RECT 3.155 3.375 6.055 3.605 ;
      RECT 5.825 0.485 6.055 3.605 ;
      RECT 3.155 0.51 3.385 3.605 ;
      RECT 1.435 3.24 1.88 3.53 ;
      RECT 1.65 0.395 1.88 3.53 ;
      RECT 1.435 0.395 1.88 0.8 ;
      RECT 5.395 0.485 5.625 3.235 ;
      RECT 4.965 0.485 5.195 3.235 ;
      RECT 4.445 0.51 4.675 3.235 ;
      RECT 0.145 0.51 0.375 3.235 ;
  END
  PROPERTY CatenaDesignType "deviceLevel" ;
END MX4X1_HS

MACRO MX4X4_HS
  CLASS CORE ;
  ORIGIN 0 0 ;
  FOREIGN MX4X4_HS 0 0 ;
  SIZE 8.74 BY 4.14 ;
  SYMMETRY X Y ;
  SITE CoreSite ;
  PIN A
    DIRECTION INPUT ;
    USE SIGNAL ;
    ANTENNAMODEL OXIDE1 ;
      ANTENNAGATEAREA 0.18075 LAYER met1 ;
      ANTENNAMAXAREACAR 0.686584 LAYER met1 ;
      ANTENNAMAXSIDEAREACAR 0.807746 LAYER met1 ;
    PORT
      LAYER met1 ;
        RECT 0.79 1.655 1.05 2.895 ;
    END
  END A
  PIN B
    DIRECTION INPUT ;
    USE SIGNAL ;
    ANTENNAMODEL OXIDE1 ;
      ANTENNAGATEAREA 0.18075 LAYER met1 ;
      ANTENNAMAXAREACAR 0.771231 LAYER met1 ;
      ANTENNAMAXSIDEAREACAR 0.907331 LAYER met1 ;
    PORT
      LAYER met1 ;
        RECT 2.17 2.195 2.43 3.435 ;
    END
  END B
  PIN C
    DIRECTION INPUT ;
    USE SIGNAL ;
    ANTENNAMODEL OXIDE1 ;
      ANTENNAGATEAREA 0.18075 LAYER met1 ;
      ANTENNAMAXAREACAR 0.757123 LAYER met1 ;
      ANTENNAMAXSIDEAREACAR 0.890733 LAYER met1 ;
    PORT
      LAYER met1 ;
        RECT 2.19 0.71 2.45 1.95 ;
    END
  END C
  PIN D
    DIRECTION INPUT ;
    USE SIGNAL ;
    ANTENNAMODEL OXIDE1 ;
      ANTENNAGATEAREA 0.18075 LAYER met1 ;
      ANTENNAMAXAREACAR 0.893499 LAYER met1 ;
      ANTENNAMAXSIDEAREACAR 1.051176 LAYER met1 ;
    PORT
      LAYER met1 ;
        RECT 3.55 1.995 3.81 3.235 ;
    END
  END D
  PIN S0
    DIRECTION INPUT ;
    USE SIGNAL ;
    ANTENNAPARTIALMETALAREA 0.4849 LAYER met1 ;
    ANTENNAPARTIALMETALSIDEAREA 1.4875 LAYER met1 ;
    ANTENNAMODEL OXIDE1 ;
      ANTENNAGATEAREA 0.54225 LAYER met1 ;
      ANTENNAMAXAREACAR 3.189582 LAYER met1 ;
      ANTENNAMAXSIDEAREACAR 5.384225 LAYER met1 ;
    PORT
      LAYER met1 ;
        RECT 2.725 0.95 2.955 2.62 ;
        RECT 1.25 0.95 1.51 2.815 ;
    END
  END S0
  PIN S1
    DIRECTION INPUT ;
    USE SIGNAL ;
    ANTENNAMODEL OXIDE1 ;
      ANTENNAGATEAREA 0.51375 LAYER met1 ;
      ANTENNAMAXAREACAR 0.292847 LAYER met1 ;
      ANTENNAMAXSIDEAREACAR 0.278345 LAYER met1 ;
    PORT
      LAYER met1 ;
        RECT 4.01 0.73 4.27 1.97 ;
    END
  END S1
  PIN VDD
    DIRECTION INPUT ;
    USE POWER ;
    SHAPE ABUTMENT ;
    NETEXPR "VDD VDD!" ;
    PORT
      LAYER met1 ;
        RECT 0 3.94 8.74 4.34 ;
    END
  END VDD
  PIN VSS
    DIRECTION INPUT ;
    USE GROUND ;
    SHAPE ABUTMENT ;
    NETEXPR "VSS VSS!" ;
    PORT
      LAYER met1 ;
        RECT 0 -0.2 8.74 0.2 ;
    END
  END VSS
  PIN Y
    DIRECTION OUTPUT ;
    USE SIGNAL ;
    ANTENNADIFFAREA 1.2432 LAYER met1 ;
    PORT
      LAYER met1 ;
        RECT 7.635 0.485 7.95 3.255 ;
        RECT 6.775 1.575 7.95 1.805 ;
        RECT 6.775 0.485 7.005 3.255 ;
    END
  END Y
  OBS
    LAYER met1 ;
      RECT 3.155 3.375 6.055 3.605 ;
      RECT 5.825 0.485 6.055 3.605 ;
      RECT 3.155 0.51 3.385 3.605 ;
      RECT 1.435 3.045 1.88 3.335 ;
      RECT 1.65 0.415 1.88 3.335 ;
      RECT 1.435 0.415 1.88 0.705 ;
      RECT 5.395 0.485 5.625 3.04 ;
      RECT 4.965 0.485 5.195 3.04 ;
      RECT 4.445 0.51 4.675 3.04 ;
      RECT 0.145 0.51 0.375 3.325 ;
  END
  PROPERTY CatenaDesignType "deviceLevel" ;
END MX4X4_HS

MACRO NAND2X1_HS
  CLASS CORE ;
  ORIGIN 0 0 ;
  FOREIGN NAND2X1_HS 0 0 ;
  SIZE 1.84 BY 4.14 ;
  SYMMETRY X Y ;
  SITE CoreSite ;
  PIN A
    DIRECTION INPUT ;
    USE SIGNAL ;
    ANTENNAMODEL OXIDE1 ;
      ANTENNAGATEAREA 0.333 LAYER met1 ;
      ANTENNAMAXAREACAR 0.365015 LAYER met1 ;
      ANTENNAMAXSIDEAREACAR 0.429429 LAYER met1 ;
    PORT
      LAYER met1 ;
        RECT 0.33 1.29 0.59 2.53 ;
        RECT 0.345 1.285 0.575 2.53 ;
    END
  END A
  PIN B
    DIRECTION INPUT ;
    USE SIGNAL ;
    ANTENNAMODEL OXIDE1 ;
      ANTENNAGATEAREA 0.333 LAYER met1 ;
      ANTENNAMAXAREACAR 0.372673 LAYER met1 ;
      ANTENNAMAXSIDEAREACAR 0.438438 LAYER met1 ;
    PORT
      LAYER met1 ;
        RECT 0.79 1.19 1.05 2.43 ;
    END
  END B
  PIN VDD
    DIRECTION INPUT ;
    USE POWER ;
    SHAPE ABUTMENT ;
    NETEXPR "VDD VDD!" ;
    PORT
      LAYER met1 ;
        RECT 0 3.94 1.84 4.34 ;
    END
  END VDD
  PIN VSS
    DIRECTION INPUT ;
    USE GROUND ;
    SHAPE ABUTMENT ;
    NETEXPR "VSS VSS!" ;
    PORT
      LAYER met1 ;
        RECT 0 -0.2 1.84 0.2 ;
    END
  END VSS
  PIN Y
    DIRECTION OUTPUT ;
    USE SIGNAL ;
    ANTENNADIFFAREA 0.6102 LAYER met1 ;
    PORT
      LAYER met1 ;
        RECT 0.575 3.21 1.51 3.47 ;
        RECT 1.25 0.655 1.51 3.47 ;
        RECT 0.965 0.655 1.51 0.915 ;
        RECT 0.965 0.475 1.235 0.915 ;
        RECT 0.975 0.46 1.235 0.915 ;
        RECT 0.575 2.82 0.805 3.47 ;
    END
  END Y
  PROPERTY CatenaDesignType "deviceLevel" ;
END NAND2X1_HS

MACRO NAND2X2_HS
  CLASS CORE ;
  ORIGIN 0 0 ;
  FOREIGN NAND2X2_HS 0 0 ;
  SIZE 2.3 BY 4.14 ;
  SYMMETRY X Y ;
  SITE CoreSite ;
  PIN A
    DIRECTION INPUT ;
    USE SIGNAL ;
    ANTENNAMODEL OXIDE1 ;
      ANTENNAGATEAREA 0.666 LAYER met1 ;
      ANTENNAMAXAREACAR 0.31524 LAYER met1 ;
      ANTENNAMAXSIDEAREACAR 0.31982 LAYER met1 ;
    PORT
      LAYER met1 ;
        RECT 0.33 1.29 0.59 2.53 ;
        RECT 0.345 1.285 0.575 2.53 ;
    END
  END A
  PIN B
    DIRECTION INPUT ;
    USE SIGNAL ;
    ANTENNAMODEL OXIDE1 ;
      ANTENNAGATEAREA 0.666 LAYER met1 ;
      ANTENNAMAXAREACAR 0.376502 LAYER met1 ;
      ANTENNAMAXSIDEAREACAR 0.391892 LAYER met1 ;
    PORT
      LAYER met1 ;
        RECT 0.79 1.76 1.05 3 ;
        RECT 0.805 1.755 1.035 3 ;
    END
  END B
  PIN VDD
    DIRECTION INPUT ;
    USE POWER ;
    SHAPE ABUTMENT ;
    NETEXPR "VDD VDD!" ;
    PORT
      LAYER met1 ;
        RECT 0 3.94 2.3 4.34 ;
    END
  END VDD
  PIN VSS
    DIRECTION INPUT ;
    USE GROUND ;
    SHAPE ABUTMENT ;
    NETEXPR "VSS VSS!" ;
    PORT
      LAYER met1 ;
        RECT 0 -0.2 2.3 0.2 ;
    END
  END VSS
  PIN Y
    DIRECTION OUTPUT ;
    USE SIGNAL ;
    ANTENNADIFFAREA 1.0304 LAYER met1 ;
    PORT
      LAYER met1 ;
        RECT 0.575 3.18 1.665 3.47 ;
        RECT 1.25 2.46 1.665 3.47 ;
        RECT 1.25 0.845 1.665 1.135 ;
        RECT 1.25 0.845 1.51 3.47 ;
    END
  END Y
  OBS
    LAYER met1 ;
      RECT 0.115 0.395 2.095 0.625 ;
      RECT 0.115 0.425 2.125 0.595 ;
  END
  PROPERTY CatenaDesignType "deviceLevel" ;
END NAND2X2_HS

MACRO NAND2X4_HS
  CLASS CORE ;
  ORIGIN 0 0 ;
  FOREIGN NAND2X4_HS 0 0 ;
  SIZE 4.14 BY 4.14 ;
  SYMMETRY X Y ;
  SITE CoreSite ;
  PIN A
    DIRECTION INPUT ;
    USE SIGNAL ;
    ANTENNAMODEL OXIDE1 ;
      ANTENNAGATEAREA 1.332 LAYER met1 ;
      ANTENNAMAXAREACAR 0.216967 LAYER met1 ;
      ANTENNAMAXSIDEAREACAR 0.204204 LAYER met1 ;
    PORT
      LAYER met1 ;
        RECT 0.79 1.36 1.05 2.6 ;
    END
  END A
  PIN B
    DIRECTION INPUT ;
    USE SIGNAL ;
    ANTENNAMODEL OXIDE1 ;
      ANTENNAGATEAREA 1.332 LAYER met1 ;
      ANTENNAMAXAREACAR 0.216967 LAYER met1 ;
      ANTENNAMAXSIDEAREACAR 0.204204 LAYER met1 ;
    PORT
      LAYER met1 ;
        RECT 2.63 1.44 2.89 2.68 ;
    END
  END B
  PIN VDD
    DIRECTION INPUT ;
    USE POWER ;
    SHAPE ABUTMENT ;
    NETEXPR "VDD VDD!" ;
    PORT
      LAYER met1 ;
        RECT 0 3.94 4.14 4.34 ;
    END
  END VDD
  PIN VSS
    DIRECTION INPUT ;
    USE GROUND ;
    SHAPE ABUTMENT ;
    NETEXPR "VSS VSS!" ;
    PORT
      LAYER met1 ;
        RECT 0 -0.2 4.14 0.2 ;
    END
  END VSS
  PIN Y
    DIRECTION OUTPUT ;
    USE SIGNAL ;
    ANTENNADIFFAREA 2.0608 LAYER met1 ;
    PORT
      LAYER met1 ;
        RECT 0.575 3.24 3.415 3.53 ;
        RECT 3.09 1.07 3.415 3.53 ;
        RECT 2.265 1.07 3.415 1.3 ;
    END
  END Y
  OBS
    LAYER met1 ;
      RECT 0.145 0.615 3.845 0.905 ;
  END
END NAND2X4_HS

MACRO NAND3X1_HS
  CLASS CORE ;
  ORIGIN 0 0 ;
  FOREIGN NAND3X1_HS 0 0 ;
  SIZE 2.3 BY 4.14 ;
  SYMMETRY X Y ;
  SITE CoreSite ;
  PIN A
    DIRECTION INPUT ;
    USE SIGNAL ;
    ANTENNAMODEL OXIDE1 ;
      ANTENNAGATEAREA 0.333 LAYER met1 ;
      ANTENNAMAXAREACAR 0.35991 LAYER met1 ;
      ANTENNAMAXSIDEAREACAR 0.423423 LAYER met1 ;
    PORT
      LAYER met1 ;
        RECT 0.33 1.165 0.59 2.405 ;
    END
  END A
  PIN B
    DIRECTION INPUT ;
    USE SIGNAL ;
    ANTENNAMODEL OXIDE1 ;
      ANTENNAGATEAREA 0.333 LAYER met1 ;
      ANTENNAMAXAREACAR 0.262913 LAYER met1 ;
      ANTENNAMAXSIDEAREACAR 0.309309 LAYER met1 ;
    PORT
      LAYER met1 ;
        RECT 0.79 1.685 1.05 2.925 ;
    END
  END B
  PIN C
    DIRECTION INPUT ;
    USE SIGNAL ;
    ANTENNAMODEL OXIDE1 ;
      ANTENNAGATEAREA 0.333 LAYER met1 ;
      ANTENNAMAXAREACAR 0.395646 LAYER met1 ;
      ANTENNAMAXSIDEAREACAR 0.465465 LAYER met1 ;
    PORT
      LAYER met1 ;
        RECT 1.25 1.47 1.51 2.71 ;
        RECT 1.265 1.285 1.495 2.71 ;
    END
  END C
  PIN VDD
    DIRECTION INPUT ;
    USE POWER ;
    SHAPE ABUTMENT ;
    NETEXPR "VDD VDD!" ;
    PORT
      LAYER met1 ;
        RECT 0 3.94 2.3 4.34 ;
    END
  END VDD
  PIN VSS
    DIRECTION INPUT ;
    USE GROUND ;
    SHAPE ABUTMENT ;
    NETEXPR "VSS VSS!" ;
    PORT
      LAYER met1 ;
        RECT 0 -0.2 2.3 0.2 ;
    END
  END VSS
  PIN Y
    DIRECTION OUTPUT ;
    USE SIGNAL ;
    ANTENNADIFFAREA 0.9971 LAYER met1 ;
    PORT
      LAYER met1 ;
        RECT 0.575 3.16 1.97 3.45 ;
        RECT 1.71 0.61 1.97 3.45 ;
        RECT 1.535 0.61 1.97 0.9 ;
        RECT 1.435 0.415 1.665 0.705 ;
    END
  END Y
  PROPERTY CatenaDesignType "deviceLevel" ;
END NAND3X1_HS

MACRO NAND3X2_HS
  CLASS CORE ;
  ORIGIN 0 0 ;
  FOREIGN NAND3X2_HS 0 0 ;
  SIZE 3.68 BY 4.14 ;
  SYMMETRY X Y ;
  SITE CoreSite ;
  PIN A
    DIRECTION INPUT ;
    USE SIGNAL ;
    ANTENNAMODEL OXIDE1 ;
      ANTENNAGATEAREA 0.666 LAYER met1 ;
      ANTENNAMAXAREACAR 0.336937 LAYER met1 ;
      ANTENNAMAXSIDEAREACAR 0.345345 LAYER met1 ;
    PORT
      LAYER met1 ;
        RECT 0.33 1.65 0.59 2.89 ;
    END
  END A
  PIN B
    DIRECTION INPUT ;
    USE SIGNAL ;
    ANTENNAMODEL OXIDE1 ;
      ANTENNAGATEAREA 0.666 LAYER met1 ;
      ANTENNAMAXAREACAR 0.321622 LAYER met1 ;
      ANTENNAMAXSIDEAREACAR 0.327327 LAYER met1 ;
    PORT
      LAYER met1 ;
        RECT 1.25 1.65 1.51 2.89 ;
    END
  END B
  PIN C
    DIRECTION INPUT ;
    USE SIGNAL ;
    ANTENNAMODEL OXIDE1 ;
      ANTENNAGATEAREA 0.666 LAYER met1 ;
      ANTENNAMAXAREACAR 0.363739 LAYER met1 ;
      ANTENNAMAXSIDEAREACAR 0.376877 LAYER met1 ;
    PORT
      LAYER met1 ;
        RECT 2.17 1.53 2.43 2.77 ;
        RECT 2.185 1.52 2.415 2.77 ;
    END
  END C
  PIN VDD
    DIRECTION INPUT ;
    USE POWER ;
    SHAPE ABUTMENT ;
    NETEXPR "VDD VDD!" ;
    PORT
      LAYER met1 ;
        RECT 0 3.94 3.68 4.34 ;
    END
  END VDD
  PIN VSS
    DIRECTION INPUT ;
    USE GROUND ;
    SHAPE ABUTMENT ;
    NETEXPR "VSS VSS!" ;
    PORT
      LAYER met1 ;
        RECT 0 -0.2 3.68 0.2 ;
    END
  END VSS
  PIN Y
    DIRECTION OUTPUT ;
    USE SIGNAL ;
    ANTENNADIFFAREA 1.4392 LAYER met1 ;
    PORT
      LAYER met1 ;
        RECT 0.545 3.27 3.045 3.5 ;
        RECT 2.63 2.49 3.045 3.5 ;
        RECT 2.63 0.83 3.045 1.12 ;
        RECT 2.63 0.83 2.89 3.5 ;
    END
  END Y
  OBS
    LAYER met1 ;
      RECT 1.405 0.445 3.505 0.675 ;
      RECT 0.115 0.83 2.125 1.06 ;
  END
  PROPERTY CatenaDesignType "deviceLevel" ;
END NAND3X2_HS

MACRO NAND3X4_HS
  CLASS CORE ;
  ORIGIN 0 0 ;
  FOREIGN NAND3X4_HS 0 0 ;
  SIZE 6.44 BY 4.14 ;
  SYMMETRY X Y ;
  SITE CoreSite ;
  PIN A
    DIRECTION INPUT ;
    USE SIGNAL ;
    ANTENNAMODEL OXIDE1 ;
      ANTENNAGATEAREA 1.332 LAYER met1 ;
      ANTENNAMAXAREACAR 0.216967 LAYER met1 ;
      ANTENNAMAXSIDEAREACAR 0.204204 LAYER met1 ;
    PORT
      LAYER met1 ;
        RECT 0.79 1.48 1.05 2.72 ;
    END
  END A
  PIN B
    DIRECTION INPUT ;
    USE SIGNAL ;
    ANTENNAMODEL OXIDE1 ;
      ANTENNAGATEAREA 1.332 LAYER met1 ;
      ANTENNAMAXAREACAR 0.216967 LAYER met1 ;
      ANTENNAMAXSIDEAREACAR 0.204204 LAYER met1 ;
    PORT
      LAYER met1 ;
        RECT 2.63 1.44 2.89 2.68 ;
    END
  END B
  PIN C
    DIRECTION INPUT ;
    USE SIGNAL ;
    ANTENNAMODEL OXIDE1 ;
      ANTENNAGATEAREA 1.332 LAYER met1 ;
      ANTENNAMAXAREACAR 0.216967 LAYER met1 ;
      ANTENNAMAXSIDEAREACAR 0.204204 LAYER met1 ;
    PORT
      LAYER met1 ;
        RECT 4.93 1.44 5.19 2.68 ;
    END
  END C
  PIN VDD
    DIRECTION INPUT ;
    USE POWER ;
    SHAPE ABUTMENT ;
    NETEXPR "VDD VDD!" ;
    PORT
      LAYER met1 ;
        RECT 0 3.94 6.44 4.34 ;
    END
  END VDD
  PIN VSS
    DIRECTION INPUT ;
    USE GROUND ;
    SHAPE ABUTMENT ;
    NETEXPR "VSS VSS!" ;
    PORT
      LAYER met1 ;
        RECT 0 -0.2 6.44 0.2 ;
    END
  END VSS
  PIN Y
    DIRECTION OUTPUT ;
    USE SIGNAL ;
    ANTENNADIFFAREA 3.0684 LAYER met1 ;
    PORT
      LAYER met1 ;
        RECT 0.575 3.24 6.11 3.53 ;
        RECT 5.85 0.65 6.11 3.53 ;
        RECT 4.075 1.07 6.11 1.3 ;
        RECT 5.825 0.65 6.11 1.3 ;
        RECT 4.075 1.07 4.305 3.53 ;
    END
  END Y
  OBS
    LAYER met1 ;
      RECT 0.145 1.07 3.845 1.3 ;
      RECT 1.865 0.65 2.095 1.3 ;
      RECT 1.005 0.65 1.235 1.3 ;
      RECT 0.145 0.65 0.375 1.3 ;
      RECT 2.265 0.64 5.655 0.87 ;
  END
END NAND3X4_HS

MACRO NAND4X1_HS
  CLASS CORE ;
  ORIGIN 0 0 ;
  FOREIGN NAND4X1_HS 0 0 ;
  SIZE 2.76 BY 4.14 ;
  SYMMETRY X Y ;
  SITE CoreSite ;
  PIN A
    DIRECTION INPUT ;
    USE SIGNAL ;
    ANTENNAMODEL OXIDE1 ;
      ANTENNAGATEAREA 0.333 LAYER met1 ;
      ANTENNAMAXAREACAR 0.37012 LAYER met1 ;
      ANTENNAMAXSIDEAREACAR 0.435435 LAYER met1 ;
    PORT
      LAYER met1 ;
        RECT 0.33 1.49 0.59 2.73 ;
    END
  END A
  PIN B
    DIRECTION INPUT ;
    USE SIGNAL ;
    ANTENNAMODEL OXIDE1 ;
      ANTENNAGATEAREA 0.333 LAYER met1 ;
      ANTENNAMAXAREACAR 0.372673 LAYER met1 ;
      ANTENNAMAXSIDEAREACAR 0.438438 LAYER met1 ;
    PORT
      LAYER met1 ;
        RECT 0.79 0.97 1.05 2.21 ;
    END
  END B
  PIN C
    DIRECTION INPUT ;
    USE SIGNAL ;
    ANTENNAMODEL OXIDE1 ;
      ANTENNAGATEAREA 0.333 LAYER met1 ;
      ANTENNAMAXAREACAR 0.387988 LAYER met1 ;
      ANTENNAMAXSIDEAREACAR 0.456456 LAYER met1 ;
    PORT
      LAYER met1 ;
        RECT 1.25 1.49 1.51 2.73 ;
    END
  END C
  PIN D
    DIRECTION INPUT ;
    USE SIGNAL ;
    ANTENNAMODEL OXIDE1 ;
      ANTENNAGATEAREA 0.333 LAYER met1 ;
      ANTENNAMAXAREACAR 0.403303 LAYER met1 ;
      ANTENNAMAXSIDEAREACAR 0.474474 LAYER met1 ;
    PORT
      LAYER met1 ;
        RECT 1.71 0.97 1.97 2.21 ;
    END
  END D
  PIN VDD
    DIRECTION INPUT ;
    USE POWER ;
    SHAPE ABUTMENT ;
    NETEXPR "VDD VDD!" ;
    PORT
      LAYER met1 ;
        RECT 0 3.94 2.76 4.34 ;
    END
  END VDD
  PIN VSS
    DIRECTION INPUT ;
    USE GROUND ;
    SHAPE ABUTMENT ;
    NETEXPR "VSS VSS!" ;
    PORT
      LAYER met1 ;
        RECT 0 -0.2 2.76 0.2 ;
    END
  END VSS
  PIN Y
    DIRECTION OUTPUT ;
    USE SIGNAL ;
    ANTENNADIFFAREA 1.019 LAYER met1 ;
    PORT
      LAYER met1 ;
        RECT 0.575 3.035 2.43 3.325 ;
        RECT 2.17 0.415 2.43 3.325 ;
        RECT 1.865 0.415 2.43 0.705 ;
        RECT 1.435 3.035 1.665 3.335 ;
    END
  END Y
  PROPERTY CatenaDesignType "deviceLevel" ;
END NAND4X1_HS

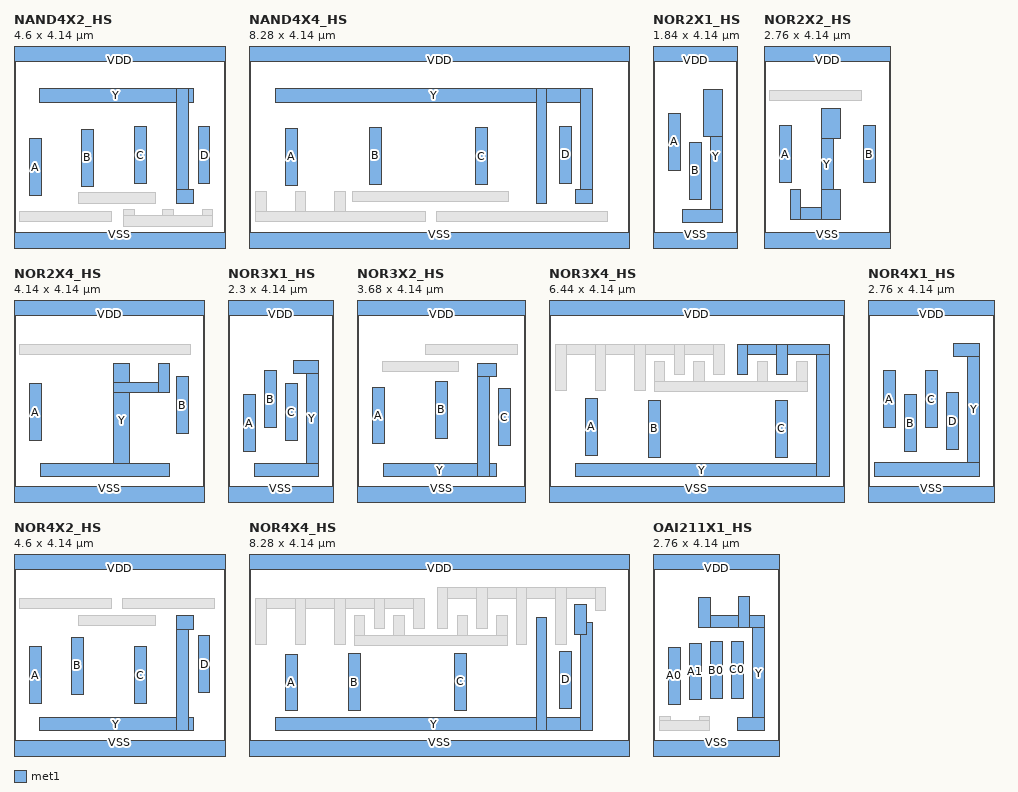
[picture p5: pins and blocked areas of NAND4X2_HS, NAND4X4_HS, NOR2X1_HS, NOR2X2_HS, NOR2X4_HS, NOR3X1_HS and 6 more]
MACRO NAND4X2_HS
  CLASS CORE ;
  ORIGIN 0 0 ;
  FOREIGN NAND4X2_HS 0 0 ;
  SIZE 4.6 BY 4.14 ;
  SYMMETRY X Y ;
  SITE CoreSite ;
  PIN A
    DIRECTION INPUT ;
    USE SIGNAL ;
    ANTENNAMODEL OXIDE1 ;
      ANTENNAGATEAREA 0.666 LAYER met1 ;
      ANTENNAMAXAREACAR 0.274399 LAYER met1 ;
      ANTENNAMAXSIDEAREACAR 0.271772 LAYER met1 ;
    PORT
      LAYER met1 ;
        RECT 0.33 1.01 0.59 2.25 ;
    END
  END A
  PIN B
    DIRECTION INPUT ;
    USE SIGNAL ;
    ANTENNAMODEL OXIDE1 ;
      ANTENNAGATEAREA 0.666 LAYER met1 ;
      ANTENNAMAXAREACAR 0.26036 LAYER met1 ;
      ANTENNAMAXSIDEAREACAR 0.255255 LAYER met1 ;
    PORT
      LAYER met1 ;
        RECT 1.48 1.22 1.74 2.46 ;
    END
  END B
  PIN C
    DIRECTION INPUT ;
    USE SIGNAL ;
    ANTENNAMODEL OXIDE1 ;
      ANTENNAGATEAREA 0.666 LAYER met1 ;
      ANTENNAMAXAREACAR 0.26036 LAYER met1 ;
      ANTENNAMAXSIDEAREACAR 0.255255 LAYER met1 ;
    PORT
      LAYER met1 ;
        RECT 2.63 1.275 2.89 2.515 ;
    END
  END C
  PIN D
    DIRECTION INPUT ;
    USE SIGNAL ;
    ANTENNAMODEL OXIDE1 ;
      ANTENNAGATEAREA 0.666 LAYER met1 ;
      ANTENNAMAXAREACAR 0.28461 LAYER met1 ;
      ANTENNAMAXSIDEAREACAR 0.334835 LAYER met1 ;
    PORT
      LAYER met1 ;
        RECT 4.01 1.275 4.27 2.515 ;
    END
  END D
  PIN VDD
    DIRECTION INPUT ;
    USE POWER ;
    SHAPE ABUTMENT ;
    NETEXPR "VDD VDD!" ;
    PORT
      LAYER met1 ;
        RECT 0 3.94 4.6 4.34 ;
    END
  END VDD
  PIN VSS
    DIRECTION INPUT ;
    USE GROUND ;
    SHAPE ABUTMENT ;
    NETEXPR "VSS VSS!" ;
    PORT
      LAYER met1 ;
        RECT 0 -0.2 4.6 0.2 ;
    END
  END VSS
  PIN Y
    DIRECTION OUTPUT ;
    USE SIGNAL ;
    ANTENNADIFFAREA 1.848 LAYER met1 ;
    PORT
      LAYER met1 ;
        RECT 0.545 3.045 3.905 3.335 ;
        RECT 3.55 0.845 3.905 1.135 ;
        RECT 3.55 0.845 3.81 3.335 ;
    END
  END Y
  OBS
    LAYER met1 ;
      RECT 4.105 0.34 4.335 0.705 ;
      RECT 3.245 0.34 3.475 0.705 ;
      RECT 2.385 0.34 2.615 0.705 ;
      RECT 2.385 0.34 4.335 0.57 ;
      RECT 1.405 0.845 3.075 1.075 ;
      RECT 0.115 0.445 2.125 0.675 ;
  END
  PROPERTY CatenaDesignType "deviceLevel" ;
END NAND4X2_HS

MACRO NAND4X4_HS
  CLASS CORE ;
  ORIGIN 0 0 ;
  FOREIGN NAND4X4_HS 0 0 ;
  SIZE 8.28 BY 4.14 ;
  SYMMETRY X Y ;
  SITE CoreSite ;
  PIN A
    DIRECTION INPUT ;
    USE SIGNAL ;
    ANTENNAMODEL OXIDE1 ;
      ANTENNAGATEAREA 1.332 LAYER met1 ;
      ANTENNAMAXAREACAR 0.216967 LAYER met1 ;
      ANTENNAMAXSIDEAREACAR 0.204204 LAYER met1 ;
    PORT
      LAYER met1 ;
        RECT 0.79 1.235 1.05 2.475 ;
    END
  END A
  PIN B
    DIRECTION INPUT ;
    USE SIGNAL ;
    ANTENNAMODEL OXIDE1 ;
      ANTENNAGATEAREA 1.332 LAYER met1 ;
      ANTENNAMAXAREACAR 0.216967 LAYER met1 ;
      ANTENNAMAXSIDEAREACAR 0.204204 LAYER met1 ;
    PORT
      LAYER met1 ;
        RECT 2.63 1.255 2.89 2.495 ;
    END
  END B
  PIN C
    DIRECTION INPUT ;
    USE SIGNAL ;
    ANTENNAMODEL OXIDE1 ;
      ANTENNAGATEAREA 1.332 LAYER met1 ;
      ANTENNAMAXAREACAR 0.216967 LAYER met1 ;
      ANTENNAMAXSIDEAREACAR 0.204204 LAYER met1 ;
    PORT
      LAYER met1 ;
        RECT 4.93 1.245 5.19 2.485 ;
    END
  END C
  PIN D
    DIRECTION INPUT ;
    USE SIGNAL ;
    ANTENNAMODEL OXIDE1 ;
      ANTENNAGATEAREA 1.332 LAYER met1 ;
      ANTENNAMAXAREACAR 0.216967 LAYER met1 ;
      ANTENNAMAXSIDEAREACAR 0.204204 LAYER met1 ;
    PORT
      LAYER met1 ;
        RECT 6.77 1.28 7.03 2.52 ;
    END
  END D
  PIN VDD
    DIRECTION INPUT ;
    USE POWER ;
    SHAPE ABUTMENT ;
    NETEXPR "VDD VDD!" ;
    PORT
      LAYER met1 ;
        RECT 0 3.94 8.28 4.34 ;
    END
  END VDD
  PIN VSS
    DIRECTION INPUT ;
    USE GROUND ;
    SHAPE ABUTMENT ;
    NETEXPR "VSS VSS!" ;
    PORT
      LAYER met1 ;
        RECT 0 -0.2 8.28 0.2 ;
    END
  END VSS
  PIN Y
    DIRECTION OUTPUT ;
    USE SIGNAL ;
    ANTENNADIFFAREA 3.696 LAYER met1 ;
    PORT
      LAYER met1 ;
        RECT 0.575 3.045 7.49 3.335 ;
        RECT 7.23 0.845 7.49 3.335 ;
        RECT 7.115 0.845 7.49 1.135 ;
        RECT 6.255 0.845 6.485 3.335 ;
    END
  END Y
  OBS
    LAYER met1 ;
      RECT 1.865 0.445 2.095 1.095 ;
      RECT 1.005 0.445 1.235 1.095 ;
      RECT 0.145 0.445 0.375 1.095 ;
      RECT 0.145 0.445 3.845 0.675 ;
      RECT 4.075 0.445 7.805 0.675 ;
      RECT 2.265 0.875 5.655 1.105 ;
  END
END NAND4X4_HS

MACRO NOR2X1_HS
  CLASS CORE ;
  ORIGIN 0 0 ;
  FOREIGN NOR2X1_HS 0 0 ;
  SIZE 1.84 BY 4.14 ;
  SYMMETRY X Y ;
  SITE CoreSite ;
  PIN A
    DIRECTION INPUT ;
    USE SIGNAL ;
    ANTENNAMODEL OXIDE1 ;
      ANTENNAGATEAREA 0.333 LAYER met1 ;
      ANTENNAMAXAREACAR 0.283333 LAYER met1 ;
      ANTENNAMAXSIDEAREACAR 0.333333 LAYER met1 ;
    PORT
      LAYER met1 ;
        RECT 0.33 1.565 0.59 2.805 ;
    END
  END A
  PIN B
    DIRECTION INPUT ;
    USE SIGNAL ;
    ANTENNAMODEL OXIDE1 ;
      ANTENNAGATEAREA 0.333 LAYER met1 ;
      ANTENNAMAXAREACAR 0.293544 LAYER met1 ;
      ANTENNAMAXSIDEAREACAR 0.345345 LAYER met1 ;
    PORT
      LAYER met1 ;
        RECT 0.79 0.93 1.05 2.17 ;
    END
  END B
  PIN VDD
    DIRECTION INPUT ;
    USE POWER ;
    SHAPE ABUTMENT ;
    NETEXPR "VDD VDD!" ;
    PORT
      LAYER met1 ;
        RECT 0 3.94 1.84 4.34 ;
    END
  END VDD
  PIN VSS
    DIRECTION INPUT ;
    USE GROUND ;
    SHAPE ABUTMENT ;
    NETEXPR "VSS VSS!" ;
    PORT
      LAYER met1 ;
        RECT 0 -0.2 1.84 0.2 ;
    END
  END VSS
  PIN Y
    DIRECTION OUTPUT ;
    USE SIGNAL ;
    ANTENNADIFFAREA 0.6885 LAYER met1 ;
    PORT
      LAYER met1 ;
        RECT 1.105 2.305 1.51 3.315 ;
        RECT 1.25 0.425 1.51 3.315 ;
        RECT 0.635 0.425 1.51 0.715 ;
    END
  END Y
  PROPERTY CatenaDesignType "deviceLevel" ;
END NOR2X1_HS

MACRO NOR2X2_HS
  CLASS CORE ;
  ORIGIN 0 0 ;
  FOREIGN NOR2X2_HS 0 0 ;
  SIZE 2.76 BY 4.14 ;
  SYMMETRY X Y ;
  SITE CoreSite ;
  PIN A
    DIRECTION INPUT ;
    USE SIGNAL ;
    ANTENNAMODEL OXIDE1 ;
      ANTENNAGATEAREA 0.666 LAYER met1 ;
      ANTENNAMAXAREACAR 0.274399 LAYER met1 ;
      ANTENNAMAXSIDEAREACAR 0.271772 LAYER met1 ;
    PORT
      LAYER met1 ;
        RECT 0.33 1.295 0.59 2.535 ;
    END
  END A
  PIN B
    DIRECTION INPUT ;
    USE SIGNAL ;
    ANTENNAMODEL OXIDE1 ;
      ANTENNAGATEAREA 0.666 LAYER met1 ;
      ANTENNAMAXAREACAR 0.407132 LAYER met1 ;
      ANTENNAMAXSIDEAREACAR 0.427928 LAYER met1 ;
    PORT
      LAYER met1 ;
        RECT 2.17 1.295 2.43 2.535 ;
    END
  END B
  PIN VDD
    DIRECTION INPUT ;
    USE POWER ;
    SHAPE ABUTMENT ;
    NETEXPR "VDD VDD!" ;
    PORT
      LAYER met1 ;
        RECT 0 3.94 2.76 4.34 ;
    END
  END VDD
  PIN VSS
    DIRECTION INPUT ;
    USE GROUND ;
    SHAPE ABUTMENT ;
    NETEXPR "VSS VSS!" ;
    PORT
      LAYER met1 ;
        RECT 0 -0.2 2.76 0.2 ;
    END
  END VSS
  PIN Y
    DIRECTION OUTPUT ;
    USE SIGNAL ;
    ANTENNADIFFAREA 0.8344 LAYER met1 ;
    PORT
      LAYER met1 ;
        RECT 1.25 2.25 1.665 2.9 ;
        RECT 1.25 0.485 1.665 1.135 ;
        RECT 1.25 0.485 1.51 2.9 ;
        RECT 0.575 0.485 1.665 0.745 ;
        RECT 0.575 0.485 0.805 1.135 ;
    END
  END Y
  OBS
    LAYER met1 ;
      RECT 0.11 3.075 2.125 3.305 ;
  END
  PROPERTY CatenaDesignType "deviceLevel" ;
END NOR2X2_HS

MACRO NOR2X4_HS
  CLASS CORE ;
  ORIGIN 0 0 ;
  FOREIGN NOR2X4_HS 0 0 ;
  SIZE 4.14 BY 4.14 ;
  SYMMETRY X Y ;
  SITE CoreSite ;
  PIN A
    DIRECTION INPUT ;
    USE SIGNAL ;
    ANTENNAMODEL OXIDE1 ;
      ANTENNAGATEAREA 1.332 LAYER met1 ;
      ANTENNAMAXAREACAR 0.292905 LAYER met1 ;
      ANTENNAMAXSIDEAREACAR 0.268018 LAYER met1 ;
    PORT
      LAYER met1 ;
        RECT 0.33 1.21 0.59 2.45 ;
    END
  END A
  PIN B
    DIRECTION INPUT ;
    USE SIGNAL ;
    ANTENNAMODEL OXIDE1 ;
      ANTENNAGATEAREA 1.332 LAYER met1 ;
      ANTENNAMAXAREACAR 0.315878 LAYER met1 ;
      ANTENNAMAXSIDEAREACAR 0.295045 LAYER met1 ;
    PORT
      LAYER met1 ;
        RECT 3.55 1.36 3.81 2.6 ;
    END
  END B
  PIN VDD
    DIRECTION INPUT ;
    USE POWER ;
    SHAPE ABUTMENT ;
    NETEXPR "VDD VDD!" ;
    PORT
      LAYER met1 ;
        RECT 0 3.94 4.14 4.34 ;
    END
  END VDD
  PIN VSS
    DIRECTION INPUT ;
    USE GROUND ;
    SHAPE ABUTMENT ;
    NETEXPR "VSS VSS!" ;
    PORT
      LAYER met1 ;
        RECT 0 -0.2 4.14 0.2 ;
    END
  END VSS
  PIN Y
    DIRECTION OUTPUT ;
    USE SIGNAL ;
    ANTENNADIFFAREA 1.6688 LAYER met1 ;
    PORT
      LAYER met1 ;
        RECT 3.155 2.245 3.385 2.895 ;
        RECT 0.575 0.415 3.385 0.705 ;
        RECT 2.17 2.245 3.385 2.475 ;
        RECT 2.17 0.415 2.525 2.895 ;
    END
  END Y
  OBS
    LAYER met1 ;
      RECT 0.115 3.075 3.845 3.305 ;
  END
  PROPERTY CatenaDesignType "deviceLevel" ;
END NOR2X4_HS

MACRO NOR3X1_HS
  CLASS CORE ;
  ORIGIN 0 0 ;
  FOREIGN NOR3X1_HS 0 0 ;
  SIZE 2.3 BY 4.14 ;
  SYMMETRY X Y ;
  SITE CoreSite ;
  PIN A
    DIRECTION INPUT ;
    USE SIGNAL ;
    ANTENNAMODEL OXIDE1 ;
      ANTENNAGATEAREA 0.333 LAYER met1 ;
      ANTENNAMAXAREACAR 0.37012 LAYER met1 ;
      ANTENNAMAXSIDEAREACAR 0.435435 LAYER met1 ;
    PORT
      LAYER met1 ;
        RECT 0.33 0.97 0.59 2.21 ;
    END
  END A
  PIN B
    DIRECTION INPUT ;
    USE SIGNAL ;
    ANTENNAMODEL OXIDE1 ;
      ANTENNAGATEAREA 0.333 LAYER met1 ;
      ANTENNAMAXAREACAR 0.372673 LAYER met1 ;
      ANTENNAMAXSIDEAREACAR 0.438438 LAYER met1 ;
    PORT
      LAYER met1 ;
        RECT 0.79 1.49 1.05 2.73 ;
    END
  END B
  PIN C
    DIRECTION INPUT ;
    USE SIGNAL ;
    ANTENNAMODEL OXIDE1 ;
      ANTENNAGATEAREA 0.333 LAYER met1 ;
      ANTENNAMAXAREACAR 0.387988 LAYER met1 ;
      ANTENNAMAXSIDEAREACAR 0.456456 LAYER met1 ;
    PORT
      LAYER met1 ;
        RECT 1.25 1.205 1.51 2.445 ;
    END
  END C
  PIN VDD
    DIRECTION INPUT ;
    USE POWER ;
    SHAPE ABUTMENT ;
    NETEXPR "VDD VDD!" ;
    PORT
      LAYER met1 ;
        RECT 0 3.94 2.3 4.34 ;
    END
  END VDD
  PIN VSS
    DIRECTION INPUT ;
    USE GROUND ;
    SHAPE ABUTMENT ;
    NETEXPR "VSS VSS!" ;
    PORT
      LAYER met1 ;
        RECT 0 -0.2 2.3 0.2 ;
    END
  END VSS
  PIN Y
    DIRECTION OUTPUT ;
    USE SIGNAL ;
    ANTENNADIFFAREA 0.8011 LAYER met1 ;
    PORT
      LAYER met1 ;
        RECT 1.435 2.67 1.97 2.96 ;
        RECT 1.71 0.415 1.97 2.96 ;
        RECT 0.575 0.415 1.97 0.705 ;
    END
  END Y
  PROPERTY CatenaDesignType "deviceLevel" ;
END NOR3X1_HS

MACRO NOR3X2_HS
  CLASS CORE ;
  ORIGIN 0 0 ;
  FOREIGN NOR3X2_HS 0 0 ;
  SIZE 3.68 BY 4.14 ;
  SYMMETRY X Y ;
  SITE CoreSite ;
  PIN A
    DIRECTION INPUT ;
    USE SIGNAL ;
    ANTENNAMODEL OXIDE1 ;
      ANTENNAGATEAREA 0.666 LAYER met1 ;
      ANTENNAMAXAREACAR 0.336937 LAYER met1 ;
      ANTENNAMAXSIDEAREACAR 0.345345 LAYER met1 ;
    PORT
      LAYER met1 ;
        RECT 0.33 1.135 0.59 2.375 ;
    END
  END A
  PIN B
    DIRECTION INPUT ;
    USE SIGNAL ;
    ANTENNAMODEL OXIDE1 ;
      ANTENNAGATEAREA 0.666 LAYER met1 ;
      ANTENNAMAXAREACAR 0.336937 LAYER met1 ;
      ANTENNAMAXSIDEAREACAR 0.345345 LAYER met1 ;
    PORT
      LAYER met1 ;
        RECT 1.71 1.26 1.97 2.5 ;
    END
  END B
  PIN C
    DIRECTION INPUT ;
    USE SIGNAL ;
    ANTENNAMODEL OXIDE1 ;
      ANTENNAGATEAREA 0.666 LAYER met1 ;
      ANTENNAMAXAREACAR 0.276952 LAYER met1 ;
      ANTENNAMAXSIDEAREACAR 0.274775 LAYER met1 ;
    PORT
      LAYER met1 ;
        RECT 3.09 1.1 3.35 2.34 ;
    END
  END C
  PIN VDD
    DIRECTION INPUT ;
    USE POWER ;
    SHAPE ABUTMENT ;
    NETEXPR "VDD VDD!" ;
    PORT
      LAYER met1 ;
        RECT 0 3.94 3.68 4.34 ;
    END
  END VDD
  PIN VSS
    DIRECTION INPUT ;
    USE GROUND ;
    SHAPE ABUTMENT ;
    NETEXPR "VSS VSS!" ;
    PORT
      LAYER met1 ;
        RECT 0 -0.2 3.68 0.2 ;
    END
  END VSS
  PIN Y
    DIRECTION OUTPUT ;
    USE SIGNAL ;
    ANTENNADIFFAREA 1.0472 LAYER met1 ;
    PORT
      LAYER met1 ;
        RECT 2.63 2.605 3.045 2.895 ;
        RECT 0.575 0.415 3.045 0.705 ;
        RECT 2.63 0.415 2.89 2.895 ;
    END
  END Y
  OBS
    LAYER met1 ;
      RECT 1.495 3.075 3.505 3.305 ;
      RECT 0.545 2.705 2.215 2.935 ;
  END
  PROPERTY CatenaDesignType "deviceLevel" ;
END NOR3X2_HS

MACRO NOR3X4_HS
  CLASS CORE ;
  ORIGIN 0 0 ;
  FOREIGN NOR3X4_HS 0 0 ;
  SIZE 6.44 BY 4.14 ;
  SYMMETRY X Y ;
  SITE CoreSite ;
  PIN A
    DIRECTION INPUT ;
    USE SIGNAL ;
    ANTENNAMODEL OXIDE1 ;
      ANTENNAGATEAREA 1.332 LAYER met1 ;
      ANTENNAMAXAREACAR 0.216967 LAYER met1 ;
      ANTENNAMAXSIDEAREACAR 0.204204 LAYER met1 ;
    PORT
      LAYER met1 ;
        RECT 0.79 0.89 1.05 2.13 ;
    END
  END A
  PIN B
    DIRECTION INPUT ;
    USE SIGNAL ;
    ANTENNAMODEL OXIDE1 ;
      ANTENNAGATEAREA 1.332 LAYER met1 ;
      ANTENNAMAXAREACAR 0.230368 LAYER met1 ;
      ANTENNAMAXSIDEAREACAR 0.21997 LAYER met1 ;
    PORT
      LAYER met1 ;
        RECT 2.175 0.845 2.435 2.085 ;
    END
  END B
  PIN C
    DIRECTION INPUT ;
    USE SIGNAL ;
    ANTENNAMODEL OXIDE1 ;
      ANTENNAGATEAREA 1.332 LAYER met1 ;
      ANTENNAMAXAREACAR 0.216967 LAYER met1 ;
      ANTENNAMAXSIDEAREACAR 0.204204 LAYER met1 ;
    PORT
      LAYER met1 ;
        RECT 4.93 0.845 5.19 2.085 ;
    END
  END C
  PIN VDD
    DIRECTION INPUT ;
    USE POWER ;
    SHAPE ABUTMENT ;
    NETEXPR "VDD VDD!" ;
    PORT
      LAYER met1 ;
        RECT 0 3.94 6.44 4.34 ;
    END
  END VDD
  PIN VSS
    DIRECTION INPUT ;
    USE GROUND ;
    SHAPE ABUTMENT ;
    NETEXPR "VSS VSS!" ;
    PORT
      LAYER met1 ;
        RECT 0 -0.2 6.44 0.2 ;
    END
  END VSS
  PIN Y
    DIRECTION OUTPUT ;
    USE SIGNAL ;
    ANTENNADIFFAREA 2.4594 LAYER met1 ;
    PORT
      LAYER met1 ;
        RECT 4.105 3.075 6.11 3.305 ;
        RECT 5.825 0.415 6.11 3.305 ;
        RECT 0.575 0.415 6.11 0.705 ;
        RECT 4.965 2.655 5.195 3.305 ;
        RECT 4.105 2.655 4.335 3.305 ;
    END
  END Y
  OBS
    LAYER met1 ;
      RECT 5.395 2.275 5.625 2.925 ;
      RECT 4.535 2.275 4.765 2.925 ;
      RECT 3.155 2.275 3.385 2.925 ;
      RECT 2.295 2.275 2.525 2.925 ;
      RECT 2.295 2.275 5.625 2.505 ;
      RECT 0.145 3.075 3.815 3.305 ;
      RECT 3.585 2.655 3.815 3.305 ;
      RECT 2.725 2.655 2.955 3.305 ;
      RECT 1.865 2.295 2.095 3.305 ;
      RECT 1.005 2.295 1.235 3.305 ;
      RECT 0.145 2.295 0.375 3.305 ;
  END
END NOR3X4_HS

MACRO NOR4X1_HS
  CLASS CORE ;
  ORIGIN 0 0 ;
  FOREIGN NOR4X1_HS 0 0 ;
  SIZE 2.76 BY 4.14 ;
  SYMMETRY X Y ;
  SITE CoreSite ;
  PIN A
    DIRECTION INPUT ;
    USE SIGNAL ;
    ANTENNAMODEL OXIDE1 ;
      ANTENNAGATEAREA 0.333 LAYER met1 ;
      ANTENNAMAXAREACAR 0.37012 LAYER met1 ;
      ANTENNAMAXSIDEAREACAR 0.435435 LAYER met1 ;
    PORT
      LAYER met1 ;
        RECT 0.33 1.49 0.59 2.73 ;
    END
  END A
  PIN B
    DIRECTION INPUT ;
    USE SIGNAL ;
    ANTENNAMODEL OXIDE1 ;
      ANTENNAGATEAREA 0.333 LAYER met1 ;
      ANTENNAMAXAREACAR 0.372673 LAYER met1 ;
      ANTENNAMAXSIDEAREACAR 0.438438 LAYER met1 ;
    PORT
      LAYER met1 ;
        RECT 0.79 0.97 1.05 2.21 ;
    END
  END B
  PIN C
    DIRECTION INPUT ;
    USE SIGNAL ;
    ANTENNAMODEL OXIDE1 ;
      ANTENNAGATEAREA 0.333 LAYER met1 ;
      ANTENNAMAXAREACAR 0.387988 LAYER met1 ;
      ANTENNAMAXSIDEAREACAR 0.456456 LAYER met1 ;
    PORT
      LAYER met1 ;
        RECT 1.25 1.49 1.51 2.73 ;
    END
  END C
  PIN D
    DIRECTION INPUT ;
    USE SIGNAL ;
    ANTENNAMODEL OXIDE1 ;
      ANTENNAGATEAREA 0.333 LAYER met1 ;
      ANTENNAMAXAREACAR 0.403303 LAYER met1 ;
      ANTENNAMAXSIDEAREACAR 0.474474 LAYER met1 ;
    PORT
      LAYER met1 ;
        RECT 1.71 1.01 1.97 2.25 ;
    END
  END D
  PIN VDD
    DIRECTION INPUT ;
    USE POWER ;
    SHAPE ABUTMENT ;
    NETEXPR "VDD VDD!" ;
    PORT
      LAYER met1 ;
        RECT 0 3.94 2.76 4.34 ;
    END
  END VDD
  PIN VSS
    DIRECTION INPUT ;
    USE GROUND ;
    SHAPE ABUTMENT ;
    NETEXPR "VSS VSS!" ;
    PORT
      LAYER met1 ;
        RECT 0 -0.2 2.76 0.2 ;
    END
  END VSS
  PIN Y
    DIRECTION OUTPUT ;
    USE SIGNAL ;
    ANTENNADIFFAREA 1.0025 LAYER met1 ;
    PORT
      LAYER met1 ;
        RECT 1.865 3.04 2.43 3.33 ;
        RECT 2.17 0.43 2.43 3.33 ;
        RECT 0.145 0.43 2.43 0.72 ;
    END
  END Y
  PROPERTY CatenaDesignType "deviceLevel" ;
END NOR4X1_HS

MACRO NOR4X2_HS
  CLASS CORE ;
  ORIGIN 0 0 ;
  FOREIGN NOR4X2_HS 0 0 ;
  SIZE 4.6 BY 4.14 ;
  SYMMETRY X Y ;
  SITE CoreSite ;
  PIN A
    DIRECTION INPUT ;
    USE SIGNAL ;
    ANTENNAMODEL OXIDE1 ;
      ANTENNAGATEAREA 0.666 LAYER met1 ;
      ANTENNAMAXAREACAR 0.274399 LAYER met1 ;
      ANTENNAMAXSIDEAREACAR 0.271772 LAYER met1 ;
    PORT
      LAYER met1 ;
        RECT 0.33 1.01 0.59 2.25 ;
    END
  END A
  PIN B
    DIRECTION INPUT ;
    USE SIGNAL ;
    ANTENNAMODEL OXIDE1 ;
      ANTENNAGATEAREA 0.666 LAYER met1 ;
      ANTENNAMAXAREACAR 0.26036 LAYER met1 ;
      ANTENNAMAXSIDEAREACAR 0.255255 LAYER met1 ;
    PORT
      LAYER met1 ;
        RECT 1.25 1.22 1.51 2.46 ;
    END
  END B
  PIN C
    DIRECTION INPUT ;
    USE SIGNAL ;
    ANTENNAMODEL OXIDE1 ;
      ANTENNAGATEAREA 0.666 LAYER met1 ;
      ANTENNAMAXAREACAR 0.26036 LAYER met1 ;
      ANTENNAMAXSIDEAREACAR 0.255255 LAYER met1 ;
    PORT
      LAYER met1 ;
        RECT 2.63 1.01 2.89 2.25 ;
    END
  END C
  PIN D
    DIRECTION INPUT ;
    USE SIGNAL ;
    ANTENNAMODEL OXIDE1 ;
      ANTENNAGATEAREA 0.666 LAYER met1 ;
      ANTENNAMAXAREACAR 0.328003 LAYER met1 ;
      ANTENNAMAXSIDEAREACAR 0.334835 LAYER met1 ;
    PORT
      LAYER met1 ;
        RECT 4.01 1.245 4.27 2.485 ;
    END
  END D
  PIN VDD
    DIRECTION INPUT ;
    USE POWER ;
    SHAPE ABUTMENT ;
    NETEXPR "VDD VDD!" ;
    PORT
      LAYER met1 ;
        RECT 0 3.94 4.6 4.34 ;
    END
  END VDD
  PIN VSS
    DIRECTION INPUT ;
    USE GROUND ;
    SHAPE ABUTMENT ;
    NETEXPR "VSS VSS!" ;
    PORT
      LAYER met1 ;
        RECT 0 -0.2 4.6 0.2 ;
    END
  END VSS
  PIN Y
    DIRECTION OUTPUT ;
    USE SIGNAL ;
    ANTENNADIFFAREA 1.26 LAYER met1 ;
    PORT
      LAYER met1 ;
        RECT 3.55 2.635 3.905 2.925 ;
        RECT 0.545 0.415 3.905 0.705 ;
        RECT 3.55 0.415 3.81 2.925 ;
    END
  END Y
  OBS
    LAYER met1 ;
      RECT 2.355 3.075 4.365 3.305 ;
      RECT 1.405 2.705 3.075 2.935 ;
      RECT 0.115 3.075 2.125 3.305 ;
  END
  PROPERTY CatenaDesignType "deviceLevel" ;
END NOR4X2_HS

MACRO NOR4X4_HS
  CLASS CORE ;
  ORIGIN 0 0 ;
  FOREIGN NOR4X4_HS 0 0 ;
  SIZE 8.28 BY 4.14 ;
  SYMMETRY X Y ;
  SITE CoreSite ;
  PIN A
    DIRECTION INPUT ;
    USE SIGNAL ;
    ANTENNAMODEL OXIDE1 ;
      ANTENNAGATEAREA 1.332 LAYER met1 ;
      ANTENNAMAXAREACAR 0.216967 LAYER met1 ;
      ANTENNAMAXSIDEAREACAR 0.204204 LAYER met1 ;
    PORT
      LAYER met1 ;
        RECT 0.79 0.85 1.05 2.09 ;
    END
  END A
  PIN B
    DIRECTION INPUT ;
    USE SIGNAL ;
    ANTENNAMODEL OXIDE1 ;
      ANTENNAGATEAREA 1.332 LAYER met1 ;
      ANTENNAMAXAREACAR 0.230368 LAYER met1 ;
      ANTENNAMAXSIDEAREACAR 0.21997 LAYER met1 ;
    PORT
      LAYER met1 ;
        RECT 2.175 0.855 2.435 2.095 ;
    END
  END B
  PIN C
    DIRECTION INPUT ;
    USE SIGNAL ;
    ANTENNAMODEL OXIDE1 ;
      ANTENNAGATEAREA 1.332 LAYER met1 ;
      ANTENNAMAXAREACAR 0.223348 LAYER met1 ;
      ANTENNAMAXSIDEAREACAR 0.211712 LAYER met1 ;
    PORT
      LAYER met1 ;
        RECT 4.47 0.87 4.73 2.11 ;
    END
  END C
  PIN D
    DIRECTION INPUT ;
    USE SIGNAL ;
    ANTENNAMODEL OXIDE1 ;
      ANTENNAGATEAREA 1.332 LAYER met1 ;
      ANTENNAMAXAREACAR 0.216967 LAYER met1 ;
      ANTENNAMAXSIDEAREACAR 0.204204 LAYER met1 ;
    PORT
      LAYER met1 ;
        RECT 6.77 0.91 7.03 2.15 ;
    END
  END D
  PIN VDD
    DIRECTION INPUT ;
    USE POWER ;
    SHAPE ABUTMENT ;
    NETEXPR "VDD VDD!" ;
    PORT
      LAYER met1 ;
        RECT 0 3.94 8.28 4.34 ;
    END
  END VDD
  PIN VSS
    DIRECTION INPUT ;
    USE GROUND ;
    SHAPE ABUTMENT ;
    NETEXPR "VSS VSS!" ;
    PORT
      LAYER met1 ;
        RECT 0 -0.2 8.28 0.2 ;
    END
  END VSS
  PIN Y
    DIRECTION OUTPUT ;
    USE SIGNAL ;
    ANTENNADIFFAREA 2.52 LAYER met1 ;
    PORT
      LAYER met1 ;
        RECT 7.23 0.415 7.49 2.775 ;
        RECT 7.1 2.515 7.36 3.165 ;
        RECT 0.575 0.415 7.49 0.705 ;
        RECT 6.255 0.415 6.485 2.895 ;
    END
  END Y
  OBS
    LAYER met1 ;
      RECT 4.105 3.305 7.775 3.535 ;
      RECT 7.545 3.045 7.775 3.535 ;
      RECT 6.685 2.295 6.915 3.535 ;
      RECT 5.825 2.295 6.055 3.535 ;
      RECT 4.965 2.655 5.195 3.535 ;
      RECT 4.105 2.655 4.335 3.535 ;
      RECT 5.395 2.275 5.625 2.925 ;
      RECT 4.535 2.275 4.765 2.925 ;
      RECT 3.155 2.275 3.385 2.925 ;
      RECT 2.295 2.275 2.525 2.925 ;
      RECT 2.295 2.275 5.625 2.505 ;
      RECT 0.145 3.075 3.815 3.305 ;
      RECT 3.585 2.655 3.815 3.305 ;
      RECT 2.725 2.655 2.955 3.305 ;
      RECT 1.865 2.295 2.095 3.305 ;
      RECT 1.005 2.295 1.235 3.305 ;
      RECT 0.145 2.295 0.375 3.305 ;
  END
END NOR4X4_HS

MACRO OAI211X1_HS
  CLASS CORE ;
  ORIGIN 0 0 ;
  FOREIGN OAI211X1_HS 0 0 ;
  SIZE 2.76 BY 4.14 ;
  SYMMETRY X Y ;
  SITE CoreSite ;
  PIN A0
    DIRECTION INPUT ;
    USE SIGNAL ;
    ANTENNAMODEL OXIDE1 ;
      ANTENNAGATEAREA 0.333 LAYER met1 ;
      ANTENNAMAXAREACAR 0.262913 LAYER met1 ;
      ANTENNAMAXSIDEAREACAR 0.309309 LAYER met1 ;
    PORT
      LAYER met1 ;
        RECT 0.33 0.995 0.59 2.235 ;
    END
  END A0
  PIN A1
    DIRECTION INPUT ;
    USE SIGNAL ;
    ANTENNAMODEL OXIDE1 ;
      ANTENNAGATEAREA 0.333 LAYER met1 ;
      ANTENNAMAXAREACAR 0.290991 LAYER met1 ;
      ANTENNAMAXSIDEAREACAR 0.342342 LAYER met1 ;
    PORT
      LAYER met1 ;
        RECT 0.79 1.09 1.05 2.33 ;
    END
  END A1
  PIN B0
    DIRECTION INPUT ;
    USE SIGNAL ;
    ANTENNAMODEL OXIDE1 ;
      ANTENNAGATEAREA 0.333 LAYER met1 ;
      ANTENNAMAXAREACAR 0.306306 LAYER met1 ;
      ANTENNAMAXSIDEAREACAR 0.36036 LAYER met1 ;
    PORT
      LAYER met1 ;
        RECT 1.25 1.115 1.51 2.355 ;
    END
  END B0
  PIN C0
    DIRECTION INPUT ;
    USE SIGNAL ;
    ANTENNAMODEL OXIDE1 ;
      ANTENNAGATEAREA 0.333 LAYER met1 ;
      ANTENNAMAXAREACAR 0.303754 LAYER met1 ;
      ANTENNAMAXSIDEAREACAR 0.357357 LAYER met1 ;
    PORT
      LAYER met1 ;
        RECT 1.71 1.125 1.97 2.365 ;
    END
  END C0
  PIN VDD
    DIRECTION INPUT ;
    USE POWER ;
    SHAPE ABUTMENT ;
    NETEXPR "VDD VDD!" ;
    PORT
      LAYER met1 ;
        RECT 0 3.94 2.76 4.34 ;
    END
  END VDD
  PIN VSS
    DIRECTION INPUT ;
    USE GROUND ;
    SHAPE ABUTMENT ;
    NETEXPR "VSS VSS!" ;
    PORT
      LAYER met1 ;
        RECT 0 -0.2 2.76 0.2 ;
    END
  END VSS
  PIN Y
    DIRECTION OUTPUT ;
    USE SIGNAL ;
    ANTENNADIFFAREA 0.9971 LAYER met1 ;
    PORT
      LAYER met1 ;
        RECT 0.99 2.67 2.43 2.93 ;
        RECT 2.17 0.415 2.43 2.93 ;
        RECT 1.85 0.415 2.43 0.71 ;
        RECT 1.865 2.67 2.095 3.335 ;
        RECT 0.99 2.67 1.25 3.32 ;
    END
  END Y
  OBS
    LAYER met1 ;
      RECT 1.005 0.415 1.235 0.74 ;
      RECT 0.145 0.415 0.375 0.74 ;
      RECT 0.145 0.415 1.235 0.645 ;
  END
  PROPERTY CatenaDesignType "deviceLevel" ;
END OAI211X1_HS

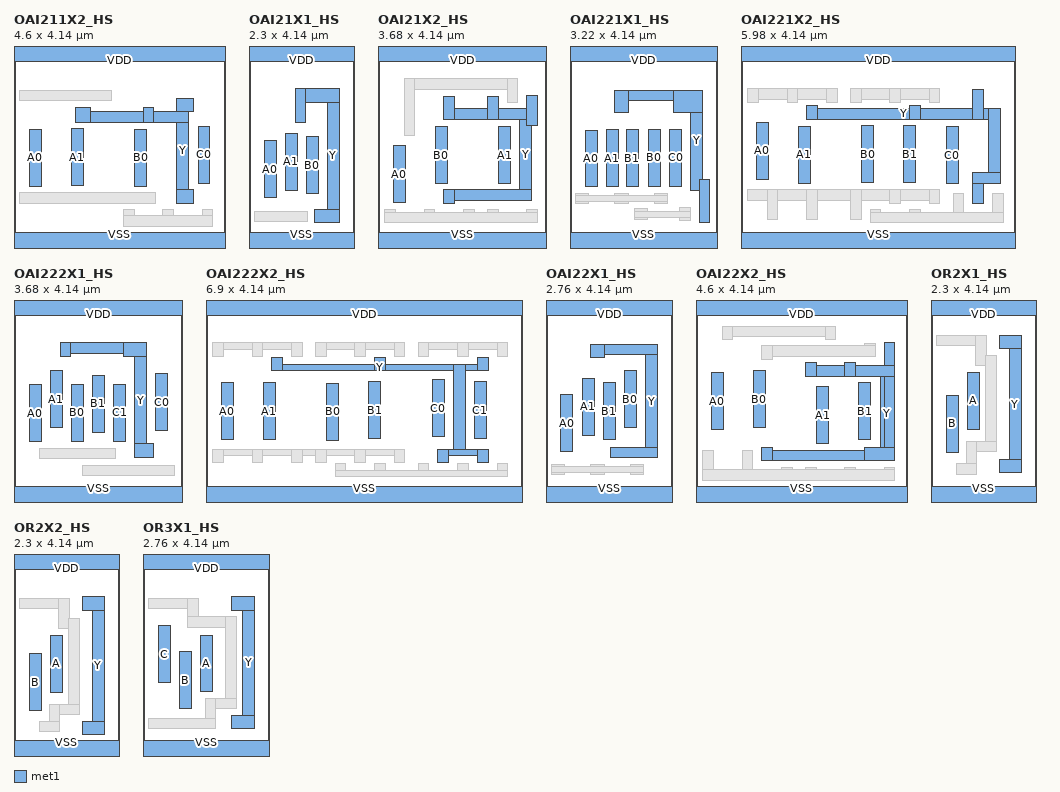
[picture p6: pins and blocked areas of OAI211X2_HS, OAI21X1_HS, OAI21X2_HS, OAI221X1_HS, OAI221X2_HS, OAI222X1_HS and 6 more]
MACRO OAI211X2_HS
  CLASS CORE ;
  ORIGIN 0 0 ;
  FOREIGN OAI211X2_HS 0 0 ;
  SIZE 4.6 BY 4.14 ;
  SYMMETRY X Y ;
  SITE CoreSite ;
  PIN A0
    DIRECTION INPUT ;
    USE SIGNAL ;
    ANTENNAMODEL OXIDE1 ;
      ANTENNAGATEAREA 0.666 LAYER met1 ;
      ANTENNAMAXAREACAR 0.274399 LAYER met1 ;
      ANTENNAMAXSIDEAREACAR 0.271772 LAYER met1 ;
    PORT
      LAYER met1 ;
        RECT 0.33 1.22 0.59 2.46 ;
    END
  END A0
  PIN A1
    DIRECTION INPUT ;
    USE SIGNAL ;
    ANTENNAMODEL OXIDE1 ;
      ANTENNAGATEAREA 0.666 LAYER met1 ;
      ANTENNAMAXAREACAR 0.26036 LAYER met1 ;
      ANTENNAMAXSIDEAREACAR 0.255255 LAYER met1 ;
    PORT
      LAYER met1 ;
        RECT 1.25 1.225 1.51 2.465 ;
    END
  END A1
  PIN B0
    DIRECTION INPUT ;
    USE SIGNAL ;
    ANTENNAMODEL OXIDE1 ;
      ANTENNAGATEAREA 0.666 LAYER met1 ;
      ANTENNAMAXAREACAR 0.26036 LAYER met1 ;
      ANTENNAMAXSIDEAREACAR 0.255255 LAYER met1 ;
    PORT
      LAYER met1 ;
        RECT 2.63 1.215 2.89 2.455 ;
    END
  END B0
  PIN C0
    DIRECTION INPUT ;
    USE SIGNAL ;
    ANTENNAMODEL OXIDE1 ;
      ANTENNAGATEAREA 0.666 LAYER met1 ;
      ANTENNAMAXAREACAR 0.328003 LAYER met1 ;
      ANTENNAMAXSIDEAREACAR 0.334835 LAYER met1 ;
    PORT
      LAYER met1 ;
        RECT 4.01 1.285 4.27 2.525 ;
    END
  END C0
  PIN VDD
    DIRECTION INPUT ;
    USE POWER ;
    SHAPE ABUTMENT ;
    NETEXPR "VDD VDD!" ;
    PORT
      LAYER met1 ;
        RECT 0 3.94 4.6 4.34 ;
    END
  END VDD
  PIN VSS
    DIRECTION INPUT ;
    USE GROUND ;
    SHAPE ABUTMENT ;
    NETEXPR "VSS VSS!" ;
    PORT
      LAYER met1 ;
        RECT 0 -0.2 4.6 0.2 ;
    END
  END VSS
  PIN Y
    DIRECTION OUTPUT ;
    USE SIGNAL ;
    ANTENNADIFFAREA 1.4392 LAYER met1 ;
    PORT
      LAYER met1 ;
        RECT 3.55 2.84 3.905 3.13 ;
        RECT 3.55 0.845 3.905 1.135 ;
        RECT 1.34 2.61 3.81 2.84 ;
        RECT 3.55 0.845 3.81 3.13 ;
        RECT 2.815 2.61 3.045 2.935 ;
        RECT 1.34 2.61 1.665 2.935 ;
    END
  END Y
  OBS
    LAYER met1 ;
      RECT 4.105 0.34 4.335 0.705 ;
      RECT 3.245 0.34 3.475 0.705 ;
      RECT 2.385 0.34 2.615 0.705 ;
      RECT 2.385 0.34 4.335 0.57 ;
      RECT 0.115 0.845 3.075 1.075 ;
      RECT 0.115 3.075 2.125 3.305 ;
  END
  PROPERTY CatenaDesignType "deviceLevel" ;
END OAI211X2_HS

MACRO OAI21X1_HS
  CLASS CORE ;
  ORIGIN 0 0 ;
  FOREIGN OAI21X1_HS 0 0 ;
  SIZE 2.3 BY 4.14 ;
  SYMMETRY X Y ;
  SITE CoreSite ;
  PIN A0
    DIRECTION INPUT ;
    USE SIGNAL ;
    ANTENNAMODEL OXIDE1 ;
      ANTENNAGATEAREA 0.333 LAYER met1 ;
      ANTENNAMAXAREACAR 0.37012 LAYER met1 ;
      ANTENNAMAXSIDEAREACAR 0.435435 LAYER met1 ;
    PORT
      LAYER met1 ;
        RECT 0.33 0.97 0.59 2.21 ;
    END
  END A0
  PIN A1
    DIRECTION INPUT ;
    USE SIGNAL ;
    ANTENNAMODEL OXIDE1 ;
      ANTENNAGATEAREA 0.333 LAYER met1 ;
      ANTENNAMAXAREACAR 0.37012 LAYER met1 ;
      ANTENNAMAXSIDEAREACAR 0.435435 LAYER met1 ;
    PORT
      LAYER met1 ;
        RECT 0.79 1.13 1.05 2.37 ;
    END
  END A1
  PIN B0
    DIRECTION INPUT ;
    USE SIGNAL ;
    ANTENNAMODEL OXIDE1 ;
      ANTENNAGATEAREA 0.333 LAYER met1 ;
      ANTENNAMAXAREACAR 0.387988 LAYER met1 ;
      ANTENNAMAXSIDEAREACAR 0.456456 LAYER met1 ;
    PORT
      LAYER met1 ;
        RECT 1.25 1.05 1.51 2.29 ;
    END
  END B0
  PIN VDD
    DIRECTION INPUT ;
    USE POWER ;
    SHAPE ABUTMENT ;
    NETEXPR "VDD VDD!" ;
    PORT
      LAYER met1 ;
        RECT 0 3.94 2.3 4.34 ;
    END
  END VDD
  PIN VSS
    DIRECTION INPUT ;
    USE GROUND ;
    SHAPE ABUTMENT ;
    NETEXPR "VSS VSS!" ;
    PORT
      LAYER met1 ;
        RECT 0 -0.2 2.3 0.2 ;
    END
  END VSS
  PIN Y
    DIRECTION OUTPUT ;
    USE SIGNAL ;
    ANTENNADIFFAREA 0.6102 LAYER met1 ;
    PORT
      LAYER met1 ;
        RECT 1.005 3.045 1.97 3.335 ;
        RECT 1.71 0.415 1.97 3.335 ;
        RECT 1.435 0.415 1.97 0.705 ;
        RECT 1.005 2.6 1.235 3.335 ;
    END
  END Y
  OBS
    LAYER met1 ;
      RECT 0.115 0.445 1.265 0.675 ;
  END
  PROPERTY CatenaDesignType "deviceLevel" ;
END OAI21X1_HS

MACRO OAI21X2_HS
  CLASS CORE ;
  ORIGIN 0 0 ;
  FOREIGN OAI21X2_HS 0 0 ;
  SIZE 3.68 BY 4.14 ;
  SYMMETRY X Y ;
  SITE CoreSite ;
  PIN A0
    DIRECTION INPUT ;
    USE SIGNAL ;
    ANTENNAMODEL OXIDE1 ;
      ANTENNAGATEAREA 0.666 LAYER met1 ;
      ANTENNAMAXAREACAR 0.274399 LAYER met1 ;
      ANTENNAMAXSIDEAREACAR 0.271772 LAYER met1 ;
    PORT
      LAYER met1 ;
        RECT 0.33 0.86 0.59 2.1 ;
    END
  END A0
  PIN A1
    DIRECTION INPUT ;
    USE SIGNAL ;
    ANTENNAMODEL OXIDE1 ;
      ANTENNAGATEAREA 0.666 LAYER met1 ;
      ANTENNAMAXAREACAR 0.26036 LAYER met1 ;
      ANTENNAMAXSIDEAREACAR 0.255255 LAYER met1 ;
    PORT
      LAYER met1 ;
        RECT 2.63 1.275 2.89 2.515 ;
    END
  END A1
  PIN B0
    DIRECTION INPUT ;
    USE SIGNAL ;
    ANTENNAMODEL OXIDE1 ;
      ANTENNAGATEAREA 0.666 LAYER met1 ;
      ANTENNAMAXAREACAR 0.26036 LAYER met1 ;
      ANTENNAMAXSIDEAREACAR 0.255255 LAYER met1 ;
    PORT
      LAYER met1 ;
        RECT 1.25 1.275 1.51 2.515 ;
    END
  END B0
  PIN VDD
    DIRECTION INPUT ;
    USE POWER ;
    SHAPE ABUTMENT ;
    NETEXPR "VDD VDD!" ;
    PORT
      LAYER met1 ;
        RECT 0 3.94 3.68 4.34 ;
    END
  END VDD
  PIN VSS
    DIRECTION INPUT ;
    USE GROUND ;
    SHAPE ABUTMENT ;
    NETEXPR "VSS VSS!" ;
    PORT
      LAYER met1 ;
        RECT 0 -0.2 3.68 0.2 ;
    END
  END VSS
  PIN Y
    DIRECTION OUTPUT ;
    USE SIGNAL ;
    ANTENNADIFFAREA 1.3954 LAYER met1 ;
    PORT
      LAYER met1 ;
        RECT 3.245 2.535 3.475 3.185 ;
        RECT 3.09 0.905 3.35 2.905 ;
        RECT 1.435 2.675 3.475 2.905 ;
        RECT 1.435 0.905 3.35 1.135 ;
        RECT 2.385 2.675 2.615 3.17 ;
        RECT 1.435 2.675 1.665 3.17 ;
        RECT 1.435 0.845 1.665 1.135 ;
    END
  END Y
  OBS
    LAYER met1 ;
      RECT 3.245 0.415 3.475 0.705 ;
      RECT 2.385 0.415 2.615 0.705 ;
      RECT 1.865 0.415 2.095 0.705 ;
      RECT 1.005 0.415 1.235 0.705 ;
      RECT 0.145 0.415 0.375 0.705 ;
      RECT 0.145 0.415 3.475 0.645 ;
      RECT 0.575 3.325 3.045 3.555 ;
      RECT 2.815 3.045 3.045 3.555 ;
      RECT 0.575 2.325 0.805 3.555 ;
  END
  PROPERTY CatenaDesignType "deviceLevel" ;
END OAI21X2_HS

MACRO OAI221X1_HS
  CLASS CORE ;
  ORIGIN 0 0 ;
  FOREIGN OAI221X1_HS 0 0 ;
  SIZE 3.22 BY 4.14 ;
  SYMMETRY X Y ;
  SITE CoreSite ;
  PIN A0
    DIRECTION INPUT ;
    USE SIGNAL ;
    ANTENNAMODEL OXIDE1 ;
      ANTENNAGATEAREA 0.333 LAYER met1 ;
      ANTENNAMAXAREACAR 0.298649 LAYER met1 ;
      ANTENNAMAXSIDEAREACAR 0.351351 LAYER met1 ;
    PORT
      LAYER met1 ;
        RECT 0.33 1.2 0.59 2.44 ;
    END
  END A0
  PIN A1
    DIRECTION INPUT ;
    USE SIGNAL ;
    ANTENNAMODEL OXIDE1 ;
      ANTENNAGATEAREA 0.333 LAYER met1 ;
      ANTENNAMAXAREACAR 0.311411 LAYER met1 ;
      ANTENNAMAXSIDEAREACAR 0.366366 LAYER met1 ;
    PORT
      LAYER met1 ;
        RECT 0.79 1.205 1.05 2.445 ;
    END
  END A1
  PIN B0
    DIRECTION INPUT ;
    USE SIGNAL ;
    ANTENNAMODEL OXIDE1 ;
      ANTENNAGATEAREA 0.333 LAYER met1 ;
      ANTENNAMAXAREACAR 0.316517 LAYER met1 ;
      ANTENNAMAXSIDEAREACAR 0.372372 LAYER met1 ;
    PORT
      LAYER met1 ;
        RECT 1.71 1.22 1.97 2.46 ;
    END
  END B0
  PIN B1
    DIRECTION INPUT ;
    USE SIGNAL ;
    ANTENNAMODEL OXIDE1 ;
      ANTENNAGATEAREA 0.333 LAYER met1 ;
      ANTENNAMAXAREACAR 0.268018 LAYER met1 ;
      ANTENNAMAXSIDEAREACAR 0.315315 LAYER met1 ;
    PORT
      LAYER met1 ;
        RECT 1.225 1.21 1.485 2.45 ;
    END
  END B1
  PIN C0
    DIRECTION INPUT ;
    USE SIGNAL ;
    ANTENNAMODEL OXIDE1 ;
      ANTENNAGATEAREA 0.333 LAYER met1 ;
      ANTENNAMAXAREACAR 0.313964 LAYER met1 ;
      ANTENNAMAXSIDEAREACAR 0.369369 LAYER met1 ;
    PORT
      LAYER met1 ;
        RECT 2.17 1.22 2.43 2.46 ;
    END
  END C0
  PIN VDD
    DIRECTION INPUT ;
    USE POWER ;
    SHAPE ABUTMENT ;
    NETEXPR "VDD VDD!" ;
    PORT
      LAYER met1 ;
        RECT 0 3.94 3.22 4.34 ;
    END
  END VDD
  PIN VSS
    DIRECTION INPUT ;
    USE GROUND ;
    SHAPE ABUTMENT ;
    NETEXPR "VSS VSS!" ;
    PORT
      LAYER met1 ;
        RECT 0 -0.2 3.22 0.2 ;
    END
  END VSS
  PIN Y
    DIRECTION OUTPUT ;
    USE SIGNAL ;
    ANTENNADIFFAREA 0.9971 LAYER met1 ;
    PORT
      LAYER met1 ;
        RECT 2.815 0.415 3.045 1.36 ;
        RECT 0.975 3.075 2.89 3.305 ;
        RECT 2.265 2.83 2.89 3.305 ;
        RECT 2.63 1.13 2.89 3.305 ;
        RECT 0.975 2.83 1.265 3.305 ;
    END
  END Y
  OBS
    LAYER met1 ;
      RECT 2.385 0.46 2.615 0.75 ;
      RECT 1.405 0.49 1.695 0.72 ;
      RECT 1.405 0.535 2.615 0.675 ;
      RECT 1.835 0.83 2.125 1.06 ;
      RECT 0.975 0.83 1.265 1.06 ;
      RECT 0.115 0.83 0.405 1.06 ;
      RECT 0.115 0.875 2.125 1.015 ;
  END
  PROPERTY CatenaDesignType "deviceLevel" ;
END OAI221X1_HS

MACRO OAI221X2_HS
  CLASS CORE ;
  ORIGIN 0 0 ;
  FOREIGN OAI221X2_HS 0 0 ;
  SIZE 5.98 BY 4.14 ;
  SYMMETRY X Y ;
  SITE CoreSite ;
  PIN A0
    DIRECTION INPUT ;
    USE SIGNAL ;
    ANTENNAMODEL OXIDE1 ;
      ANTENNAGATEAREA 0.666 LAYER met1 ;
      ANTENNAMAXAREACAR 0.274399 LAYER met1 ;
      ANTENNAMAXSIDEAREACAR 0.271772 LAYER met1 ;
    PORT
      LAYER met1 ;
        RECT 0.33 1.37 0.59 2.61 ;
    END
  END A0
  PIN A1
    DIRECTION INPUT ;
    USE SIGNAL ;
    ANTENNAMODEL OXIDE1 ;
      ANTENNAGATEAREA 0.666 LAYER met1 ;
      ANTENNAMAXAREACAR 0.26036 LAYER met1 ;
      ANTENNAMAXSIDEAREACAR 0.255255 LAYER met1 ;
    PORT
      LAYER met1 ;
        RECT 1.25 1.285 1.51 2.525 ;
    END
  END A1
  PIN B0
    DIRECTION INPUT ;
    USE SIGNAL ;
    ANTENNAMODEL OXIDE1 ;
      ANTENNAGATEAREA 0.666 LAYER met1 ;
      ANTENNAMAXAREACAR 0.26036 LAYER met1 ;
      ANTENNAMAXSIDEAREACAR 0.255255 LAYER met1 ;
    PORT
      LAYER met1 ;
        RECT 2.63 1.29 2.89 2.53 ;
    END
  END B0
  PIN B1
    DIRECTION INPUT ;
    USE SIGNAL ;
    ANTENNAMODEL OXIDE1 ;
      ANTENNAGATEAREA 0.666 LAYER met1 ;
      ANTENNAMAXAREACAR 0.26036 LAYER met1 ;
      ANTENNAMAXSIDEAREACAR 0.255255 LAYER met1 ;
    PORT
      LAYER met1 ;
        RECT 3.55 1.29 3.81 2.53 ;
    END
  END B1
  PIN C0
    DIRECTION INPUT ;
    USE SIGNAL ;
    ANTENNAMODEL OXIDE1 ;
      ANTENNAGATEAREA 0.666 LAYER met1 ;
      ANTENNAMAXAREACAR 0.361186 LAYER met1 ;
      ANTENNAMAXSIDEAREACAR 0.373874 LAYER met1 ;
    PORT
      LAYER met1 ;
        RECT 4.47 1.27 4.73 2.51 ;
    END
  END C0
  PIN VDD
    DIRECTION INPUT ;
    USE POWER ;
    SHAPE ABUTMENT ;
    NETEXPR "VDD VDD!" ;
    PORT
      LAYER met1 ;
        RECT 0 3.94 5.98 4.34 ;
    END
  END VDD
  PIN VSS
    DIRECTION INPUT ;
    USE GROUND ;
    SHAPE ABUTMENT ;
    NETEXPR "VSS VSS!" ;
    PORT
      LAYER met1 ;
        RECT 0 -0.2 5.98 0.2 ;
    END
  END VSS
  PIN Y
    DIRECTION OUTPUT ;
    USE SIGNAL ;
    ANTENNADIFFAREA 1.4392 LAYER met1 ;
    PORT
      LAYER met1 ;
        RECT 1.435 2.675 5.65 2.905 ;
        RECT 5.39 1.285 5.65 2.905 ;
        RECT 5.055 1.285 5.65 1.515 ;
        RECT 5.055 2.675 5.285 3.325 ;
        RECT 5.055 0.845 5.285 1.515 ;
        RECT 3.675 2.675 3.905 2.965 ;
        RECT 1.435 2.675 1.665 2.965 ;
    END
  END Y
  OBS
    LAYER met1 ;
      RECT 5.485 0.415 5.715 1.065 ;
      RECT 4.625 0.415 4.855 1.065 ;
      RECT 3.675 0.415 3.905 0.705 ;
      RECT 2.815 0.415 3.045 0.705 ;
      RECT 2.815 0.415 5.715 0.645 ;
      RECT 0.145 0.905 4.335 1.135 ;
      RECT 4.105 0.845 4.335 1.135 ;
      RECT 3.245 0.845 3.475 1.135 ;
      RECT 2.385 0.485 2.615 1.135 ;
      RECT 1.435 0.485 1.665 1.135 ;
      RECT 0.575 0.485 0.805 1.135 ;
      RECT 2.385 3.105 4.335 3.335 ;
      RECT 4.105 3.045 4.335 3.335 ;
      RECT 3.245 3.045 3.475 3.335 ;
      RECT 2.385 3.045 2.615 3.335 ;
      RECT 0.145 3.105 2.095 3.335 ;
      RECT 1.865 3.045 2.095 3.335 ;
      RECT 1.005 3.035 1.235 3.335 ;
      RECT 0.145 3.035 0.375 3.335 ;
  END
  PROPERTY CatenaDesignType "deviceLevel" ;
END OAI221X2_HS

MACRO OAI222X1_HS
  CLASS CORE ;
  ORIGIN 0 0 ;
  FOREIGN OAI222X1_HS 0 0 ;
  SIZE 3.68 BY 4.14 ;
  SYMMETRY X Y ;
  SITE CoreSite ;
  PIN A0
    DIRECTION INPUT ;
    USE SIGNAL ;
    ANTENNAMODEL OXIDE1 ;
      ANTENNAGATEAREA 0.333 LAYER met1 ;
      ANTENNAMAXAREACAR 0.357357 LAYER met1 ;
      ANTENNAMAXSIDEAREACAR 0.42042 LAYER met1 ;
    PORT
      LAYER met1 ;
        RECT 0.33 1.185 0.59 2.425 ;
    END
  END A0
  PIN A1
    DIRECTION INPUT ;
    USE SIGNAL ;
    ANTENNAMODEL OXIDE1 ;
      ANTENNAGATEAREA 0.333 LAYER met1 ;
      ANTENNAMAXAREACAR 0.357357 LAYER met1 ;
      ANTENNAMAXSIDEAREACAR 0.42042 LAYER met1 ;
    PORT
      LAYER met1 ;
        RECT 0.79 1.49 1.05 2.73 ;
    END
  END A1
  PIN B0
    DIRECTION INPUT ;
    USE SIGNAL ;
    ANTENNAMODEL OXIDE1 ;
      ANTENNAGATEAREA 0.333 LAYER met1 ;
      ANTENNAMAXAREACAR 0.467117 LAYER met1 ;
      ANTENNAMAXSIDEAREACAR 0.54955 LAYER met1 ;
    PORT
      LAYER met1 ;
        RECT 1.25 1.195 1.51 2.435 ;
    END
  END B0
  PIN B1
    DIRECTION INPUT ;
    USE SIGNAL ;
    ANTENNAMODEL OXIDE1 ;
      ANTENNAGATEAREA 0.333 LAYER met1 ;
      ANTENNAMAXAREACAR 0.487538 LAYER met1 ;
      ANTENNAMAXSIDEAREACAR 0.573574 LAYER met1 ;
    PORT
      LAYER met1 ;
        RECT 1.71 1.385 1.97 2.625 ;
    END
  END B1
  PIN C0
    DIRECTION INPUT ;
    USE SIGNAL ;
    ANTENNAMODEL OXIDE1 ;
      ANTENNAGATEAREA 0.333 LAYER met1 ;
      ANTENNAMAXAREACAR 0.344595 LAYER met1 ;
      ANTENNAMAXSIDEAREACAR 0.405405 LAYER met1 ;
    PORT
      LAYER met1 ;
        RECT 3.09 1.425 3.35 2.665 ;
    END
  END C0
  PIN C1
    DIRECTION INPUT ;
    USE SIGNAL ;
    ANTENNAMODEL OXIDE1 ;
      ANTENNAGATEAREA 0.333 LAYER met1 ;
      ANTENNAMAXAREACAR 0.472222 LAYER met1 ;
      ANTENNAMAXSIDEAREACAR 0.555556 LAYER met1 ;
    PORT
      LAYER met1 ;
        RECT 2.17 1.19 2.43 2.43 ;
    END
  END C1
  PIN VDD
    DIRECTION INPUT ;
    USE POWER ;
    SHAPE ABUTMENT ;
    NETEXPR "VDD VDD!" ;
    PORT
      LAYER met1 ;
        RECT 0 3.94 3.68 4.34 ;
    END
  END VDD
  PIN VSS
    DIRECTION INPUT ;
    USE GROUND ;
    SHAPE ABUTMENT ;
    NETEXPR "VSS VSS!" ;
    PORT
      LAYER met1 ;
        RECT 0 -0.2 3.68 0.2 ;
    END
  END VSS
  PIN Y
    DIRECTION OUTPUT ;
    USE SIGNAL ;
    ANTENNADIFFAREA 1.0085 LAYER met1 ;
    PORT
      LAYER met1 ;
        RECT 2.63 0.845 3.045 1.135 ;
        RECT 1.005 3.105 2.89 3.335 ;
        RECT 2.63 0.845 2.89 3.335 ;
        RECT 2.385 3.045 2.89 3.335 ;
        RECT 1.005 3.045 1.235 3.335 ;
    END
  END Y
  OBS
    LAYER met1 ;
      RECT 1.495 0.445 3.505 0.675 ;
      RECT 0.545 0.815 2.215 1.045 ;
  END
  PROPERTY CatenaDesignType "deviceLevel" ;
END OAI222X1_HS

MACRO OAI222X2_HS
  CLASS CORE ;
  ORIGIN 0 0 ;
  FOREIGN OAI222X2_HS 0 0 ;
  SIZE 6.9 BY 4.14 ;
  SYMMETRY X Y ;
  SITE CoreSite ;
  PIN A0
    DIRECTION INPUT ;
    USE SIGNAL ;
    ANTENNAMODEL OXIDE1 ;
      ANTENNAGATEAREA 0.666 LAYER met1 ;
      ANTENNAMAXAREACAR 0.28461 LAYER met1 ;
      ANTENNAMAXSIDEAREACAR 0.283784 LAYER met1 ;
    PORT
      LAYER met1 ;
        RECT 0.33 1.225 0.59 2.465 ;
    END
  END A0
  PIN A1
    DIRECTION INPUT ;
    USE SIGNAL ;
    ANTENNAMODEL OXIDE1 ;
      ANTENNAGATEAREA 0.666 LAYER met1 ;
      ANTENNAMAXAREACAR 0.280781 LAYER met1 ;
      ANTENNAMAXSIDEAREACAR 0.279279 LAYER met1 ;
    PORT
      LAYER met1 ;
        RECT 1.25 1.23 1.51 2.47 ;
    END
  END A1
  PIN B0
    DIRECTION INPUT ;
    USE SIGNAL ;
    ANTENNAMODEL OXIDE1 ;
      ANTENNAGATEAREA 0.666 LAYER met1 ;
      ANTENNAMAXAREACAR 0.280781 LAYER met1 ;
      ANTENNAMAXSIDEAREACAR 0.279279 LAYER met1 ;
    PORT
      LAYER met1 ;
        RECT 2.63 1.215 2.89 2.455 ;
    END
  END B0
  PIN B1
    DIRECTION INPUT ;
    USE SIGNAL ;
    ANTENNAMODEL OXIDE1 ;
      ANTENNAGATEAREA 0.666 LAYER met1 ;
      ANTENNAMAXAREACAR 0.280781 LAYER met1 ;
      ANTENNAMAXSIDEAREACAR 0.279279 LAYER met1 ;
    PORT
      LAYER met1 ;
        RECT 3.55 1.245 3.81 2.485 ;
    END
  END B1
  PIN C0
    DIRECTION INPUT ;
    USE SIGNAL ;
    ANTENNAMODEL OXIDE1 ;
      ANTENNAGATEAREA 0.666 LAYER met1 ;
      ANTENNAMAXAREACAR 0.280781 LAYER met1 ;
      ANTENNAMAXSIDEAREACAR 0.279279 LAYER met1 ;
    PORT
      LAYER met1 ;
        RECT 4.93 1.29 5.19 2.53 ;
    END
  END C0
  PIN C1
    DIRECTION INPUT ;
    USE SIGNAL ;
    ANTENNAMODEL OXIDE1 ;
      ANTENNAGATEAREA 0.666 LAYER met1 ;
      ANTENNAMAXAREACAR 0.280781 LAYER met1 ;
      ANTENNAMAXSIDEAREACAR 0.279279 LAYER met1 ;
    PORT
      LAYER met1 ;
        RECT 5.85 1.245 6.11 2.485 ;
    END
  END C1
  PIN VDD
    DIRECTION INPUT ;
    USE POWER ;
    SHAPE ABUTMENT ;
    NETEXPR "VDD VDD!" ;
    PORT
      LAYER met1 ;
        RECT 0 3.94 6.9 4.34 ;
    END
  END VDD
  PIN VSS
    DIRECTION INPUT ;
    USE GROUND ;
    SHAPE ABUTMENT ;
    NETEXPR "VSS VSS!" ;
    PORT
      LAYER met1 ;
        RECT 0 -0.2 6.9 0.2 ;
    END
  END VSS
  PIN Y
    DIRECTION OUTPUT ;
    USE SIGNAL ;
    ANTENNADIFFAREA 1.652 LAYER met1 ;
    PORT
      LAYER met1 ;
        RECT 5.915 2.735 6.145 3.025 ;
        RECT 5.055 0.875 6.145 1.015 ;
        RECT 5.915 0.725 6.145 1.015 ;
        RECT 1.435 2.735 6.145 2.875 ;
        RECT 5.39 0.875 5.65 2.875 ;
        RECT 5.055 0.725 5.285 1.015 ;
        RECT 3.675 2.735 3.905 3.025 ;
        RECT 1.435 2.735 1.665 3.025 ;
    END
  END Y
  OBS
    LAYER met1 ;
      RECT 6.345 0.415 6.575 0.705 ;
      RECT 5.485 0.415 5.715 0.705 ;
      RECT 4.625 0.415 4.855 0.705 ;
      RECT 3.675 0.415 3.905 0.705 ;
      RECT 2.815 0.415 3.045 0.705 ;
      RECT 2.815 0.415 6.575 0.555 ;
      RECT 4.625 3.195 6.575 3.335 ;
      RECT 6.345 3.045 6.575 3.335 ;
      RECT 5.485 3.045 5.715 3.335 ;
      RECT 4.625 3.045 4.855 3.335 ;
      RECT 0.145 0.875 4.335 1.015 ;
      RECT 4.105 0.725 4.335 1.015 ;
      RECT 3.245 0.725 3.475 1.015 ;
      RECT 2.385 0.725 2.615 1.015 ;
      RECT 1.865 0.725 2.095 1.015 ;
      RECT 1.005 0.725 1.235 1.015 ;
      RECT 0.145 0.725 0.375 1.015 ;
      RECT 2.385 3.195 4.335 3.335 ;
      RECT 4.105 3.045 4.335 3.335 ;
      RECT 3.245 3.045 3.475 3.335 ;
      RECT 2.385 3.045 2.615 3.335 ;
      RECT 0.145 3.195 2.095 3.335 ;
      RECT 1.865 3.045 2.095 3.335 ;
      RECT 1.005 3.045 1.235 3.335 ;
      RECT 0.145 3.045 0.375 3.335 ;
  END
  PROPERTY CatenaDesignType "deviceLevel" ;
END OAI222X2_HS

MACRO OAI22X1_HS
  CLASS CORE ;
  ORIGIN 0 0 ;
  FOREIGN OAI22X1_HS 0 0 ;
  SIZE 2.76 BY 4.14 ;
  SYMMETRY X Y ;
  SITE CoreSite ;
  PIN A0
    DIRECTION INPUT ;
    USE SIGNAL ;
    ANTENNAMODEL OXIDE1 ;
      ANTENNAGATEAREA 0.333 LAYER met1 ;
      ANTENNAMAXAREACAR 0.275676 LAYER met1 ;
      ANTENNAMAXSIDEAREACAR 0.324324 LAYER met1 ;
    PORT
      LAYER met1 ;
        RECT 0.325 0.97 0.585 2.21 ;
    END
  END A0
  PIN A1
    DIRECTION INPUT ;
    USE SIGNAL ;
    ANTENNAMODEL OXIDE1 ;
      ANTENNAGATEAREA 0.333 LAYER met1 ;
      ANTENNAMAXAREACAR 0.275676 LAYER met1 ;
      ANTENNAMAXSIDEAREACAR 0.324324 LAYER met1 ;
    PORT
      LAYER met1 ;
        RECT 0.79 1.325 1.05 2.565 ;
    END
  END A1
  PIN B0
    DIRECTION INPUT ;
    USE SIGNAL ;
    ANTENNAMODEL OXIDE1 ;
      ANTENNAGATEAREA 0.333 LAYER met1 ;
      ANTENNAMAXAREACAR 0.296096 LAYER met1 ;
      ANTENNAMAXSIDEAREACAR 0.348348 LAYER met1 ;
    PORT
      LAYER met1 ;
        RECT 1.71 1.49 1.97 2.73 ;
    END
  END B0
  PIN B1
    DIRECTION INPUT ;
    USE SIGNAL ;
    ANTENNAMODEL OXIDE1 ;
      ANTENNAGATEAREA 0.333 LAYER met1 ;
      ANTENNAMAXAREACAR 0.288438 LAYER met1 ;
      ANTENNAMAXSIDEAREACAR 0.339339 LAYER met1 ;
    PORT
      LAYER met1 ;
        RECT 1.25 1.225 1.51 2.465 ;
    END
  END B1
  PIN VDD
    DIRECTION INPUT ;
    USE POWER ;
    SHAPE ABUTMENT ;
    NETEXPR "VDD VDD!" ;
    PORT
      LAYER met1 ;
        RECT 0 3.94 2.76 4.34 ;
    END
  END VDD
  PIN VSS
    DIRECTION INPUT ;
    USE GROUND ;
    SHAPE ABUTMENT ;
    NETEXPR "VSS VSS!" ;
    PORT
      LAYER met1 ;
        RECT 0 -0.2 2.76 0.2 ;
    END
  END VSS
  PIN Y
    DIRECTION OUTPUT ;
    USE SIGNAL ;
    ANTENNADIFFAREA 0.6216 LAYER met1 ;
    PORT
      LAYER met1 ;
        RECT 0.975 3.075 2.43 3.305 ;
        RECT 2.17 0.83 2.43 3.305 ;
        RECT 1.405 0.83 2.43 1.06 ;
        RECT 0.975 3.01 1.265 3.305 ;
    END
  END Y
  OBS
    LAYER met1 ;
      RECT 1.835 0.46 2.125 0.69 ;
      RECT 0.975 0.46 1.265 0.69 ;
      RECT 0.115 0.46 0.405 0.69 ;
      RECT 0.115 0.505 2.125 0.645 ;
  END
  PROPERTY CatenaDesignType "deviceLevel" ;
END OAI22X1_HS

MACRO OAI22X2_HS
  CLASS CORE ;
  ORIGIN 0 0 ;
  FOREIGN OAI22X2_HS 0 0 ;
  SIZE 4.6 BY 4.14 ;
  SYMMETRY X Y ;
  SITE CoreSite ;
  PIN A0
    DIRECTION INPUT ;
    USE SIGNAL ;
    ANTENNAMODEL OXIDE1 ;
      ANTENNAGATEAREA 0.666 LAYER met1 ;
      ANTENNAMAXAREACAR 0.274399 LAYER met1 ;
      ANTENNAMAXSIDEAREACAR 0.271772 LAYER met1 ;
    PORT
      LAYER met1 ;
        RECT 0.33 1.445 0.59 2.685 ;
    END
  END A0
  PIN A1
    DIRECTION INPUT ;
    USE SIGNAL ;
    ANTENNAMODEL OXIDE1 ;
      ANTENNAGATEAREA 0.666 LAYER met1 ;
      ANTENNAMAXAREACAR 0.26036 LAYER met1 ;
      ANTENNAMAXSIDEAREACAR 0.255255 LAYER met1 ;
    PORT
      LAYER met1 ;
        RECT 2.63 1.14 2.89 2.38 ;
    END
  END A1
  PIN B0
    DIRECTION INPUT ;
    USE SIGNAL ;
    ANTENNAMODEL OXIDE1 ;
      ANTENNAGATEAREA 0.666 LAYER met1 ;
      ANTENNAMAXAREACAR 0.307432 LAYER met1 ;
      ANTENNAMAXSIDEAREACAR 0.283784 LAYER met1 ;
    PORT
      LAYER met1 ;
        RECT 1.25 1.485 1.51 2.725 ;
    END
  END B0
  PIN B1
    DIRECTION INPUT ;
    USE SIGNAL ;
    ANTENNAMODEL OXIDE1 ;
      ANTENNAGATEAREA 0.666 LAYER met1 ;
      ANTENNAMAXAREACAR 0.26036 LAYER met1 ;
      ANTENNAMAXSIDEAREACAR 0.255255 LAYER met1 ;
    PORT
      LAYER met1 ;
        RECT 3.55 1.225 3.81 2.465 ;
    END
  END B1
  PIN VDD
    DIRECTION INPUT ;
    USE POWER ;
    SHAPE ABUTMENT ;
    NETEXPR "VDD VDD!" ;
    PORT
      LAYER met1 ;
        RECT 0 3.94 4.6 4.34 ;
    END
  END VDD
  PIN VSS
    DIRECTION INPUT ;
    USE GROUND ;
    SHAPE ABUTMENT ;
    NETEXPR "VSS VSS!" ;
    PORT
      LAYER met1 ;
        RECT 0 -0.2 4.6 0.2 ;
    END
  END VSS
  PIN Y
    DIRECTION OUTPUT ;
    USE SIGNAL ;
    ANTENNADIFFAREA 1.6082 LAYER met1 ;
    PORT
      LAYER met1 ;
        RECT 4.105 0.77 4.335 3.35 ;
        RECT 2.385 2.61 4.335 2.84 ;
        RECT 4.01 0.77 4.335 2.84 ;
        RECT 3.675 0.77 4.335 1.06 ;
        RECT 1.435 0.77 4.335 1 ;
        RECT 3.245 2.61 3.475 2.9 ;
        RECT 2.385 2.61 2.615 2.9 ;
        RECT 1.435 0.77 1.665 1.06 ;
    END
  END Y
  OBS
    LAYER met1 ;
      RECT 1.005 0.34 1.235 0.99 ;
      RECT 0.145 0.34 0.375 0.99 ;
      RECT 4.105 0.34 4.335 0.63 ;
      RECT 3.245 0.34 3.475 0.63 ;
      RECT 2.385 0.34 2.615 0.63 ;
      RECT 1.865 0.34 2.095 0.63 ;
      RECT 0.145 0.34 4.335 0.57 ;
      RECT 3.675 3.04 3.905 3.33 ;
      RECT 1.435 3.04 3.905 3.27 ;
      RECT 1.435 2.98 1.665 3.27 ;
      RECT 0.575 3.47 3.045 3.7 ;
      RECT 2.815 3.41 3.045 3.7 ;
      RECT 0.575 3.41 0.805 3.7 ;
  END
  PROPERTY CatenaDesignType "deviceLevel" ;
END OAI22X2_HS

MACRO OR2X1_HS
  CLASS CORE ;
  ORIGIN 0 0 ;
  FOREIGN OR2X1_HS 0 0 ;
  SIZE 2.3 BY 4.14 ;
  SYMMETRY X Y ;
  SITE CoreSite ;
  PIN A
    DIRECTION INPUT ;
    USE SIGNAL ;
    ANTENNAMODEL OXIDE1 ;
      ANTENNAGATEAREA 0.18075 LAYER met1 ;
      ANTENNAMAXAREACAR 0.681881 LAYER met1 ;
      ANTENNAMAXSIDEAREACAR 0.802213 LAYER met1 ;
    PORT
      LAYER met1 ;
        RECT 0.79 1.455 1.05 2.695 ;
    END
  END A
  PIN B
    DIRECTION INPUT ;
    USE SIGNAL ;
    ANTENNAMODEL OXIDE1 ;
      ANTENNAGATEAREA 0.18075 LAYER met1 ;
      ANTENNAMAXAREACAR 0.517289 LAYER met1 ;
      ANTENNAMAXSIDEAREACAR 0.608575 LAYER met1 ;
    PORT
      LAYER met1 ;
        RECT 0.33 0.95 0.59 2.19 ;
    END
  END B
  PIN VDD
    DIRECTION INPUT ;
    USE POWER ;
    SHAPE ABUTMENT ;
    NETEXPR "VDD VDD!" ;
    PORT
      LAYER met1 ;
        RECT 0 3.94 2.3 4.34 ;
    END
  END VDD
  PIN VSS
    DIRECTION INPUT ;
    USE GROUND ;
    SHAPE ABUTMENT ;
    NETEXPR "VSS VSS!" ;
    PORT
      LAYER met1 ;
        RECT 0 -0.2 2.3 0.2 ;
    END
  END VSS
  PIN Y
    DIRECTION OUTPUT ;
    USE SIGNAL ;
    ANTENNADIFFAREA 0.5883 LAYER met1 ;
    PORT
      LAYER met1 ;
        RECT 1.495 3.21 1.97 3.5 ;
        RECT 1.71 0.505 1.97 3.5 ;
        RECT 1.495 0.505 1.97 0.795 ;
    END
  END Y
  OBS
    LAYER met1 ;
      RECT 0.115 3.27 1.2 3.5 ;
      RECT 0.97 2.84 1.2 3.5 ;
      RECT 1.19 0.965 1.42 3.07 ;
      RECT 0.765 0.965 1.42 1.195 ;
      RECT 0.765 0.475 0.995 1.195 ;
      RECT 0.545 0.475 0.995 0.705 ;
  END
  PROPERTY CatenaDesignType "deviceLevel" ;
END OR2X1_HS

MACRO OR2X2_HS
  CLASS CORE ;
  ORIGIN 0 0 ;
  FOREIGN OR2X2_HS 0 0 ;
  SIZE 2.3 BY 4.14 ;
  SYMMETRY X Y ;
  SITE CoreSite ;
  PIN A
    DIRECTION INPUT ;
    USE SIGNAL ;
    ANTENNAMODEL OXIDE1 ;
      ANTENNAGATEAREA 0.18075 LAYER met1 ;
      ANTENNAMAXAREACAR 0.521992 LAYER met1 ;
      ANTENNAMAXSIDEAREACAR 0.614108 LAYER met1 ;
    PORT
      LAYER met1 ;
        RECT 0.79 1.26 1.05 2.5 ;
    END
  END A
  PIN B
    DIRECTION INPUT ;
    USE SIGNAL ;
    ANTENNAMODEL OXIDE1 ;
      ANTENNAGATEAREA 0.18075 LAYER met1 ;
      ANTENNAMAXAREACAR 0.521992 LAYER met1 ;
      ANTENNAMAXSIDEAREACAR 0.614108 LAYER met1 ;
    PORT
      LAYER met1 ;
        RECT 0.33 0.855 0.59 2.095 ;
    END
  END B
  PIN VDD
    DIRECTION INPUT ;
    USE POWER ;
    SHAPE ABUTMENT ;
    NETEXPR "VDD VDD!" ;
    PORT
      LAYER met1 ;
        RECT 0 3.94 2.3 4.34 ;
    END
  END VDD
  PIN VSS
    DIRECTION INPUT ;
    USE GROUND ;
    SHAPE ABUTMENT ;
    NETEXPR "VSS VSS!" ;
    PORT
      LAYER met1 ;
        RECT 0 -0.2 2.3 0.2 ;
    END
  END VSS
  PIN Y
    DIRECTION OUTPUT ;
    USE SIGNAL ;
    ANTENNADIFFAREA 0.6216 LAYER met1 ;
    PORT
      LAYER met1 ;
        RECT 1.495 3.045 1.97 3.335 ;
        RECT 1.71 0.34 1.97 3.335 ;
        RECT 1.495 0.34 1.97 0.63 ;
    END
  END Y
  OBS
    LAYER met1 ;
      RECT 0.115 3.075 1.2 3.305 ;
      RECT 0.97 2.645 1.2 3.305 ;
      RECT 1.19 0.77 1.42 2.875 ;
      RECT 0.765 0.77 1.42 1 ;
      RECT 0.765 0.395 0.995 1 ;
      RECT 0.545 0.395 0.995 0.625 ;
  END
  PROPERTY CatenaDesignType "deviceLevel" ;
END OR2X2_HS

MACRO OR3X1_HS
  CLASS CORE ;
  ORIGIN 0 0 ;
  FOREIGN OR3X1_HS 0 0 ;
  SIZE 2.76 BY 4.14 ;
  SYMMETRY X Y ;
  SITE CoreSite ;
  PIN A
    DIRECTION INPUT ;
    USE SIGNAL ;
    ANTENNAMODEL OXIDE1 ;
      ANTENNAGATEAREA 0.18075 LAYER met1 ;
      ANTENNAMAXAREACAR 0.512586 LAYER met1 ;
      ANTENNAMAXSIDEAREACAR 0.603043 LAYER met1 ;
    PORT
      LAYER met1 ;
        RECT 1.25 1.265 1.51 2.505 ;
    END
  END A
  PIN B
    DIRECTION INPUT ;
    USE SIGNAL ;
    ANTENNAMODEL OXIDE1 ;
      ANTENNAGATEAREA 0.18075 LAYER met1 ;
      ANTENNAMAXAREACAR 0.550207 LAYER met1 ;
      ANTENNAMAXSIDEAREACAR 0.647303 LAYER met1 ;
    PORT
      LAYER met1 ;
        RECT 0.79 0.905 1.05 2.145 ;
    END
  END B
  PIN C
    DIRECTION INPUT ;
    USE SIGNAL ;
    ANTENNAMODEL OXIDE1 ;
      ANTENNAGATEAREA 0.18075 LAYER met1 ;
      ANTENNAMAXAREACAR 0.686584 LAYER met1 ;
      ANTENNAMAXSIDEAREACAR 0.807746 LAYER met1 ;
    PORT
      LAYER met1 ;
        RECT 0.33 1.47 0.59 2.71 ;
    END
  END C
  PIN VDD
    DIRECTION INPUT ;
    USE POWER ;
    SHAPE ABUTMENT ;
    NETEXPR "VDD VDD!" ;
    PORT
      LAYER met1 ;
        RECT 0 3.94 2.76 4.34 ;
    END
  END VDD
  PIN VSS
    DIRECTION INPUT ;
    USE GROUND ;
    SHAPE ABUTMENT ;
    NETEXPR "VSS VSS!" ;
    PORT
      LAYER met1 ;
        RECT 0 -0.2 2.76 0.2 ;
    END
  END VSS
  PIN Y
    DIRECTION OUTPUT ;
    USE SIGNAL ;
    ANTENNADIFFAREA 0.5883 LAYER met1 ;
    PORT
      LAYER met1 ;
        RECT 1.925 3.045 2.43 3.335 ;
        RECT 2.17 0.465 2.43 3.335 ;
        RECT 1.925 0.465 2.43 0.755 ;
    END
  END Y
  OBS
    LAYER met1 ;
      RECT 0.115 3.075 1.2 3.305 ;
      RECT 0.97 2.675 1.2 3.305 ;
      RECT 0.97 2.675 2.03 2.905 ;
      RECT 1.8 0.895 2.03 2.905 ;
      RECT 1.36 0.895 2.03 1.125 ;
      RECT 1.36 0.465 1.59 1.125 ;
      RECT 0.115 0.465 1.59 0.695 ;
  END
  PROPERTY CatenaDesignType "deviceLevel" ;
END OR3X1_HS

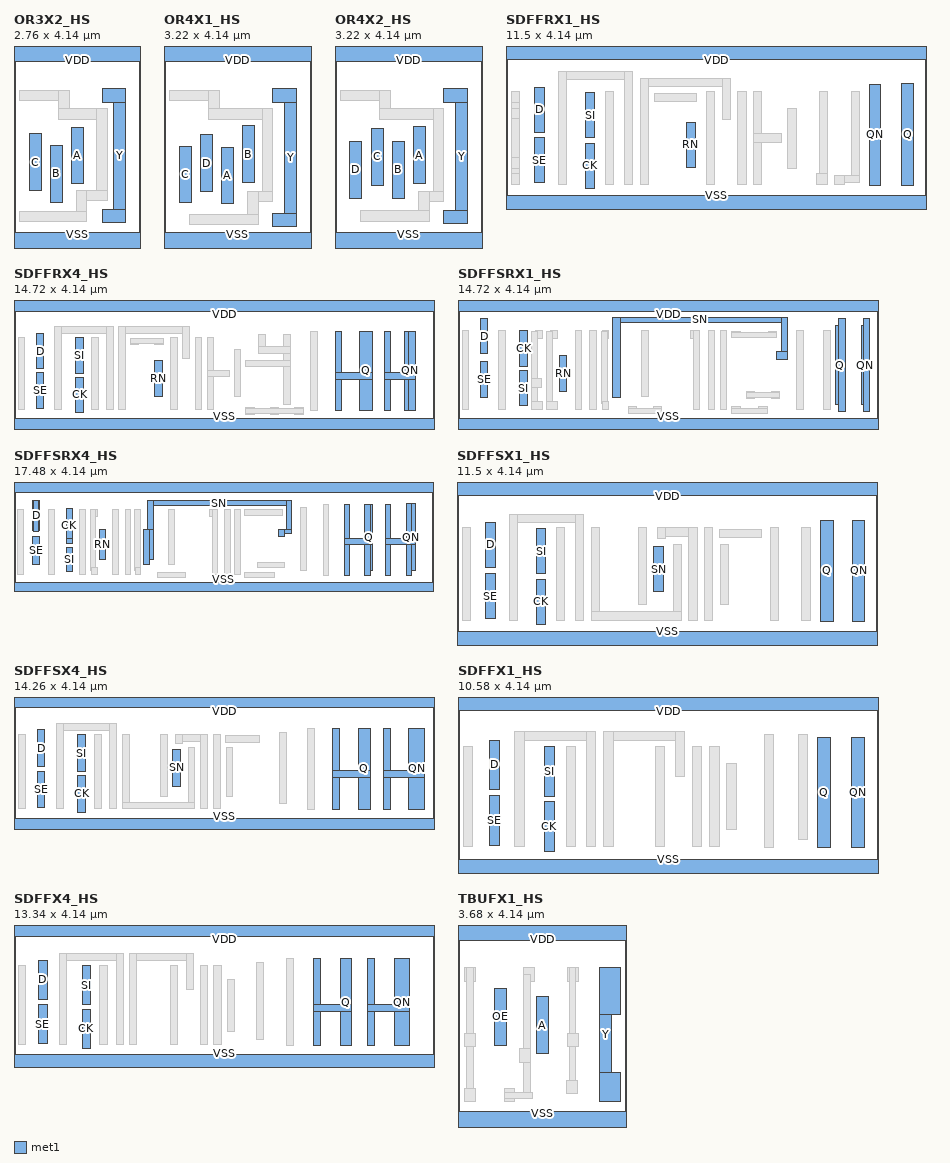
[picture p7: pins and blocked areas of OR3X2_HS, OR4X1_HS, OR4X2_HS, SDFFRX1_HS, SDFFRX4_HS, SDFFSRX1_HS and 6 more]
MACRO OR3X2_HS
  CLASS CORE ;
  ORIGIN 0 0 ;
  FOREIGN OR3X2_HS 0 0 ;
  SIZE 2.76 BY 4.14 ;
  SYMMETRY X Y ;
  SITE CoreSite ;
  PIN A
    DIRECTION INPUT ;
    USE SIGNAL ;
    ANTENNAMODEL OXIDE1 ;
      ANTENNAGATEAREA 0.18075 LAYER met1 ;
      ANTENNAMAXAREACAR 0.672476 LAYER met1 ;
      ANTENNAMAXSIDEAREACAR 0.791148 LAYER met1 ;
    PORT
      LAYER met1 ;
        RECT 1.25 1.265 1.51 2.505 ;
    END
  END A
  PIN B
    DIRECTION INPUT ;
    USE SIGNAL ;
    ANTENNAMODEL OXIDE1 ;
      ANTENNAGATEAREA 0.18075 LAYER met1 ;
      ANTENNAMAXAREACAR 0.550207 LAYER met1 ;
      ANTENNAMAXSIDEAREACAR 0.647303 LAYER met1 ;
    PORT
      LAYER met1 ;
        RECT 0.79 0.865 1.05 2.105 ;
    END
  END B
  PIN C
    DIRECTION INPUT ;
    USE SIGNAL ;
    ANTENNAMODEL OXIDE1 ;
      ANTENNAGATEAREA 0.18075 LAYER met1 ;
      ANTENNAMAXAREACAR 0.686584 LAYER met1 ;
      ANTENNAMAXSIDEAREACAR 0.807746 LAYER met1 ;
    PORT
      LAYER met1 ;
        RECT 0.33 1.115 0.59 2.355 ;
    END
  END C
  PIN VDD
    DIRECTION INPUT ;
    USE POWER ;
    SHAPE ABUTMENT ;
    NETEXPR "VDD VDD!" ;
    PORT
      LAYER met1 ;
        RECT 0 3.94 2.76 4.34 ;
    END
  END VDD
  PIN VSS
    DIRECTION INPUT ;
    USE GROUND ;
    SHAPE ABUTMENT ;
    NETEXPR "VSS VSS!" ;
    PORT
      LAYER met1 ;
        RECT 0 -0.2 2.76 0.2 ;
    END
  END VSS
  PIN Y
    DIRECTION OUTPUT ;
    USE SIGNAL ;
    ANTENNADIFFAREA 0.6216 LAYER met1 ;
    PORT
      LAYER met1 ;
        RECT 1.925 3.045 2.43 3.335 ;
        RECT 2.17 0.425 2.43 3.335 ;
        RECT 1.925 0.425 2.43 0.715 ;
    END
  END Y
  OBS
    LAYER met1 ;
      RECT 0.115 3.075 1.2 3.305 ;
      RECT 0.97 2.675 1.2 3.305 ;
      RECT 0.97 2.675 2.03 2.905 ;
      RECT 1.8 0.895 2.03 2.905 ;
      RECT 1.36 0.895 2.03 1.125 ;
      RECT 1.36 0.445 1.59 1.125 ;
      RECT 0.115 0.445 1.59 0.675 ;
  END
  PROPERTY CatenaDesignType "deviceLevel" ;
END OR3X2_HS

MACRO OR4X1_HS
  CLASS CORE ;
  ORIGIN 0 0 ;
  FOREIGN OR4X1_HS 0 0 ;
  SIZE 3.22 BY 4.14 ;
  SYMMETRY X Y ;
  SITE CoreSite ;
  PIN A
    DIRECTION INPUT ;
    USE SIGNAL ;
    ANTENNAMODEL OXIDE1 ;
      ANTENNAGATEAREA 0.18075 LAYER met1 ;
      ANTENNAMAXAREACAR 0.559613 LAYER met1 ;
      ANTENNAMAXSIDEAREACAR 0.658368 LAYER met1 ;
    PORT
      LAYER met1 ;
        RECT 1.25 0.83 1.51 2.07 ;
    END
  END A
  PIN B
    DIRECTION INPUT ;
    USE SIGNAL ;
    ANTENNAMODEL OXIDE1 ;
      ANTENNAGATEAREA 0.18075 LAYER met1 ;
      ANTENNAMAXAREACAR 2.085145 LAYER met1 ;
      ANTENNAMAXSIDEAREACAR 2.107884 LAYER met1 ;
    PORT
      LAYER met1 ;
        RECT 1.71 1.29 1.97 2.53 ;
    END
  END B
  PIN C
    DIRECTION INPUT ;
    USE SIGNAL ;
    ANTENNAMODEL OXIDE1 ;
      ANTENNAGATEAREA 0.18075 LAYER met1 ;
      ANTENNAMAXAREACAR 0.470263 LAYER met1 ;
      ANTENNAMAXSIDEAREACAR 0.55325 LAYER met1 ;
    PORT
      LAYER met1 ;
        RECT 0.33 0.85 0.59 2.09 ;
    END
  END C
  PIN D
    DIRECTION INPUT ;
    USE SIGNAL ;
    ANTENNAMODEL OXIDE1 ;
      ANTENNAGATEAREA 0.18075 LAYER met1 ;
      ANTENNAMAXAREACAR 2.028714 LAYER met1 ;
      ANTENNAMAXSIDEAREACAR 2.041494 LAYER met1 ;
    PORT
      LAYER met1 ;
        RECT 0.79 1.095 1.05 2.335 ;
    END
  END D
  PIN VDD
    DIRECTION INPUT ;
    USE POWER ;
    SHAPE ABUTMENT ;
    NETEXPR "VDD VDD!" ;
    PORT
      LAYER met1 ;
        RECT 0 3.94 3.22 4.34 ;
    END
  END VDD
  PIN VSS
    DIRECTION INPUT ;
    USE GROUND ;
    SHAPE ABUTMENT ;
    NETEXPR "VSS VSS!" ;
    PORT
      LAYER met1 ;
        RECT 0 -0.2 3.22 0.2 ;
    END
  END VSS
  PIN Y
    DIRECTION OUTPUT ;
    USE SIGNAL ;
    ANTENNADIFFAREA 0.5883 LAYER met1 ;
    PORT
      LAYER met1 ;
        RECT 2.355 3.045 2.89 3.335 ;
        RECT 2.63 0.34 2.89 3.335 ;
        RECT 2.355 0.34 2.89 0.63 ;
    END
  END Y
  OBS
    LAYER met1 ;
      RECT 0.115 3.075 1.2 3.305 ;
      RECT 0.97 2.675 1.2 3.305 ;
      RECT 0.97 2.675 2.37 2.905 ;
      RECT 2.14 0.875 2.37 2.905 ;
      RECT 1.82 0.875 2.37 1.105 ;
      RECT 1.82 0.38 2.05 1.105 ;
      RECT 0.545 0.38 2.05 0.61 ;
  END
  PROPERTY CatenaDesignType "deviceLevel" ;
END OR4X1_HS

MACRO OR4X2_HS
  CLASS CORE ;
  ORIGIN 0 0 ;
  FOREIGN OR4X2_HS 0 0 ;
  SIZE 3.22 BY 4.14 ;
  SYMMETRY X Y ;
  SITE CoreSite ;
  PIN A
    DIRECTION INPUT ;
    USE SIGNAL ;
    ANTENNAMODEL OXIDE1 ;
      ANTENNAGATEAREA 0.18075 LAYER met1 ;
      ANTENNAMAXAREACAR 0.569018 LAYER met1 ;
      ANTENNAMAXSIDEAREACAR 0.669433 LAYER met1 ;
    PORT
      LAYER met1 ;
        RECT 1.71 1.275 1.97 2.515 ;
    END
  END A
  PIN B
    DIRECTION INPUT ;
    USE SIGNAL ;
    ANTENNAMODEL OXIDE1 ;
      ANTENNAGATEAREA 0.18075 LAYER met1 ;
      ANTENNAMAXAREACAR 0.5361 LAYER met1 ;
      ANTENNAMAXSIDEAREACAR 0.630705 LAYER met1 ;
    PORT
      LAYER met1 ;
        RECT 1.25 0.95 1.51 2.19 ;
    END
  END B
  PIN C
    DIRECTION INPUT ;
    USE SIGNAL ;
    ANTENNAMODEL OXIDE1 ;
      ANTENNAGATEAREA 0.18075 LAYER met1 ;
      ANTENNAMAXAREACAR 0.507884 LAYER met1 ;
      ANTENNAMAXSIDEAREACAR 0.59751 LAYER met1 ;
    PORT
      LAYER met1 ;
        RECT 0.79 1.24 1.05 2.48 ;
    END
  END C
  PIN D
    DIRECTION INPUT ;
    USE SIGNAL ;
    ANTENNAMODEL OXIDE1 ;
      ANTENNAGATEAREA 0.18075 LAYER met1 ;
      ANTENNAMAXAREACAR 0.503181 LAYER met1 ;
      ANTENNAMAXSIDEAREACAR 0.591978 LAYER met1 ;
    PORT
      LAYER met1 ;
        RECT 0.32 0.95 0.58 2.19 ;
    END
  END D
  PIN VDD
    DIRECTION INPUT ;
    USE POWER ;
    SHAPE ABUTMENT ;
    NETEXPR "VDD VDD!" ;
    PORT
      LAYER met1 ;
        RECT 0 3.94 3.22 4.34 ;
    END
  END VDD
  PIN VSS
    DIRECTION INPUT ;
    USE GROUND ;
    SHAPE ABUTMENT ;
    NETEXPR "VSS VSS!" ;
    PORT
      LAYER met1 ;
        RECT 0 -0.2 3.22 0.2 ;
    END
  END VSS
  PIN Y
    DIRECTION OUTPUT ;
    USE SIGNAL ;
    ANTENNADIFFAREA 0.6216 LAYER met1 ;
    PORT
      LAYER met1 ;
        RECT 2.355 3.045 2.89 3.335 ;
        RECT 2.63 0.395 2.89 3.335 ;
        RECT 2.355 0.395 2.89 0.685 ;
    END
  END Y
  OBS
    LAYER met1 ;
      RECT 0.115 3.075 1.2 3.305 ;
      RECT 0.97 2.675 1.2 3.305 ;
      RECT 0.97 2.675 2.37 2.905 ;
      RECT 2.14 0.875 2.37 2.905 ;
      RECT 1.82 0.875 2.37 1.105 ;
      RECT 1.82 0.45 2.05 1.105 ;
      RECT 0.545 0.45 2.05 0.68 ;
  END
  PROPERTY CatenaDesignType "deviceLevel" ;
END OR4X2_HS

MACRO SDFFRX1_HS
  CLASS CORE ;
  ORIGIN 0 0 ;
  FOREIGN SDFFRX1_HS 0 0 ;
  SIZE 11.5 BY 4.14 ;
  SYMMETRY X Y ;
  SITE CoreSite ;
  PIN CK
    DIRECTION INPUT ;
    USE SIGNAL ;
    ANTENNAMODEL OXIDE1 ;
      ANTENNAGATEAREA 0.18075 LAYER met1 ;
      ANTENNAMAXAREACAR 0.775934 LAYER met1 ;
      ANTENNAMAXSIDEAREACAR 0.912863 LAYER met1 ;
    PORT
      LAYER met1 ;
        RECT 2.17 0.4 2.43 1.64 ;
    END
  END CK
  PIN D
    DIRECTION INPUT ;
    USE SIGNAL ;
    ANTENNAMODEL OXIDE1 ;
      ANTENNAGATEAREA 0.18075 LAYER met1 ;
      ANTENNAMAXAREACAR 0.489073 LAYER met1 ;
      ANTENNAMAXSIDEAREACAR 0.57538 LAYER met1 ;
    PORT
      LAYER met1 ;
        RECT 0.79 1.93 1.05 3.17 ;
    END
  END D
  PIN Q
    DIRECTION OUTPUT ;
    USE SIGNAL ;
    ANTENNADIFFAREA 0.5883 LAYER met1 ;
    PORT
      LAYER met1 ;
        RECT 10.825 0.49 11.17 3.26 ;
    END
  END Q
  PIN QN
    DIRECTION OUTPUT ;
    USE SIGNAL ;
    ANTENNADIFFAREA 0.5883 LAYER met1 ;
    PORT
      LAYER met1 ;
        RECT 9.965 0.485 10.25 3.255 ;
    END
  END QN
  PIN RN
    DIRECTION INPUT ;
    USE SIGNAL ;
    ANTENNAMODEL OXIDE1 ;
      ANTENNAGATEAREA 0.3615 LAYER met1 ;
      ANTENNAMAXAREACAR 1.772891 LAYER met1 ;
      ANTENNAMAXSIDEAREACAR 1.991701 LAYER met1 ;
    PORT
      LAYER met1 ;
        RECT 4.93 0.975 5.19 2.215 ;
    END
  END RN
  PIN SE
    DIRECTION INPUT ;
    USE SIGNAL ;
    ANTENNAMODEL OXIDE1 ;
      ANTENNAGATEAREA 0.3615 LAYER met1 ;
      ANTENNAMAXAREACAR 0.942877 LAYER met1 ;
      ANTENNAMAXSIDEAREACAR 1.015214 LAYER met1 ;
    PORT
      LAYER met1 ;
        RECT 0.79 0.55 1.05 1.79 ;
    END
  END SE
  PIN SI
    DIRECTION INPUT ;
    USE SIGNAL ;
    ANTENNAMODEL OXIDE1 ;
      ANTENNAGATEAREA 0.18075 LAYER met1 ;
      ANTENNAMAXAREACAR 0.771231 LAYER met1 ;
      ANTENNAMAXSIDEAREACAR 0.907331 LAYER met1 ;
    PORT
      LAYER met1 ;
        RECT 2.17 1.78 2.43 3.02 ;
    END
  END SI
  PIN VDD
    DIRECTION INPUT ;
    USE POWER ;
    SHAPE ABUTMENT ;
    NETEXPR "VDD VDD!" ;
    PORT
      LAYER met1 ;
        RECT 0 3.94 11.5 4.34 ;
    END
  END VDD
  PIN VSS
    DIRECTION INPUT ;
    USE GROUND ;
    SHAPE ABUTMENT ;
    NETEXPR "VSS VSS!" ;
    PORT
      LAYER met1 ;
        RECT 0 -0.2 11.5 0.2 ;
    END
  END VSS
  OBS
    LAYER met1 ;
      RECT 9.45 0.57 9.68 3.04 ;
      RECT 8.985 0.57 9.68 0.74 ;
      RECT 8.985 0.51 9.275 0.74 ;
      RECT 8.585 0.51 8.815 3.04 ;
      RECT 8.495 0.51 8.815 0.8 ;
      RECT 6.775 0.51 7.005 3.04 ;
      RECT 6.775 1.66 7.545 1.89 ;
      RECT 3.675 3.18 6.145 3.41 ;
      RECT 5.915 2.28 6.145 3.41 ;
      RECT 3.675 0.51 3.905 3.41 ;
      RECT 1.435 3.375 3.475 3.605 ;
      RECT 3.245 0.51 3.475 3.605 ;
      RECT 1.435 0.51 1.665 3.605 ;
      RECT 0.15 0.515 0.38 3.045 ;
      RECT 0.145 2.75 0.38 3.04 ;
      RECT 0.145 2.31 0.38 2.6 ;
      RECT 0.145 0.95 0.38 1.24 ;
      RECT 0.145 0.51 0.375 0.8 ;
      RECT 7.715 0.95 7.945 2.6 ;
      RECT 6.345 0.51 6.575 3.04 ;
      RECT 5.485 0.51 5.715 3.04 ;
      RECT 4.075 2.78 5.225 3.01 ;
      RECT 2.725 0.51 2.955 3.04 ;
  END
  PROPERTY CatenaDesignType "deviceLevel" ;
END SDFFRX1_HS

MACRO SDFFRX4_HS
  CLASS CORE ;
  ORIGIN 0 0 ;
  FOREIGN SDFFRX4_HS 0 0 ;
  SIZE 14.72 BY 4.14 ;
  SYMMETRY X Y ;
  SITE CoreSite ;
  PIN CK
    DIRECTION INPUT ;
    USE SIGNAL ;
    ANTENNAMODEL OXIDE1 ;
      ANTENNAGATEAREA 0.18075 LAYER met1 ;
      ANTENNAMAXAREACAR 0.775934 LAYER met1 ;
      ANTENNAMAXSIDEAREACAR 0.912863 LAYER met1 ;
    PORT
      LAYER met1 ;
        RECT 2.17 0.4 2.43 1.64 ;
    END
  END CK
  PIN D
    DIRECTION INPUT ;
    USE SIGNAL ;
    ANTENNAMODEL OXIDE1 ;
      ANTENNAGATEAREA 0.18075 LAYER met1 ;
      ANTENNAMAXAREACAR 0.672476 LAYER met1 ;
      ANTENNAMAXSIDEAREACAR 0.791148 LAYER met1 ;
    PORT
      LAYER met1 ;
        RECT 0.79 1.935 1.05 3.175 ;
    END
  END D
  PIN Q
    DIRECTION OUTPUT ;
    USE SIGNAL ;
    ANTENNADIFFAREA 1.2432 LAYER met1 ;
    PORT
      LAYER met1 ;
        RECT 12.115 0.485 12.55 3.255 ;
        RECT 11.255 1.575 12.55 1.805 ;
        RECT 11.255 0.485 11.485 3.255 ;
    END
  END Q
  PIN QN
    DIRECTION OUTPUT ;
    USE SIGNAL ;
    ANTENNADIFFAREA 1.2432 LAYER met1 ;
    PORT
      LAYER met1 ;
        RECT 13.835 0.48 14.065 3.255 ;
        RECT 13.67 0.48 14.065 3.25 ;
        RECT 12.975 1.575 14.065 1.805 ;
        RECT 12.975 0.485 13.205 3.255 ;
    END
  END QN
  PIN RN
    DIRECTION INPUT ;
    USE SIGNAL ;
    ANTENNAMODEL OXIDE1 ;
      ANTENNAGATEAREA 0.69675 LAYER met1 ;
      ANTENNAMAXAREACAR 1.218806 LAYER met1 ;
      ANTENNAMAXSIDEAREACAR 1.294582 LAYER met1 ;
    PORT
      LAYER met1 ;
        RECT 4.93 0.975 5.19 2.215 ;
    END
  END RN
  PIN SE
    DIRECTION INPUT ;
    USE SIGNAL ;
    ANTENNAMODEL OXIDE1 ;
      ANTENNAGATEAREA 0.3615 LAYER met1 ;
      ANTENNAMAXAREACAR 0.942877 LAYER met1 ;
      ANTENNAMAXSIDEAREACAR 1.015214 LAYER met1 ;
    PORT
      LAYER met1 ;
        RECT 0.79 0.55 1.05 1.79 ;
    END
  END SE
  PIN SI
    DIRECTION INPUT ;
    USE SIGNAL ;
    ANTENNAMODEL OXIDE1 ;
      ANTENNAGATEAREA 0.18075 LAYER met1 ;
      ANTENNAMAXAREACAR 0.771231 LAYER met1 ;
      ANTENNAMAXSIDEAREACAR 0.907331 LAYER met1 ;
    PORT
      LAYER met1 ;
        RECT 2.17 1.78 2.43 3.02 ;
    END
  END SI
  PIN VDD
    DIRECTION INPUT ;
    USE POWER ;
    SHAPE ABUTMENT ;
    NETEXPR "VDD VDD!" ;
    PORT
      LAYER met1 ;
        RECT 0 3.94 14.72 4.34 ;
    END
  END VDD
  PIN VSS
    DIRECTION INPUT ;
    USE GROUND ;
    SHAPE ABUTMENT ;
    NETEXPR "VSS VSS!" ;
    PORT
      LAYER met1 ;
        RECT 0 -0.2 14.72 0.2 ;
    END
  END VSS
  OBS
    LAYER met1 ;
      RECT 9.845 0.345 10.135 0.575 ;
      RECT 8.985 0.345 9.275 0.575 ;
      RECT 8.125 0.345 8.415 0.575 ;
      RECT 8.125 0.375 10.135 0.545 ;
      RECT 9.445 0.685 9.675 3.12 ;
      RECT 8.585 2.47 8.815 3.12 ;
      RECT 8.585 2.47 9.675 2.7 ;
      RECT 8.115 2 9.675 2.23 ;
      RECT 6.775 0.51 7.005 3.04 ;
      RECT 6.775 1.66 7.545 1.89 ;
      RECT 3.675 3.18 6.145 3.41 ;
      RECT 5.915 2.28 6.145 3.41 ;
      RECT 3.675 0.51 3.905 3.41 ;
      RECT 4.935 2.78 5.225 3.01 ;
      RECT 4.075 2.78 4.365 3.01 ;
      RECT 4.075 2.81 5.225 2.98 ;
      RECT 1.435 3.18 3.475 3.41 ;
      RECT 3.245 0.51 3.475 3.41 ;
      RECT 1.435 0.51 1.665 3.41 ;
      RECT 10.395 0.485 10.625 3.255 ;
      RECT 7.715 0.95 7.945 2.6 ;
      RECT 6.345 0.51 6.575 3.04 ;
      RECT 5.485 0.51 5.715 3.04 ;
      RECT 2.725 0.51 2.955 3.04 ;
      RECT 0.145 0.51 0.375 3.04 ;
  END
  PROPERTY CatenaDesignType "deviceLevel" ;
END SDFFRX4_HS

MACRO SDFFSRX1_HS
  CLASS CORE ;
  ORIGIN 0 0 ;
  FOREIGN SDFFSRX1_HS 0 0 ;
  SIZE 14.72 BY 4.14 ;
  SYMMETRY X Y ;
  SITE CoreSite ;
  PIN CK
    DIRECTION INPUT ;
    USE SIGNAL ;
    ANTENNAMODEL OXIDE1 ;
      ANTENNAGATEAREA 0.18075 LAYER met1 ;
      ANTENNAMAXAREACAR 0.84177 LAYER met1 ;
      ANTENNAMAXSIDEAREACAR 0.990318 LAYER met1 ;
    PORT
      LAYER met1 ;
        RECT 2.17 2.02 2.43 3.26 ;
    END
  END CK
  PIN D
    DIRECTION INPUT ;
    USE SIGNAL ;
    ANTENNAMODEL OXIDE1 ;
      ANTENNAGATEAREA 0.18075 LAYER met1 ;
      ANTENNAMAXAREACAR 0.672476 LAYER met1 ;
      ANTENNAMAXSIDEAREACAR 0.791148 LAYER met1 ;
    PORT
      LAYER met1 ;
        RECT 0.79 2.46 1.05 3.7 ;
    END
  END D
  PIN Q
    DIRECTION OUTPUT ;
    USE SIGNAL ;
    ANTENNADIFFAREA 0.5883 LAYER met1 ;
    PORT
      LAYER met1 ;
        RECT 13.23 0.68 13.575 3.45 ;
        RECT 13.335 0.45 13.565 3.71 ;
    END
  END Q
  PIN QN
    DIRECTION OUTPUT ;
    USE SIGNAL ;
    ANTENNADIFFAREA 0.5883 LAYER met1 ;
    PORT
      LAYER met1 ;
        RECT 14.195 0.45 14.425 3.71 ;
        RECT 14.13 0.675 14.425 3.45 ;
    END
  END QN
  PIN RN
    DIRECTION INPUT ;
    USE SIGNAL ;
    ANTENNAMODEL OXIDE1 ;
      ANTENNAGATEAREA 0.18075 LAYER met1 ;
      ANTENNAMAXAREACAR 0.775934 LAYER met1 ;
      ANTENNAMAXSIDEAREACAR 0.912863 LAYER met1 ;
    PORT
      LAYER met1 ;
        RECT 3.55 1.145 3.81 2.385 ;
    END
  END RN
  PIN SE
    DIRECTION INPUT ;
    USE SIGNAL ;
    ANTENNAMODEL OXIDE1 ;
      ANTENNAGATEAREA 0.3615 LAYER met1 ;
      ANTENNAMAXAREACAR 0.874689 LAYER met1 ;
      ANTENNAMAXSIDEAREACAR 0.934993 LAYER met1 ;
    PORT
      LAYER met1 ;
        RECT 0.79 0.945 1.05 2.185 ;
    END
  END SE
  PIN SI
    DIRECTION INPUT ;
    USE SIGNAL ;
    ANTENNAMODEL OXIDE1 ;
      ANTENNAGATEAREA 0.18075 LAYER met1 ;
      ANTENNAMAXAREACAR 0.578423 LAYER met1 ;
      ANTENNAMAXSIDEAREACAR 0.680498 LAYER met1 ;
    PORT
      LAYER met1 ;
        RECT 2.17 0.635 2.43 1.875 ;
    END
  END SI
  PIN SN
    DIRECTION INPUT ;
    USE SIGNAL ;
    ANTENNAMODEL OXIDE1 ;
      ANTENNAGATEAREA 0.3615 LAYER met1 ;
      ANTENNAMAXAREACAR 0.799447 LAYER met1 ;
      ANTENNAMAXSIDEAREACAR 0.940526 LAYER met1 ;
    PORT
      LAYER met1 ;
        RECT 5.425 3.55 11.545 3.75 ;
        RECT 11.345 2.245 11.545 3.75 ;
        RECT 11.16 2.245 11.545 2.535 ;
        RECT 5.425 0.94 5.685 3.75 ;
    END
  END SN
  PIN VDD
    DIRECTION INPUT ;
    USE POWER ;
    SHAPE ABUTMENT ;
    NETEXPR "VDD VDD!" ;
    PORT
      LAYER met1 ;
        RECT 0 3.94 14.72 4.34 ;
    END
  END VDD
  PIN VSS
    DIRECTION INPUT ;
    USE GROUND ;
    SHAPE ABUTMENT ;
    NETEXPR "VSS VSS!" ;
    PORT
      LAYER met1 ;
        RECT 0 -0.2 14.72 0.2 ;
    END
  END VSS
  OBS
    LAYER met1 ;
      RECT 10.975 0.9 11.265 1.13 ;
      RECT 10.115 0.9 10.405 1.13 ;
      RECT 10.115 0.93 11.265 1.1 ;
      RECT 10.885 3.015 11.175 3.245 ;
      RECT 9.595 3.015 9.885 3.245 ;
      RECT 9.595 3.045 11.175 3.215 ;
      RECT 10.545 0.375 10.835 0.605 ;
      RECT 9.595 0.375 9.885 0.605 ;
      RECT 9.595 0.375 10.835 0.545 ;
      RECT 8.155 2.985 8.475 3.275 ;
      RECT 8.245 0.51 8.475 3.275 ;
      RECT 6.835 0.375 7.125 0.605 ;
      RECT 5.975 0.375 6.265 0.605 ;
      RECT 5.975 0.375 7.125 0.545 ;
      RECT 5.055 2.985 5.285 3.275 ;
      RECT 5.02 0.705 5.25 3.235 ;
      RECT 5.055 0.51 5.285 0.8 ;
      RECT 3.245 2.985 3.475 3.275 ;
      RECT 3.095 0.51 3.325 3.235 ;
      RECT 3.095 0.51 3.475 0.8 ;
      RECT 2.725 2.985 2.955 3.275 ;
      RECT 2.57 0.51 2.8 3.235 ;
      RECT 2.57 1.29 2.915 1.58 ;
      RECT 2.57 0.51 2.955 0.8 ;
      RECT 12.815 0.51 13.045 3.275 ;
      RECT 11.865 0.51 12.095 3.275 ;
      RECT 9.195 0.51 9.425 3.275 ;
      RECT 8.765 0.51 8.995 3.275 ;
      RECT 6.435 0.95 6.665 3.275 ;
      RECT 4.625 0.51 4.855 3.275 ;
      RECT 4.105 0.51 4.335 3.275 ;
      RECT 1.435 0.51 1.665 3.275 ;
      RECT 0.145 0.51 0.375 3.275 ;
  END
  PROPERTY CatenaDesignType "deviceLevel" ;
  PROPERTY oaTaper "virtuosoDefaultSetup" ;
END SDFFSRX1_HS

MACRO SDFFSRX4_HS
  CLASS CORE ;
  ORIGIN 0 0 ;
  FOREIGN SDFFSRX4_HS 0 0 ;
  SIZE 17.48 BY 4.14 ;
  SYMMETRY X Y ;
  SITE CoreSite ;
  PIN CK
    DIRECTION INPUT ;
    USE SIGNAL ;
    ANTENNAMODEL OXIDE1 ;
      ANTENNAGATEAREA 0.18075 LAYER met1 ;
      ANTENNAMAXAREACAR 0.84177 LAYER met1 ;
      ANTENNAMAXSIDEAREACAR 0.990318 LAYER met1 ;
    PORT
      LAYER met1 ;
        RECT 2.17 2.02 2.43 3.26 ;
        RECT 2.185 1.83 2.415 3.26 ;
    END
  END CK
  PIN D
    DIRECTION INPUT ;
    USE SIGNAL ;
    ANTENNAMODEL OXIDE1 ;
      ANTENNAGATEAREA 0.18075 LAYER met1 ;
      ANTENNAMAXAREACAR 0.503181 LAYER met1 ;
      ANTENNAMAXSIDEAREACAR 0.591978 LAYER met1 ;
    PORT
      LAYER met1 ;
        RECT 0.79 2.36 1.05 3.6 ;
        RECT 0.805 2.31 1.035 3.6 ;
    END
  END D
  PIN Q
    DIRECTION OUTPUT ;
    USE SIGNAL ;
    ANTENNADIFFAREA 1.2432 LAYER met1 ;
    PORT
      LAYER met1 ;
        RECT 14.59 0.68 14.935 3.45 ;
        RECT 14.595 0.485 14.825 3.45 ;
        RECT 13.735 1.77 14.935 2 ;
        RECT 13.735 0.485 13.965 3.45 ;
    END
  END Q
  PIN QN
    DIRECTION OUTPUT ;
    USE SIGNAL ;
    ANTENNADIFFAREA 1.2432 LAYER met1 ;
    PORT
      LAYER met1 ;
        RECT 16.315 0.68 16.69 3.455 ;
        RECT 16.315 0.485 16.545 3.455 ;
        RECT 15.455 1.77 16.69 2 ;
        RECT 15.455 0.485 15.685 3.45 ;
    END
  END QN
  PIN RN
    DIRECTION INPUT ;
    USE SIGNAL ;
    ANTENNAMODEL OXIDE1 ;
      ANTENNAGATEAREA 0.18075 LAYER met1 ;
      ANTENNAMAXAREACAR 0.775934 LAYER met1 ;
      ANTENNAMAXSIDEAREACAR 0.912863 LAYER met1 ;
    PORT
      LAYER met1 ;
        RECT 3.55 1.145 3.81 2.385 ;
    END
  END RN
  PIN SE
    DIRECTION INPUT ;
    USE SIGNAL ;
    ANTENNAMODEL OXIDE1 ;
      ANTENNAGATEAREA 0.3615 LAYER met1 ;
      ANTENNAMAXAREACAR 0.884094 LAYER met1 ;
      ANTENNAMAXSIDEAREACAR 0.946058 LAYER met1 ;
    PORT
      LAYER met1 ;
        RECT 0.79 0.945 1.05 2.1 ;
    END
  END SE
  PIN SI
    DIRECTION INPUT ;
    USE SIGNAL ;
    ANTENNAMODEL OXIDE1 ;
      ANTENNAGATEAREA 0.18075 LAYER met1 ;
      ANTENNAMAXAREACAR 0.578423 LAYER met1 ;
      ANTENNAMAXSIDEAREACAR 0.680498 LAYER met1 ;
    PORT
      LAYER met1 ;
        RECT 2.17 0.635 2.43 1.64 ;
    END
  END SI
  PIN SN
    DIRECTION INPUT ;
    USE SIGNAL ;
    ANTENNAMODEL OXIDE1 ;
      ANTENNAGATEAREA 0.3615 LAYER met1 ;
      ANTENNAMAXAREACAR 0.818257 LAYER met1 ;
      ANTENNAMAXSIDEAREACAR 0.962656 LAYER met1 ;
    PORT
      LAYER met1 ;
        RECT 5.56 3.39 11.545 3.59 ;
        RECT 11.345 2.21 11.545 3.59 ;
        RECT 11.025 2.21 11.545 2.41 ;
        RECT 11.025 2.12 11.255 2.41 ;
        RECT 5.56 1.145 5.79 3.59 ;
        RECT 5.405 0.95 5.635 2.385 ;
        RECT 5.39 1.145 5.79 2.385 ;
    END
  END SN
  PIN VDD
    DIRECTION INPUT ;
    USE POWER ;
    SHAPE ABUTMENT ;
    NETEXPR "VDD VDD!" ;
    PORT
      LAYER met1 ;
        RECT 0 3.94 17.48 4.34 ;
    END
  END VDD
  PIN VSS
    DIRECTION INPUT ;
    USE GROUND ;
    SHAPE ABUTMENT ;
    NETEXPR "VSS VSS!" ;
    PORT
      LAYER met1 ;
        RECT 0 -0.2 17.48 0.2 ;
    END
  END VSS
  OBS
    LAYER met1 ;
      RECT 8.155 2.945 8.475 3.235 ;
      RECT 8.245 0.51 8.475 3.235 ;
      RECT 5.02 2.945 5.285 3.235 ;
      RECT 5.02 0.705 5.25 3.235 ;
      RECT 5.055 0.51 5.285 0.8 ;
      RECT 3.18 2.945 3.475 3.235 ;
      RECT 3.18 0.705 3.41 3.235 ;
      RECT 3.245 0.51 3.475 0.8 ;
      RECT 12.875 0.485 13.105 3.45 ;
      RECT 11.925 0.685 12.155 3.315 ;
      RECT 10.115 0.8 11.265 1.03 ;
      RECT 9.595 2.975 11.175 3.205 ;
      RECT 9.595 0.375 10.835 0.605 ;
      RECT 9.195 0.51 9.425 3.235 ;
      RECT 8.765 0.51 8.995 3.235 ;
      RECT 5.975 0.375 7.125 0.605 ;
      RECT 6.435 0.95 6.665 3.235 ;
      RECT 4.625 0.51 4.855 3.235 ;
      RECT 4.105 0.51 4.335 3.235 ;
      RECT 2.725 0.51 2.955 3.235 ;
      RECT 1.435 0.51 1.665 3.235 ;
      RECT 0.145 0.51 0.375 3.235 ;
  END
  PROPERTY CatenaDesignType "deviceLevel" ;
END SDFFSRX4_HS

MACRO SDFFSX1_HS
  CLASS CORE ;
  ORIGIN 0 0 ;
  FOREIGN SDFFSX1_HS 0 0 ;
  SIZE 11.5 BY 4.14 ;
  SYMMETRY X Y ;
  SITE CoreSite ;
  PIN CK
    DIRECTION INPUT ;
    USE SIGNAL ;
    ANTENNAMODEL OXIDE1 ;
      ANTENNAGATEAREA 0.18075 LAYER met1 ;
      ANTENNAMAXAREACAR 0.775934 LAYER met1 ;
      ANTENNAMAXSIDEAREACAR 0.912863 LAYER met1 ;
    PORT
      LAYER met1 ;
        RECT 2.17 0.4 2.43 1.64 ;
    END
  END CK
  PIN D
    DIRECTION INPUT ;
    USE SIGNAL ;
    ANTENNAMODEL OXIDE1 ;
      ANTENNAGATEAREA 0.18075 LAYER met1 ;
      ANTENNAMAXAREACAR 0.672476 LAYER met1 ;
      ANTENNAMAXSIDEAREACAR 0.791148 LAYER met1 ;
    PORT
      LAYER met1 ;
        RECT 0.79 1.955 1.05 3.195 ;
    END
  END D
  PIN Q
    DIRECTION OUTPUT ;
    USE SIGNAL ;
    ANTENNADIFFAREA 0.5883 LAYER met1 ;
    PORT
      LAYER met1 ;
        RECT 9.965 0.485 10.31 3.255 ;
    END
  END Q
  PIN QN
    DIRECTION OUTPUT ;
    USE SIGNAL ;
    ANTENNADIFFAREA 0.5883 LAYER met1 ;
    PORT
      LAYER met1 ;
        RECT 10.825 0.48 11.17 3.255 ;
    END
  END QN
  PIN SE
    DIRECTION INPUT ;
    USE SIGNAL ;
    ANTENNAMODEL OXIDE1 ;
      ANTENNAGATEAREA 0.3615 LAYER met1 ;
      ANTENNAMAXAREACAR 0.942877 LAYER met1 ;
      ANTENNAMAXSIDEAREACAR 1.015214 LAYER met1 ;
    PORT
      LAYER met1 ;
        RECT 0.79 0.55 1.05 1.79 ;
    END
  END SE
  PIN SI
    DIRECTION INPUT ;
    USE SIGNAL ;
    ANTENNAMODEL OXIDE1 ;
      ANTENNAGATEAREA 0.18075 LAYER met1 ;
      ANTENNAMAXAREACAR 0.771231 LAYER met1 ;
      ANTENNAMAXSIDEAREACAR 0.907331 LAYER met1 ;
    PORT
      LAYER met1 ;
        RECT 2.17 1.785 2.43 3.025 ;
    END
  END SI
  PIN SN
    DIRECTION INPUT ;
    USE SIGNAL ;
    ANTENNAMODEL OXIDE1 ;
      ANTENNAGATEAREA 0.3615 LAYER met1 ;
      ANTENNAMAXAREACAR 1.493084 LAYER met1 ;
      ANTENNAMAXSIDEAREACAR 1.662517 LAYER met1 ;
    PORT
      LAYER met1 ;
        RECT 5.39 1.29 5.65 2.53 ;
    END
  END SN
  PIN VDD
    DIRECTION INPUT ;
    USE POWER ;
    SHAPE ABUTMENT ;
    NETEXPR "VDD VDD!" ;
    PORT
      LAYER met1 ;
        RECT 0 3.94 11.5 4.34 ;
    END
  END VDD
  PIN VSS
    DIRECTION INPUT ;
    USE GROUND ;
    SHAPE ABUTMENT ;
    NETEXPR "VSS VSS!" ;
    PORT
      LAYER met1 ;
        RECT 0 -0.2 11.5 0.2 ;
    END
  END VSS
  OBS
    LAYER met1 ;
      RECT 5.485 2.81 6.575 3.04 ;
      RECT 6.345 0.51 6.575 3.04 ;
      RECT 5.485 2.75 5.715 3.04 ;
      RECT 3.675 0.51 3.905 3.04 ;
      RECT 5.915 0.51 6.145 2.6 ;
      RECT 3.675 0.51 6.145 0.74 ;
      RECT 1.435 3.18 3.475 3.41 ;
      RECT 3.245 0.51 3.475 3.41 ;
      RECT 1.435 0.51 1.665 3.41 ;
      RECT 9.445 0.51 9.675 3.04 ;
      RECT 8.585 0.51 8.815 3.04 ;
      RECT 7.175 2.78 8.325 3.01 ;
      RECT 7.205 0.95 7.435 2.6 ;
      RECT 6.775 0.51 7.005 3.04 ;
      RECT 4.965 0.95 5.195 3.04 ;
      RECT 2.725 0.51 2.955 3.04 ;
      RECT 0.145 0.51 0.375 3.04 ;
  END
  PROPERTY CatenaDesignType "deviceLevel" ;
END SDFFSX1_HS

MACRO SDFFSX4_HS
  CLASS CORE ;
  ORIGIN 0 0 ;
  FOREIGN SDFFSX4_HS 0 0 ;
  SIZE 14.26 BY 4.14 ;
  SYMMETRY X Y ;
  SITE CoreSite ;
  PIN CK
    DIRECTION INPUT ;
    USE SIGNAL ;
    ANTENNAMODEL OXIDE1 ;
      ANTENNAGATEAREA 0.18075 LAYER met1 ;
      ANTENNAMAXAREACAR 0.775934 LAYER met1 ;
      ANTENNAMAXSIDEAREACAR 0.912863 LAYER met1 ;
    PORT
      LAYER met1 ;
        RECT 2.17 0.4 2.43 1.64 ;
    END
  END CK
  PIN D
    DIRECTION INPUT ;
    USE SIGNAL ;
    ANTENNAMODEL OXIDE1 ;
      ANTENNAGATEAREA 0.18075 LAYER met1 ;
      ANTENNAMAXAREACAR 0.672476 LAYER met1 ;
      ANTENNAMAXSIDEAREACAR 0.791148 LAYER met1 ;
    PORT
      LAYER met1 ;
        RECT 0.79 1.955 1.05 3.195 ;
    END
  END D
  PIN Q
    DIRECTION OUTPUT ;
    USE SIGNAL ;
    ANTENNADIFFAREA 1.2432 LAYER met1 ;
    PORT
      LAYER met1 ;
        RECT 11.685 0.485 12.09 3.255 ;
        RECT 10.825 1.575 12.09 1.805 ;
        RECT 10.825 0.485 11.055 3.255 ;
    END
  END Q
  PIN QN
    DIRECTION OUTPUT ;
    USE SIGNAL ;
    ANTENNADIFFAREA 1.2432 LAYER met1 ;
    PORT
      LAYER met1 ;
        RECT 13.405 0.48 13.93 3.255 ;
        RECT 12.545 1.575 13.93 1.805 ;
        RECT 12.545 0.485 12.775 3.255 ;
    END
  END QN
  PIN SE
    DIRECTION INPUT ;
    USE SIGNAL ;
    ANTENNAMODEL OXIDE1 ;
      ANTENNAGATEAREA 0.3615 LAYER met1 ;
      ANTENNAMAXAREACAR 0.942877 LAYER met1 ;
      ANTENNAMAXSIDEAREACAR 1.015214 LAYER met1 ;
    PORT
      LAYER met1 ;
        RECT 0.79 0.55 1.05 1.79 ;
    END
  END SE
  PIN SI
    DIRECTION INPUT ;
    USE SIGNAL ;
    ANTENNAMODEL OXIDE1 ;
      ANTENNAGATEAREA 0.18075 LAYER met1 ;
      ANTENNAMAXAREACAR 0.771231 LAYER met1 ;
      ANTENNAMAXSIDEAREACAR 0.907331 LAYER met1 ;
    PORT
      LAYER met1 ;
        RECT 2.17 1.785 2.43 3.025 ;
    END
  END SI
  PIN SN
    DIRECTION INPUT ;
    USE SIGNAL ;
    ANTENNAMODEL OXIDE1 ;
      ANTENNAGATEAREA 0.3615 LAYER met1 ;
      ANTENNAMAXAREACAR 1.493084 LAYER met1 ;
      ANTENNAMAXSIDEAREACAR 1.662517 LAYER met1 ;
    PORT
      LAYER met1 ;
        RECT 5.39 1.29 5.65 2.53 ;
    END
  END SN
  PIN VDD
    DIRECTION INPUT ;
    USE POWER ;
    SHAPE ABUTMENT ;
    NETEXPR "VDD VDD!" ;
    PORT
      LAYER met1 ;
        RECT 0 3.94 14.265 4.34 ;
    END
  END VDD
  PIN VSS
    DIRECTION INPUT ;
    USE GROUND ;
    SHAPE ABUTMENT ;
    NETEXPR "VSS VSS!" ;
    PORT
      LAYER met1 ;
        RECT 0 -0.2 14.265 0.2 ;
    END
  END VSS
  OBS
    LAYER met1 ;
      RECT 5.485 2.81 6.575 3.04 ;
      RECT 6.345 0.51 6.575 3.04 ;
      RECT 5.485 2.75 5.715 3.04 ;
      RECT 3.675 0.51 3.905 3.04 ;
      RECT 5.915 0.51 6.145 2.6 ;
      RECT 3.675 0.51 6.145 0.74 ;
      RECT 1.435 3.18 3.475 3.41 ;
      RECT 3.245 0.51 3.475 3.41 ;
      RECT 1.435 0.51 1.665 3.41 ;
      RECT 9.965 0.485 10.195 3.255 ;
      RECT 9.015 0.685 9.245 3.12 ;
      RECT 7.175 2.78 8.325 3.01 ;
      RECT 7.205 0.95 7.435 2.6 ;
      RECT 6.775 0.51 7.005 3.04 ;
      RECT 4.965 0.95 5.195 3.04 ;
      RECT 2.725 0.51 2.955 3.04 ;
      RECT 0.145 0.51 0.375 3.04 ;
  END
  PROPERTY CatenaDesignType "deviceLevel" ;
END SDFFSX4_HS

MACRO SDFFX1_HS
  CLASS CORE ;
  ORIGIN 0 0 ;
  FOREIGN SDFFX1_HS 0 0 ;
  SIZE 10.58 BY 4.14 ;
  SYMMETRY X Y ;
  SITE CoreSite ;
  PIN CK
    DIRECTION INPUT ;
    USE SIGNAL ;
    ANTENNAMODEL OXIDE1 ;
      ANTENNAGATEAREA 0.18075 LAYER met1 ;
      ANTENNAMAXAREACAR 0.775934 LAYER met1 ;
      ANTENNAMAXSIDEAREACAR 0.912863 LAYER met1 ;
    PORT
      LAYER met1 ;
        RECT 2.17 0.4 2.43 1.64 ;
    END
  END CK
  PIN D
    DIRECTION INPUT ;
    USE SIGNAL ;
    ANTENNAMODEL OXIDE1 ;
      ANTENNAGATEAREA 0.18075 LAYER met1 ;
      ANTENNAMAXAREACAR 0.672476 LAYER met1 ;
      ANTENNAMAXSIDEAREACAR 0.791148 LAYER met1 ;
    PORT
      LAYER met1 ;
        RECT 0.79 1.955 1.05 3.195 ;
    END
  END D
  PIN Q
    DIRECTION OUTPUT ;
    USE SIGNAL ;
    ANTENNADIFFAREA 0.5883 LAYER met1 ;
    PORT
      LAYER met1 ;
        RECT 9.045 0.485 9.39 3.26 ;
    END
  END Q
  PIN QN
    DIRECTION OUTPUT ;
    USE SIGNAL ;
    ANTENNADIFFAREA 0.5883 LAYER met1 ;
    PORT
      LAYER met1 ;
        RECT 9.905 0.48 10.25 3.255 ;
    END
  END QN
  PIN SE
    DIRECTION INPUT ;
    USE SIGNAL ;
    ANTENNAMODEL OXIDE1 ;
      ANTENNAGATEAREA 0.3615 LAYER met1 ;
      ANTENNAMAXAREACAR 0.924066 LAYER met1 ;
      ANTENNAMAXSIDEAREACAR 0.993084 LAYER met1 ;
    PORT
      LAYER met1 ;
        RECT 0.79 0.55 1.05 1.79 ;
    END
  END SE
  PIN SI
    DIRECTION INPUT ;
    USE SIGNAL ;
    ANTENNAMODEL OXIDE1 ;
      ANTENNAGATEAREA 0.18075 LAYER met1 ;
      ANTENNAMAXAREACAR 0.771231 LAYER met1 ;
      ANTENNAMAXSIDEAREACAR 0.907331 LAYER met1 ;
    PORT
      LAYER met1 ;
        RECT 2.17 1.785 2.43 3.025 ;
    END
  END SI
  PIN VDD
    DIRECTION INPUT ;
    USE POWER ;
    SHAPE ABUTMENT ;
    NETEXPR "VDD VDD!" ;
    PORT
      LAYER met1 ;
        RECT 0 3.94 10.58 4.34 ;
    END
  END VDD
  PIN VSS
    DIRECTION INPUT ;
    USE GROUND ;
    SHAPE ABUTMENT ;
    NETEXPR "VSS VSS!" ;
    PORT
      LAYER met1 ;
        RECT 0 -0.2 10.58 0.2 ;
    END
  END VSS
  OBS
    LAYER met1 ;
      RECT 3.675 3.18 5.715 3.41 ;
      RECT 5.485 2.28 5.715 3.41 ;
      RECT 3.675 0.51 3.905 3.41 ;
      RECT 1.435 3.18 3.475 3.41 ;
      RECT 3.245 0.51 3.475 3.41 ;
      RECT 1.435 0.51 1.665 3.41 ;
      RECT 8.585 0.685 8.815 3.335 ;
      RECT 7.725 0.485 7.955 3.335 ;
      RECT 6.775 0.95 7.005 2.6 ;
      RECT 6.345 0.51 6.575 3.04 ;
      RECT 5.915 0.51 6.145 3.04 ;
      RECT 4.965 0.51 5.195 3.04 ;
      RECT 2.725 0.51 2.955 3.04 ;
      RECT 0.145 0.51 0.375 3.04 ;
  END
  PROPERTY CatenaDesignType "deviceLevel" ;
END SDFFX1_HS

MACRO SDFFX4_HS
  CLASS CORE ;
  ORIGIN 0 0 ;
  FOREIGN SDFFX4_HS 0 0 ;
  SIZE 13.34 BY 4.14 ;
  SYMMETRY X Y ;
  SITE CoreSite ;
  PIN CK
    DIRECTION INPUT ;
    USE SIGNAL ;
    ANTENNAMODEL OXIDE1 ;
      ANTENNAGATEAREA 0.18075 LAYER met1 ;
      ANTENNAMAXAREACAR 0.775934 LAYER met1 ;
      ANTENNAMAXSIDEAREACAR 0.912863 LAYER met1 ;
    PORT
      LAYER met1 ;
        RECT 2.17 0.4 2.43 1.64 ;
    END
  END CK
  PIN D
    DIRECTION INPUT ;
    USE SIGNAL ;
    ANTENNAMODEL OXIDE1 ;
      ANTENNAGATEAREA 0.18075 LAYER met1 ;
      ANTENNAMAXAREACAR 0.672476 LAYER met1 ;
      ANTENNAMAXSIDEAREACAR 0.791148 LAYER met1 ;
    PORT
      LAYER met1 ;
        RECT 0.79 1.955 1.05 3.195 ;
    END
  END D
  PIN Q
    DIRECTION OUTPUT ;
    USE SIGNAL ;
    ANTENNADIFFAREA 1.2432 LAYER met1 ;
    PORT
      LAYER met1 ;
        RECT 10.365 0.48 10.71 3.255 ;
        RECT 9.505 1.575 10.71 1.805 ;
        RECT 9.505 0.485 9.735 3.255 ;
    END
  END Q
  PIN QN
    DIRECTION OUTPUT ;
    USE SIGNAL ;
    ANTENNADIFFAREA 1.2432 LAYER met1 ;
    PORT
      LAYER met1 ;
        RECT 12.085 0.48 12.55 3.255 ;
        RECT 11.225 1.575 12.55 1.805 ;
        RECT 11.225 0.485 11.455 3.255 ;
    END
  END QN
  PIN SE
    DIRECTION INPUT ;
    USE SIGNAL ;
    ANTENNAMODEL OXIDE1 ;
      ANTENNAGATEAREA 0.3615 LAYER met1 ;
      ANTENNAMAXAREACAR 0.942877 LAYER met1 ;
      ANTENNAMAXSIDEAREACAR 1.015214 LAYER met1 ;
    PORT
      LAYER met1 ;
        RECT 0.79 0.55 1.05 1.79 ;
    END
  END SE
  PIN SI
    DIRECTION INPUT ;
    USE SIGNAL ;
    ANTENNAMODEL OXIDE1 ;
      ANTENNAGATEAREA 0.18075 LAYER met1 ;
      ANTENNAMAXAREACAR 0.771231 LAYER met1 ;
      ANTENNAMAXSIDEAREACAR 0.907331 LAYER met1 ;
    PORT
      LAYER met1 ;
        RECT 2.17 1.785 2.43 3.025 ;
    END
  END SI
  PIN VDD
    DIRECTION INPUT ;
    USE POWER ;
    SHAPE ABUTMENT ;
    NETEXPR "VDD VDD!" ;
    PORT
      LAYER met1 ;
        RECT 0 3.94 13.34 4.34 ;
    END
  END VDD
  PIN VSS
    DIRECTION INPUT ;
    USE GROUND ;
    SHAPE ABUTMENT ;
    NETEXPR "VSS VSS!" ;
    PORT
      LAYER met1 ;
        RECT 0 -0.2 13.34 0.2 ;
    END
  END VSS
  OBS
    LAYER met1 ;
      RECT 3.675 3.18 5.715 3.41 ;
      RECT 5.485 2.28 5.715 3.41 ;
      RECT 3.675 0.51 3.905 3.41 ;
      RECT 1.435 3.18 3.475 3.41 ;
      RECT 3.245 0.51 3.475 3.41 ;
      RECT 1.435 0.51 1.665 3.41 ;
      RECT 8.645 0.485 8.875 3.255 ;
      RECT 7.695 0.685 7.925 3.12 ;
      RECT 6.775 0.95 7.005 2.6 ;
      RECT 6.345 0.51 6.575 3.04 ;
      RECT 5.915 0.51 6.145 3.04 ;
      RECT 4.965 0.51 5.195 3.04 ;
      RECT 2.725 0.51 2.955 3.04 ;
      RECT 0.145 0.51 0.375 3.04 ;
  END
  PROPERTY CatenaDesignType "deviceLevel" ;
END SDFFX4_HS

MACRO TBUFX1_HS
  CLASS CORE ;
  ORIGIN 0 0 ;
  FOREIGN TBUFX1_HS 0 0 ;
  SIZE 3.68 BY 4.14 ;
  SYMMETRY X Y ;
  SITE CoreSite ;
  PIN A
    DIRECTION INPUT ;
    USE SIGNAL ;
    ANTENNAMODEL OXIDE1 ;
      ANTENNAGATEAREA 0.3615 LAYER met1 ;
      ANTENNAMAXAREACAR 0.754772 LAYER met1 ;
      ANTENNAMAXSIDEAREACAR 0.793914 LAYER met1 ;
    PORT
      LAYER met1 ;
        RECT 1.71 1.47 1.97 2.71 ;
    END
  END A
  PIN OE
    DIRECTION INPUT ;
    USE SIGNAL ;
    ANTENNAMODEL OXIDE1 ;
      ANTENNAGATEAREA 0.3615 LAYER met1 ;
      ANTENNAMAXAREACAR 1.194467 LAYER met1 ;
      ANTENNAMAXSIDEAREACAR 1.311203 LAYER met1 ;
    PORT
      LAYER met1 ;
        RECT 0.79 1.655 1.05 2.895 ;
    END
  END OE
  PIN VDD
    DIRECTION INPUT ;
    USE POWER ;
    SHAPE ABUTMENT ;
    NETEXPR "VDD VDD!" ;
    PORT
      LAYER met1 ;
        RECT 0 3.94 3.68 4.34 ;
    END
  END VDD
  PIN VSS
    DIRECTION INPUT ;
    USE GROUND ;
    SHAPE ABUTMENT ;
    NETEXPR "VSS VSS!" ;
    PORT
      LAYER met1 ;
        RECT 0 -0.2 3.68 0.2 ;
    END
  END VSS
  PIN Y
    DIRECTION OUTPUT ;
    USE SIGNAL ;
    ANTENNADIFFAREA 0.5883 LAYER met1 ;
    PORT
      LAYER met1 ;
        RECT 3.09 2.325 3.535 3.335 ;
        RECT 3.09 0.415 3.535 1.065 ;
        RECT 3.09 0.415 3.35 3.335 ;
    END
  END Y
  OBS
    LAYER met1 ;
      RECT 2.385 3.045 2.615 3.335 ;
      RECT 2.43 0.59 2.57 3.335 ;
      RECT 2.385 1.625 2.615 1.915 ;
      RECT 2.375 0.59 2.605 0.88 ;
      RECT 1.435 3.045 1.665 3.335 ;
      RECT 1.43 0.49 1.57 3.19 ;
      RECT 1.34 1.285 1.57 1.575 ;
      RECT 1.005 0.415 1.235 0.705 ;
      RECT 1.005 0.49 1.62 0.63 ;
      RECT 0.145 3.045 0.375 3.335 ;
      RECT 0.175 0.415 0.345 3.335 ;
      RECT 0.145 1.625 0.375 1.915 ;
      RECT 0.145 0.415 0.375 0.705 ;
  END
  PROPERTY CatenaDesignType "deviceLevel" ;
END TBUFX1_HS

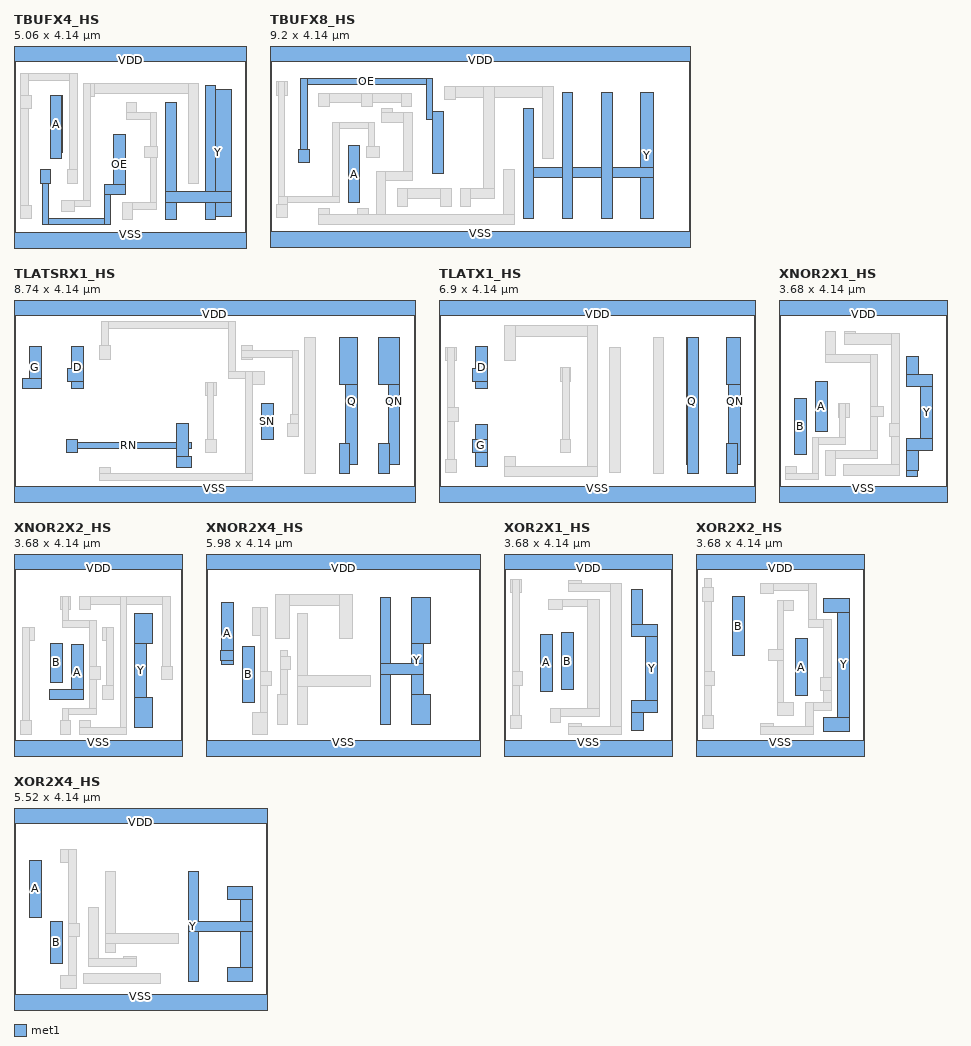
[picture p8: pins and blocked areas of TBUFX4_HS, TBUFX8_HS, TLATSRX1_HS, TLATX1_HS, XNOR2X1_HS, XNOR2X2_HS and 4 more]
MACRO TBUFX4_HS
  CLASS CORE ;
  ORIGIN 0 0 ;
  FOREIGN TBUFX4_HS 0 0 ;
  SIZE 5.06 BY 4.14 ;
  SYMMETRY X Y ;
  SITE CoreSite ;
  PIN A
    DIRECTION INPUT ;
    USE SIGNAL ;
    ANTENNAMODEL OXIDE1 ;
      ANTENNAGATEAREA 0.666 LAYER met1 ;
      ANTENNAMAXAREACAR 0.670045 LAYER met1 ;
      ANTENNAMAXSIDEAREACAR 0.635135 LAYER met1 ;
    PORT
      LAYER met1 ;
        RECT 0.79 1.95 1.05 3.19 ;
        RECT 0.805 1.815 1.035 3.19 ;
    END
  END A
  PIN OE
    DIRECTION INPUT ;
    USE SIGNAL ;
    ANTENNAMODEL OXIDE1 ;
      ANTENNAGATEAREA 0.51375 LAYER met1 ;
      ANTENNAMAXAREACAR 0.663071 LAYER met1 ;
      ANTENNAMAXSIDEAREACAR 0.780083 LAYER met1 ;
    PORT
      LAYER met1 ;
        RECT 2.17 1.025 2.43 2.35 ;
        RECT 1.97 1.025 2.43 1.255 ;
        RECT 1.97 0.375 2.11 1.255 ;
        RECT 0.62 0.375 2.11 0.515 ;
        RECT 0.575 1.285 0.805 1.575 ;
        RECT 0.62 0.375 0.76 1.575 ;
    END
  END OE
  PIN VDD
    DIRECTION INPUT ;
    USE POWER ;
    SHAPE ABUTMENT ;
    NETEXPR "VDD VDD!" ;
    PORT
      LAYER met1 ;
        RECT 0 3.94 5.06 4.34 ;
    END
  END VDD
  PIN VSS
    DIRECTION INPUT ;
    USE GROUND ;
    SHAPE ABUTMENT ;
    NETEXPR "VSS VSS!" ;
    PORT
      LAYER met1 ;
        RECT 0 -0.2 5.06 0.2 ;
    END
  END VSS
  PIN Y
    DIRECTION OUTPUT ;
    USE SIGNAL ;
    ANTENNADIFFAREA 1.2432 LAYER met1 ;
    PORT
      LAYER met1 ;
        RECT 4.165 0.56 4.73 3.33 ;
        RECT 4.165 0.485 4.395 3.405 ;
        RECT 3.305 0.865 4.73 1.095 ;
        RECT 3.305 0.485 3.535 3.045 ;
    END
  END Y
  OBS
    LAYER met1 ;
      RECT 1.525 3.225 4.025 3.455 ;
      RECT 3.795 1.285 4.025 3.455 ;
      RECT 1.525 3.165 1.755 3.455 ;
      RECT 1.525 0.775 1.665 3.455 ;
      RECT 1.035 0.775 1.665 0.915 ;
      RECT 1.035 0.655 1.325 0.915 ;
      RECT 2.445 2.68 2.675 3.045 ;
      RECT 2.445 2.68 3.105 2.82 ;
      RECT 2.965 0.71 3.105 2.82 ;
      RECT 2.845 1.845 3.135 2.075 ;
      RECT 2.355 0.71 3.105 0.85 ;
      RECT 2.355 0.485 2.585 0.85 ;
      RECT 0.145 3.51 1.385 3.68 ;
      RECT 1.215 1.285 1.385 3.68 ;
      RECT 0.145 0.51 0.315 3.68 ;
      RECT 0.145 2.9 0.375 3.19 ;
      RECT 1.155 1.285 1.385 1.575 ;
      RECT 0.145 0.51 0.375 0.8 ;
  END
  PROPERTY CatenaDesignType "deviceLevel" ;
END TBUFX4_HS

MACRO TBUFX8_HS
  CLASS CORE ;
  ORIGIN 0 0 ;
  FOREIGN TBUFX8_HS 0 0 ;
  SIZE 9.2 BY 4.14 ;
  SYMMETRY X Y ;
  SITE CoreSite ;
  PIN A
    DIRECTION INPUT ;
    USE SIGNAL ;
    ANTENNAMODEL OXIDE1 ;
      ANTENNAGATEAREA 1.332 LAYER met1 ;
      ANTENNAMAXAREACAR 0.426914 LAYER met1 ;
      ANTENNAMAXSIDEAREACAR 0.425676 LAYER met1 ;
    PORT
      LAYER met1 ;
        RECT 1.71 0.845 1.97 2.085 ;
    END
  END A
  PIN OE
    DIRECTION INPUT ;
    USE SIGNAL ;
    ANTENNAMODEL OXIDE1 ;
      ANTENNAGATEAREA 0.84675 LAYER met1 ;
      ANTENNAMAXAREACAR 0.799447 LAYER met1 ;
      ANTENNAMAXSIDEAREACAR 0.940526 LAYER met1 ;
    PORT
      LAYER met1 ;
        RECT 3.55 1.485 3.81 2.845 ;
        RECT 0.675 3.42 3.57 3.56 ;
        RECT 3.43 2.66 3.57 3.56 ;
        RECT 0.63 1.725 0.86 2.015 ;
        RECT 0.675 1.725 0.815 3.56 ;
    END
  END OE
  PIN VDD
    DIRECTION INPUT ;
    USE POWER ;
    SHAPE ABUTMENT ;
    NETEXPR "VDD VDD!" ;
    PORT
      LAYER met1 ;
        RECT 0 3.94 9.2 4.34 ;
    END
  END VDD
  PIN VSS
    DIRECTION INPUT ;
    USE GROUND ;
    SHAPE ABUTMENT ;
    NETEXPR "VSS VSS!" ;
    PORT
      LAYER met1 ;
        RECT 0 -0.2 9.2 0.2 ;
    END
  END VSS
  PIN Y
    DIRECTION OUTPUT ;
    USE SIGNAL ;
    ANTENNADIFFAREA 2.4864 LAYER met1 ;
    PORT
      LAYER met1 ;
        RECT 8.125 0.485 8.41 3.255 ;
        RECT 5.545 1.385 8.41 1.615 ;
        RECT 7.265 0.485 7.495 3.255 ;
        RECT 6.405 0.485 6.635 3.255 ;
        RECT 5.545 0.485 5.775 2.895 ;
    END
  END Y
  OBS
    LAYER met1 ;
      RECT 3.825 3.15 6.205 3.38 ;
      RECT 5.975 1.805 6.205 3.38 ;
      RECT 4.685 0.925 4.915 3.38 ;
      RECT 3.825 3.09 4.055 3.38 ;
      RECT 4.165 0.925 4.915 1.155 ;
      RECT 4.165 0.75 4.395 1.155 ;
      RECT 2.445 2.605 2.675 2.895 ;
      RECT 2.445 2.605 3.12 2.805 ;
      RECT 2.92 1.33 3.12 2.805 ;
      RECT 5.115 0.36 5.345 1.575 ;
      RECT 2.34 1.33 3.12 1.53 ;
      RECT 2.34 0.36 2.54 1.53 ;
      RECT 1.925 0.36 2.155 0.705 ;
      RECT 1.065 0.36 1.295 0.705 ;
      RECT 1.065 0.36 5.345 0.59 ;
      RECT 2.785 0.93 3.965 1.16 ;
      RECT 3.735 0.75 3.965 1.16 ;
      RECT 2.785 0.75 3.015 1.16 ;
      RECT 1.065 3.035 3.105 3.235 ;
      RECT 2.875 2.945 3.105 3.235 ;
      RECT 2.015 2.945 2.245 3.235 ;
      RECT 1.065 2.945 1.295 3.235 ;
      RECT 0.145 3.195 0.375 3.485 ;
      RECT 0.185 0.51 0.325 3.485 ;
      RECT 1.375 2.46 2.295 2.6 ;
      RECT 2.155 1.835 2.295 2.6 ;
      RECT 1.375 0.845 1.515 2.6 ;
      RECT 2.11 1.835 2.4 2.065 ;
      RECT 0.185 0.845 1.515 0.985 ;
      RECT 0.185 0.51 0.375 0.985 ;
      RECT 0.145 0.51 0.375 0.8 ;
  END
  PROPERTY CatenaDesignType "deviceLevel" ;
END TBUFX8_HS

MACRO TLATSRX1_HS
  CLASS CORE ;
  ORIGIN 0 0 ;
  FOREIGN TLATSRX1_HS 0 0 ;
  SIZE 8.74 BY 4.14 ;
  SYMMETRY X Y ;
  SITE CoreSite ;
  PIN D
    DIRECTION INPUT ;
    USE SIGNAL ;
    ANTENNAMODEL OXIDE1 ;
      ANTENNAGATEAREA 0.18075 LAYER met1 ;
      ANTENNAMAXAREACAR 0.780636 LAYER met1 ;
      ANTENNAMAXSIDEAREACAR 0.918396 LAYER met1 ;
    PORT
      LAYER met1 ;
        RECT 1.25 2.34 1.51 3.255 ;
        RECT 1.165 2.495 1.51 2.785 ;
    END
  END D
  PIN G
    DIRECTION INPUT ;
    USE SIGNAL ;
    ANTENNAMODEL OXIDE1 ;
      ANTENNAGATEAREA 0.18075 LAYER met1 ;
      ANTENNAMAXAREACAR 0.470263 LAYER met1 ;
      ANTENNAMAXSIDEAREACAR 0.55325 LAYER met1 ;
    PORT
      LAYER met1 ;
        RECT 0.33 2.34 0.59 3.255 ;
        RECT 0.175 2.34 0.59 2.57 ;
    END
  END G
  PIN Q
    DIRECTION OUTPUT ;
    USE SIGNAL ;
    ANTENNADIFFAREA 0.5883 LAYER met1 ;
    PORT
      LAYER met1 ;
        RECT 7.09 2.44 7.49 3.45 ;
        RECT 7.23 0.68 7.49 3.45 ;
        RECT 7.09 0.485 7.32 1.135 ;
    END
  END Q
  PIN QN
    DIRECTION OUTPUT ;
    USE SIGNAL ;
    ANTENNADIFFAREA 0.5883 LAYER met1 ;
    PORT
      LAYER met1 ;
        RECT 7.95 2.44 8.41 3.45 ;
        RECT 8.15 0.68 8.41 3.45 ;
        RECT 7.95 0.485 8.18 1.135 ;
    END
  END QN
  PIN RN
    DIRECTION INPUT ;
    USE SIGNAL ;
    ANTENNAMODEL OXIDE1 ;
      ANTENNAGATEAREA 0.3615 LAYER met1 ;
      ANTENNAMAXAREACAR 0.874689 LAYER met1 ;
      ANTENNAMAXSIDEAREACAR 1.029046 LAYER met1 ;
    PORT
      LAYER met1 ;
        RECT 1.15 1.03 3.86 1.17 ;
        RECT 3.55 0.62 3.86 0.85 ;
        RECT 3.55 0.62 3.81 1.575 ;
        RECT 1.15 0.95 1.38 1.24 ;
    END
  END RN
  PIN SN
    DIRECTION INPUT ;
    USE SIGNAL ;
    ANTENNAMODEL OXIDE1 ;
      ANTENNAGATEAREA 0.18075 LAYER met1 ;
      ANTENNAMAXAREACAR 1.321438 LAYER met1 ;
      ANTENNAMAXSIDEAREACAR 1.554633 LAYER met1 ;
    PORT
      LAYER met1 ;
        RECT 5.39 1.235 5.65 2.01 ;
    END
  END SN
  PIN VDD
    DIRECTION INPUT ;
    USE POWER ;
    SHAPE ABUTMENT ;
    NETEXPR "VDD VDD!" ;
    PORT
      LAYER met1 ;
        RECT 0 3.94 8.74 4.34 ;
    END
  END VDD
  PIN VSS
    DIRECTION INPUT ;
    USE GROUND ;
    SHAPE ABUTMENT ;
    NETEXPR "VSS VSS!" ;
    PORT
      LAYER met1 ;
        RECT 0 -0.2 8.74 0.2 ;
    END
  END VSS
  OBS
    LAYER met1 ;
      RECT 4.96 2.985 5.19 3.275 ;
      RECT 4.96 3.02 6.2 3.16 ;
      RECT 6.06 1.29 6.2 3.16 ;
      RECT 6.015 1.29 6.2 1.775 ;
      RECT 5.97 1.29 6.2 1.58 ;
      RECT 1.91 3.66 4.82 3.8 ;
      RECT 4.68 2.57 4.82 3.8 ;
      RECT 1.91 2.97 2.05 3.8 ;
      RECT 1.865 2.985 2.095 3.275 ;
      RECT 4.68 2.57 5.465 2.71 ;
      RECT 5.05 2.42 5.465 2.71 ;
      RECT 5.05 0.34 5.19 2.71 ;
      RECT 1.865 0.34 2.095 0.63 ;
      RECT 1.865 0.34 5.19 0.48 ;
      RECT 4.18 2.185 4.41 2.475 ;
      RECT 4.215 0.95 4.355 2.475 ;
      RECT 4.18 0.95 4.41 1.24 ;
      RECT 6.34 0.485 6.57 3.45 ;
  END
  PROPERTY CatenaDesignType "deviceLevel" ;
END TLATSRX1_HS

MACRO TLATX1_HS
  CLASS CORE ;
  ORIGIN 0 0 ;
  FOREIGN TLATX1_HS 0 0 ;
  SIZE 6.9 BY 4.14 ;
  SYMMETRY X Y ;
  SITE CoreSite ;
  PIN D
    DIRECTION INPUT ;
    USE SIGNAL ;
    ANTENNAMODEL OXIDE1 ;
      ANTENNAGATEAREA 0.18075 LAYER met1 ;
      ANTENNAMAXAREACAR 0.780636 LAYER met1 ;
      ANTENNAMAXSIDEAREACAR 0.918396 LAYER met1 ;
    PORT
      LAYER met1 ;
        RECT 0.79 2.34 1.05 3.255 ;
        RECT 0.735 2.495 1.05 2.785 ;
    END
  END D
  PIN G
    DIRECTION INPUT ;
    USE SIGNAL ;
    ANTENNAMODEL OXIDE1 ;
      ANTENNAGATEAREA 0.18075 LAYER met1 ;
      ANTENNAMAXAREACAR 0.874689 LAYER met1 ;
      ANTENNAMAXSIDEAREACAR 1.029046 LAYER met1 ;
    PORT
      LAYER met1 ;
        RECT 0.79 0.635 1.05 1.555 ;
        RECT 0.72 0.95 1.05 1.24 ;
    END
  END G
  PIN Q
    DIRECTION OUTPUT ;
    USE SIGNAL ;
    ANTENNADIFFAREA 0.5883 LAYER met1 ;
    PORT
      LAYER met1 ;
        RECT 5.39 0.68 5.65 3.45 ;
        RECT 5.415 0.485 5.645 3.45 ;
    END
  END Q
  PIN QN
    DIRECTION OUTPUT ;
    USE SIGNAL ;
    ANTENNADIFFAREA 0.5883 LAYER met1 ;
    PORT
      LAYER met1 ;
        RECT 6.275 2.44 6.57 3.45 ;
        RECT 6.31 0.68 6.57 3.45 ;
        RECT 6.275 0.485 6.505 1.135 ;
    END
  END QN
  PIN VDD
    DIRECTION INPUT ;
    USE POWER ;
    SHAPE ABUTMENT ;
    NETEXPR "VDD VDD!" ;
    PORT
      LAYER met1 ;
        RECT 0 3.94 6.9 4.34 ;
    END
  END VDD
  PIN VSS
    DIRECTION INPUT ;
    USE GROUND ;
    SHAPE ABUTMENT ;
    NETEXPR "VSS VSS!" ;
    PORT
      LAYER met1 ;
        RECT 0 -0.2 6.9 0.2 ;
    END
  END VSS
  OBS
    LAYER met1 ;
      RECT 1.435 3.485 3.46 3.715 ;
      RECT 3.23 0.415 3.46 3.715 ;
      RECT 1.435 2.945 1.665 3.715 ;
      RECT 1.435 0.415 1.665 0.85 ;
      RECT 1.435 0.415 3.46 0.645 ;
      RECT 2.645 2.505 2.875 2.795 ;
      RECT 2.7 0.95 2.84 2.795 ;
      RECT 2.645 0.95 2.875 1.24 ;
      RECT 0.145 2.945 0.375 3.235 ;
      RECT 0.19 0.51 0.33 3.235 ;
      RECT 0.19 1.63 0.42 1.92 ;
      RECT 0.145 0.51 0.375 0.8 ;
      RECT 4.665 0.485 4.895 3.45 ;
      RECT 3.715 0.51 3.945 3.235 ;
  END
  PROPERTY CatenaDesignType "deviceLevel" ;
END TLATX1_HS

MACRO XNOR2X1_HS
  CLASS CORE ;
  ORIGIN 0 0 ;
  FOREIGN XNOR2X1_HS 0 0 ;
  SIZE 3.68 BY 4.14 ;
  SYMMETRY X Y ;
  SITE CoreSite ;
  PIN A
    DIRECTION INPUT ;
    USE SIGNAL ;
    ANTENNAMODEL OXIDE1 ;
      ANTENNAGATEAREA 0.18075 LAYER met1 ;
      ANTENNAMAXAREACAR 0.540802 LAYER met1 ;
      ANTENNAMAXSIDEAREACAR 0.636238 LAYER met1 ;
    PORT
      LAYER met1 ;
        RECT 0.79 1.41 1.05 2.485 ;
    END
  END A
  PIN B
    DIRECTION INPUT ;
    USE SIGNAL ;
    ANTENNAMODEL OXIDE1 ;
      ANTENNAGATEAREA 0.3615 LAYER met1 ;
      ANTENNAMAXAREACAR 1.850014 LAYER met1 ;
      ANTENNAMAXSIDEAREACAR 1.737206 LAYER met1 ;
    PORT
      LAYER met1 ;
        RECT 0.33 0.895 0.59 2.135 ;
    END
  END B
  PIN VDD
    DIRECTION INPUT ;
    USE POWER ;
    SHAPE ABUTMENT ;
    NETEXPR "VDD VDD!" ;
    PORT
      LAYER met1 ;
        RECT 0 3.94 3.68 4.34 ;
    END
  END VDD
  PIN VSS
    DIRECTION INPUT ;
    USE GROUND ;
    SHAPE ABUTMENT ;
    NETEXPR "VSS VSS!" ;
    PORT
      LAYER met1 ;
        RECT 0 -0.2 3.68 0.2 ;
    END
  END VSS
  PIN Y
    DIRECTION OUTPUT ;
    USE SIGNAL ;
    ANTENNADIFFAREA 0.5883 LAYER met1 ;
    PORT
      LAYER met1 ;
        RECT 2.77 2.38 3.35 2.64 ;
        RECT 3.09 0.995 3.35 2.64 ;
        RECT 2.77 0.995 3.35 1.255 ;
        RECT 2.77 2.38 3.03 3.03 ;
        RECT 2.77 0.55 3.03 1.255 ;
        RECT 2.785 0.42 3.015 1.255 ;
    END
  END Y
  OBS
    LAYER met1 ;
      RECT 1.435 3.305 1.665 3.595 ;
      RECT 1.435 3.305 2.63 3.535 ;
      RECT 2.46 0.45 2.63 3.535 ;
      RECT 2.4 1.3 2.63 1.59 ;
      RECT 1.405 0.45 2.63 0.68 ;
      RECT 1.005 2.915 1.235 3.595 ;
      RECT 1.005 2.915 2.155 3.085 ;
      RECT 1.985 0.82 2.155 3.085 ;
      RECT 1.985 1.725 2.275 1.955 ;
      RECT 1.01 0.82 2.155 0.99 ;
      RECT 1.01 0.45 1.24 0.99 ;
      RECT 1.3 1.715 1.53 2.005 ;
      RECT 1.31 1.13 1.45 2.005 ;
      RECT 0.73 1.13 1.45 1.27 ;
      RECT 0.73 0.35 0.87 1.27 ;
      RECT 0.145 0.35 0.375 0.64 ;
      RECT 0.145 0.35 0.87 0.49 ;
  END
  PROPERTY CatenaDesignType "deviceLevel" ;
END XNOR2X1_HS

MACRO XNOR2X2_HS
  CLASS CORE ;
  ORIGIN 0 0 ;
  FOREIGN XNOR2X2_HS 0 0 ;
  SIZE 3.68 BY 4.14 ;
  SYMMETRY X Y ;
  SITE CoreSite ;
  PIN A
    DIRECTION INPUT ;
    USE SIGNAL ;
    ANTENNAMODEL OXIDE1 ;
      ANTENNAGATEAREA 0.18075 LAYER met1 ;
      ANTENNAMAXAREACAR 0.503181 LAYER met1 ;
      ANTENNAMAXSIDEAREACAR 0.591978 LAYER met1 ;
    PORT
      LAYER met1 ;
        RECT 1.25 1.09 1.51 2.295 ;
        RECT 0.775 1.09 1.51 1.32 ;
    END
  END A
  PIN B
    DIRECTION INPUT ;
    USE SIGNAL ;
    ANTENNAMODEL OXIDE1 ;
      ANTENNAGATEAREA 0.3615 LAYER met1 ;
      ANTENNAMAXAREACAR 0.764177 LAYER met1 ;
      ANTENNAMAXSIDEAREACAR 0.804979 LAYER met1 ;
    PORT
      LAYER met1 ;
        RECT 0.79 1.48 1.05 2.33 ;
    END
  END B
  PIN VDD
    DIRECTION INPUT ;
    USE POWER ;
    SHAPE ABUTMENT ;
    NETEXPR "VDD VDD!" ;
    PORT
      LAYER met1 ;
        RECT 0 3.94 3.68 4.34 ;
    END
  END VDD
  PIN VSS
    DIRECTION INPUT ;
    USE GROUND ;
    SHAPE ABUTMENT ;
    NETEXPR "VSS VSS!" ;
    PORT
      LAYER met1 ;
        RECT 0 -0.2 3.68 0.2 ;
    END
  END VSS
  PIN Y
    DIRECTION OUTPUT ;
    USE SIGNAL ;
    ANTENNADIFFAREA 0.6216 LAYER met1 ;
    PORT
      LAYER met1 ;
        RECT 2.63 2.32 3.015 2.97 ;
        RECT 2.63 0.49 3.015 1.14 ;
        RECT 2.63 0.49 2.89 2.97 ;
    END
  END Y
  OBS
    LAYER met1 ;
      RECT 1.435 3.18 3.415 3.35 ;
      RECT 3.245 1.53 3.415 3.35 ;
      RECT 2.32 0.345 2.46 3.35 ;
      RECT 1.435 3.06 1.665 3.35 ;
      RECT 3.215 1.53 3.445 1.82 ;
      RECT 1.435 0.345 1.665 0.635 ;
      RECT 1.435 0.345 2.46 0.485 ;
      RECT 1.935 2.385 2.165 2.675 ;
      RECT 2.025 1.105 2.165 2.675 ;
      RECT 1.935 1.105 2.165 1.395 ;
      RECT 1.005 3.06 1.235 3.35 ;
      RECT 1.05 2.68 1.19 3.35 ;
      RECT 1.05 2.68 1.79 2.82 ;
      RECT 1.65 0.775 1.79 2.82 ;
      RECT 1.65 1.535 1.88 1.825 ;
      RECT 1.05 0.775 1.79 0.915 ;
      RECT 1.05 0.345 1.19 0.915 ;
      RECT 1.005 0.345 1.235 0.635 ;
      RECT 0.175 2.385 0.455 2.675 ;
      RECT 0.175 0.345 0.345 2.675 ;
      RECT 0.145 0.345 0.375 0.635 ;
  END
  PROPERTY CatenaDesignType "deviceLevel" ;
END XNOR2X2_HS

MACRO XNOR2X4_HS
  CLASS CORE ;
  ORIGIN 0 0 ;
  FOREIGN XNOR2X4_HS 0 0 ;
  SIZE 5.98 BY 4.14 ;
  SYMMETRY X Y ;
  SITE CoreSite ;
  PIN A
    DIRECTION INPUT ;
    USE SIGNAL ;
    ANTENNAMODEL OXIDE1 ;
      ANTENNAGATEAREA 0.18075 LAYER met1 ;
      ANTENNAMAXAREACAR 0.470263 LAYER met1 ;
      ANTENNAMAXSIDEAREACAR 0.55325 LAYER met1 ;
    PORT
      LAYER met1 ;
        RECT 0.32 1.945 0.61 2.175 ;
        RECT 0.33 1.855 0.59 3.205 ;
    END
  END A
  PIN B
    DIRECTION INPUT ;
    USE SIGNAL ;
    ANTENNAMODEL OXIDE1 ;
      ANTENNAGATEAREA 0.51375 LAYER met1 ;
      ANTENNAMAXAREACAR 0.350754 LAYER met1 ;
      ANTENNAMAXSIDEAREACAR 0.346472 LAYER met1 ;
    PORT
      LAYER met1 ;
        RECT 0.79 1.03 1.05 2.265 ;
    END
  END B
  PIN VDD
    DIRECTION INPUT ;
    USE POWER ;
    SHAPE ABUTMENT ;
    NETEXPR "VDD VDD!" ;
    PORT
      LAYER met1 ;
        RECT 0 3.94 5.98 4.34 ;
    END
  END VDD
  PIN VSS
    DIRECTION INPUT ;
    USE GROUND ;
    SHAPE ABUTMENT ;
    NETEXPR "VSS VSS!" ;
    PORT
      LAYER met1 ;
        RECT 0 -0.2 5.98 0.2 ;
    END
  END VSS
  PIN Y
    DIRECTION OUTPUT ;
    USE SIGNAL ;
    ANTENNADIFFAREA 1.2432 LAYER met1 ;
    PORT
      LAYER met1 ;
        RECT 4.47 2.32 4.885 3.33 ;
        RECT 4.47 0.56 4.885 1.21 ;
        RECT 4.47 0.56 4.73 3.33 ;
        RECT 3.795 1.65 4.73 1.88 ;
        RECT 3.795 0.56 4.025 3.33 ;
    END
  END Y
  OBS
    LAYER met1 ;
      RECT 1.985 0.56 2.215 2.97 ;
      RECT 1.985 1.39 3.595 1.62 ;
      RECT 1.525 3.15 3.195 3.38 ;
      RECT 2.905 2.43 3.195 3.38 ;
      RECT 1.525 2.43 1.815 3.38 ;
      RECT 1.615 0.56 1.785 2.17 ;
      RECT 1.615 1.755 1.845 2.045 ;
      RECT 1.555 0.56 1.785 1.21 ;
      RECT 1.005 2.49 1.33 3.115 ;
      RECT 1.19 0.345 1.33 3.115 ;
      RECT 1.19 1.415 1.42 1.705 ;
      RECT 1.005 0.345 1.33 0.82 ;
  END
  PROPERTY CatenaDesignType "deviceLevel" ;
END XNOR2X4_HS

MACRO XOR2X1_HS
  CLASS CORE ;
  ORIGIN 0 0 ;
  FOREIGN XOR2X1_HS 0 0 ;
  SIZE 3.68 BY 4.14 ;
  SYMMETRY X Y ;
  SITE CoreSite ;
  PIN A
    DIRECTION INPUT ;
    USE SIGNAL ;
    ANTENNAMODEL OXIDE1 ;
      ANTENNAGATEAREA 0.18075 LAYER met1 ;
      ANTENNAMAXAREACAR 0.606639 LAYER met1 ;
      ANTENNAMAXSIDEAREACAR 0.713693 LAYER met1 ;
    PORT
      LAYER met1 ;
        RECT 0.79 1.285 1.05 2.525 ;
    END
  END A
  PIN B
    DIRECTION INPUT ;
    USE SIGNAL ;
    ANTENNAMODEL OXIDE1 ;
      ANTENNAGATEAREA 0.3615 LAYER met1 ;
      ANTENNAMAXAREACAR 1.795934 LAYER met1 ;
      ANTENNAMAXSIDEAREACAR 1.767635 LAYER met1 ;
    PORT
      LAYER met1 ;
        RECT 1.25 1.31 1.51 2.55 ;
    END
  END B
  PIN VDD
    DIRECTION INPUT ;
    USE POWER ;
    SHAPE ABUTMENT ;
    NETEXPR "VDD VDD!" ;
    PORT
      LAYER met1 ;
        RECT 0 3.94 3.68 4.34 ;
    END
  END VDD
  PIN VSS
    DIRECTION INPUT ;
    USE GROUND ;
    SHAPE ABUTMENT ;
    NETEXPR "VSS VSS!" ;
    PORT
      LAYER met1 ;
        RECT 0 -0.2 3.68 0.2 ;
    END
  END VSS
  PIN Y
    DIRECTION OUTPUT ;
    USE SIGNAL ;
    ANTENNADIFFAREA 0.5883 LAYER met1 ;
    PORT
      LAYER met1 ;
        RECT 2.785 2.48 3.35 2.74 ;
        RECT 3.09 0.81 3.35 2.74 ;
        RECT 2.77 0.81 3.35 1.07 ;
        RECT 2.77 0.42 3.03 1.07 ;
        RECT 2.785 2.48 3.015 3.49 ;
    END
  END Y
  OBS
    LAYER met1 ;
      RECT 1.405 3.46 1.695 3.69 ;
      RECT 1.405 3.46 2.57 3.63 ;
      RECT 2.31 0.34 2.57 3.63 ;
      RECT 1.405 0.34 1.695 0.57 ;
      RECT 1.405 0.34 2.57 0.51 ;
      RECT 0.975 3.12 2.075 3.29 ;
      RECT 1.815 0.74 2.075 3.29 ;
      RECT 0.975 3.06 1.265 3.29 ;
      RECT 1.005 0.74 2.075 0.91 ;
      RECT 1.005 0.59 1.235 0.91 ;
      RECT 0.145 3.435 0.375 3.725 ;
      RECT 0.175 0.46 0.345 3.725 ;
      RECT 0.175 1.415 0.405 1.705 ;
      RECT 0.145 0.46 0.375 0.75 ;
  END
  PROPERTY CatenaDesignType "deviceLevel" ;
END XOR2X1_HS

MACRO XOR2X2_HS
  CLASS CORE ;
  ORIGIN 0 0 ;
  FOREIGN XOR2X2_HS 0 0 ;
  SIZE 3.68 BY 4.14 ;
  SYMMETRY X Y ;
  SITE CoreSite ;
  PIN A
    DIRECTION INPUT ;
    USE SIGNAL ;
    ANTENNAMODEL OXIDE1 ;
      ANTENNAGATEAREA 0.18075 LAYER met1 ;
      ANTENNAMAXAREACAR 0.512586 LAYER met1 ;
      ANTENNAMAXSIDEAREACAR 0.603043 LAYER met1 ;
    PORT
      LAYER met1 ;
        RECT 2.17 1.18 2.43 2.42 ;
    END
  END A
  PIN B
    DIRECTION INPUT ;
    USE SIGNAL ;
    ANTENNAMODEL OXIDE1 ;
      ANTENNAGATEAREA 0.3615 LAYER met1 ;
      ANTENNAMAXAREACAR 1.821798 LAYER met1 ;
      ANTENNAMAXSIDEAREACAR 1.798064 LAYER met1 ;
    PORT
      LAYER met1 ;
        RECT 0.79 2.055 1.05 3.345 ;
    END
  END B
  PIN VDD
    DIRECTION INPUT ;
    USE POWER ;
    SHAPE ABUTMENT ;
    NETEXPR "VDD VDD!" ;
    PORT
      LAYER met1 ;
        RECT 0 3.94 3.68 4.34 ;
    END
  END VDD
  PIN VSS
    DIRECTION INPUT ;
    USE GROUND ;
    SHAPE ABUTMENT ;
    NETEXPR "VSS VSS!" ;
    PORT
      LAYER met1 ;
        RECT 0 -0.2 3.68 0.2 ;
    END
  END VSS
  PIN Y
    DIRECTION OUTPUT ;
    USE SIGNAL ;
    ANTENNADIFFAREA 0.6216 LAYER met1 ;
    PORT
      LAYER met1 ;
        RECT 2.77 3.005 3.35 3.3 ;
        RECT 3.09 0.41 3.35 3.3 ;
        RECT 2.77 0.41 3.35 0.705 ;
    END
  END Y
  OBS
    LAYER met1 ;
      RECT 1.405 3.465 2.63 3.635 ;
      RECT 2.46 2.68 2.63 3.635 ;
      RECT 1.405 3.405 1.695 3.635 ;
      RECT 2.46 2.68 2.95 2.85 ;
      RECT 2.78 0.87 2.95 2.85 ;
      RECT 2.72 1.29 2.95 1.58 ;
      RECT 2.395 0.87 2.95 1.04 ;
      RECT 2.395 0.34 2.565 1.04 ;
      RECT 1.405 0.34 1.695 0.57 ;
      RECT 1.405 0.34 2.565 0.51 ;
      RECT 1.77 3.035 2.125 3.265 ;
      RECT 1.77 0.75 1.91 3.265 ;
      RECT 1.58 1.95 1.91 2.18 ;
      RECT 1.77 0.75 2.125 1.04 ;
      RECT 0.175 0.46 0.345 3.73 ;
      RECT 0.145 3.245 0.375 3.535 ;
      RECT 0.175 1.415 0.405 1.705 ;
      RECT 0.145 0.46 0.375 0.75 ;
  END
  PROPERTY CatenaDesignType "deviceLevel" ;
END XOR2X2_HS

MACRO XOR2X4_HS
  CLASS CORE ;
  ORIGIN 0 0 ;
  FOREIGN XOR2X4_HS 0 0 ;
  SIZE 5.52 BY 4.14 ;
  SYMMETRY X Y ;
  SITE CoreSite ;
  PIN A
    DIRECTION INPUT ;
    USE SIGNAL ;
    ANTENNAMODEL OXIDE1 ;
      ANTENNAGATEAREA 0.18075 LAYER met1 ;
      ANTENNAMAXAREACAR 0.545505 LAYER met1 ;
      ANTENNAMAXSIDEAREACAR 0.64177 LAYER met1 ;
    PORT
      LAYER met1 ;
        RECT 0.33 1.895 0.59 3.135 ;
    END
  END A
  PIN B
    DIRECTION INPUT ;
    USE SIGNAL ;
    ANTENNAMODEL OXIDE1 ;
      ANTENNAGATEAREA 0.51375 LAYER met1 ;
      ANTENNAMAXAREACAR 0.200195 LAYER met1 ;
      ANTENNAMAXSIDEAREACAR 0.235523 LAYER met1 ;
    PORT
      LAYER met1 ;
        RECT 0.79 0.875 1.05 1.805 ;
    END
  END B
  PIN VDD
    DIRECTION INPUT ;
    USE POWER ;
    SHAPE ABUTMENT ;
    NETEXPR "VDD VDD!" ;
    PORT
      LAYER met1 ;
        RECT 0 3.94 5.52 4.34 ;
    END
  END VDD
  PIN VSS
    DIRECTION INPUT ;
    USE GROUND ;
    SHAPE ABUTMENT ;
    NETEXPR "VSS VSS!" ;
    PORT
      LAYER met1 ;
        RECT 0 -0.2 5.52 0.2 ;
    END
  END VSS
  PIN Y
    DIRECTION OUTPUT ;
    USE SIGNAL ;
    ANTENNADIFFAREA 1.2432 LAYER met1 ;
    PORT
      LAYER met1 ;
        RECT 4.655 2.27 5.19 2.56 ;
        RECT 4.93 0.5 5.19 2.56 ;
        RECT 3.795 1.575 5.19 1.805 ;
        RECT 4.655 0.5 5.19 0.79 ;
        RECT 3.795 0.485 4.025 2.895 ;
    END
  END Y
  OBS
    LAYER met1 ;
      RECT 1.985 1.125 2.215 2.895 ;
      RECT 1.985 1.315 3.595 1.545 ;
      RECT 1.615 0.815 1.845 2.095 ;
      RECT 2.385 0.815 2.675 1.045 ;
      RECT 1.615 0.815 2.675 0.985 ;
      RECT 1.005 3.085 1.36 3.375 ;
      RECT 1.19 0.34 1.36 3.375 ;
      RECT 1.19 1.465 1.42 1.755 ;
      RECT 1.005 0.34 1.36 0.63 ;
      RECT 1.525 0.445 3.195 0.675 ;
  END
  PROPERTY CatenaDesignType "deviceLevel" ;
END XOR2X4_HS

END LIBRARY
